VERSION 5.8 ;
BUSBITCHARS "[]" ;
DIVIDERCHAR "/" ;
UNITS
    DATABASE MICRONS 1000 ;
END UNITS

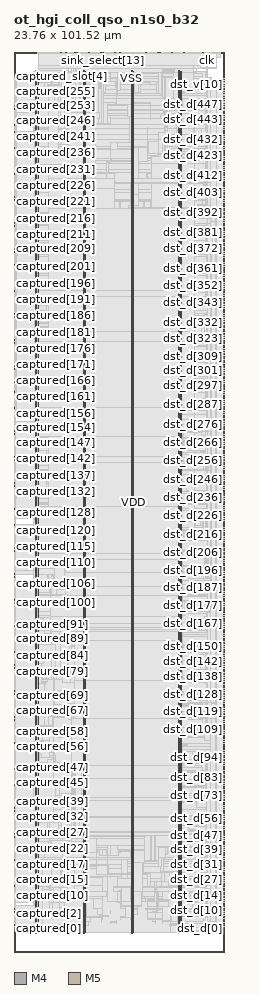
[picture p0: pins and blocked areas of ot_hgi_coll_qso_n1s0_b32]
MACRO ot_hgi_coll_qso_n1s0_b32
  FOREIGN ot_hgi_coll_qso_n1s0_b32 0 0 ;
  CLASS BLOCK ;
  SIZE 23.76 BY 101.52 ;
  PIN captured[0]
    DIRECTION INPUT ;
    USE SIGNAL ;
    PORT
      LAYER M4 ;
        RECT  0 2.688 0.084 2.712 ;
    END
  END captured[0]
  PIN captured[100]
    DIRECTION INPUT ;
    USE SIGNAL ;
    PORT
      LAYER M4 ;
        RECT  0 39.36 0.084 39.384 ;
    END
  END captured[100]
  PIN captured[101]
    DIRECTION INPUT ;
    USE SIGNAL ;
    PORT
      LAYER M4 ;
        RECT  0 39.696 0.084 39.72 ;
    END
  END captured[101]
  PIN captured[102]
    DIRECTION INPUT ;
    USE SIGNAL ;
    PORT
      LAYER M4 ;
        RECT  0 40.08 0.084 40.104 ;
    END
  END captured[102]
  PIN captured[103]
    DIRECTION INPUT ;
    USE SIGNAL ;
    PORT
      LAYER M4 ;
        RECT  0 40.416 0.084 40.44 ;
    END
  END captured[103]
  PIN captured[104]
    DIRECTION INPUT ;
    USE SIGNAL ;
    PORT
      LAYER M4 ;
        RECT  0 40.8 0.084 40.824 ;
    END
  END captured[104]
  PIN captured[105]
    DIRECTION INPUT ;
    USE SIGNAL ;
    PORT
      LAYER M4 ;
        RECT  0 41.184 0.084 41.208 ;
    END
  END captured[105]
  PIN captured[106]
    DIRECTION INPUT ;
    USE SIGNAL ;
    PORT
      LAYER M4 ;
        RECT  0 41.52 0.084 41.544 ;
    END
  END captured[106]
  PIN captured[107]
    DIRECTION INPUT ;
    USE SIGNAL ;
    PORT
      LAYER M4 ;
        RECT  0 41.904 0.084 41.928 ;
    END
  END captured[107]
  PIN captured[108]
    DIRECTION INPUT ;
    USE SIGNAL ;
    PORT
      LAYER M4 ;
        RECT  0 42.288 0.084 42.312 ;
    END
  END captured[108]
  PIN captured[109]
    DIRECTION INPUT ;
    USE SIGNAL ;
    PORT
      LAYER M4 ;
        RECT  0 42.624 0.084 42.648 ;
    END
  END captured[109]
  PIN captured[10]
    DIRECTION INPUT ;
    USE SIGNAL ;
    PORT
      LAYER M4 ;
        RECT  0 6.336 0.084 6.36 ;
    END
  END captured[10]
  PIN captured[110]
    DIRECTION INPUT ;
    USE SIGNAL ;
    PORT
      LAYER M4 ;
        RECT  0 43.008 0.084 43.032 ;
    END
  END captured[110]
  PIN captured[111]
    DIRECTION INPUT ;
    USE SIGNAL ;
    PORT
      LAYER M4 ;
        RECT  0 43.392 0.084 43.416 ;
    END
  END captured[111]
  PIN captured[112]
    DIRECTION INPUT ;
    USE SIGNAL ;
    PORT
      LAYER M4 ;
        RECT  0 43.728 0.084 43.752 ;
    END
  END captured[112]
  PIN captured[113]
    DIRECTION INPUT ;
    USE SIGNAL ;
    PORT
      LAYER M4 ;
        RECT  0 44.112 0.084 44.136 ;
    END
  END captured[113]
  PIN captured[114]
    DIRECTION INPUT ;
    USE SIGNAL ;
    PORT
      LAYER M4 ;
        RECT  0 44.496 0.084 44.52 ;
    END
  END captured[114]
  PIN captured[115]
    DIRECTION INPUT ;
    USE SIGNAL ;
    PORT
      LAYER M4 ;
        RECT  0 44.832 0.084 44.856 ;
    END
  END captured[115]
  PIN captured[116]
    DIRECTION INPUT ;
    USE SIGNAL ;
    PORT
      LAYER M4 ;
        RECT  0 45.216 0.084 45.24 ;
    END
  END captured[116]
  PIN captured[117]
    DIRECTION INPUT ;
    USE SIGNAL ;
    PORT
      LAYER M4 ;
        RECT  0 45.552 0.084 45.576 ;
    END
  END captured[117]
  PIN captured[118]
    DIRECTION INPUT ;
    USE SIGNAL ;
    PORT
      LAYER M4 ;
        RECT  0 45.936 0.084 45.96 ;
    END
  END captured[118]
  PIN captured[119]
    DIRECTION INPUT ;
    USE SIGNAL ;
    PORT
      LAYER M4 ;
        RECT  0 46.32 0.084 46.344 ;
    END
  END captured[119]
  PIN captured[11]
    DIRECTION INPUT ;
    USE SIGNAL ;
    PORT
      LAYER M4 ;
        RECT  0 6.72 0.084 6.744 ;
    END
  END captured[11]
  PIN captured[120]
    DIRECTION INPUT ;
    USE SIGNAL ;
    PORT
      LAYER M4 ;
        RECT  0 46.656 0.084 46.68 ;
    END
  END captured[120]
  PIN captured[121]
    DIRECTION INPUT ;
    USE SIGNAL ;
    PORT
      LAYER M4 ;
        RECT  0 47.04 0.084 47.064 ;
    END
  END captured[121]
  PIN captured[122]
    DIRECTION INPUT ;
    USE SIGNAL ;
    PORT
      LAYER M4 ;
        RECT  0 47.424 0.084 47.448 ;
    END
  END captured[122]
  PIN captured[123]
    DIRECTION INPUT ;
    USE SIGNAL ;
    PORT
      LAYER M4 ;
        RECT  0 47.76 0.084 47.784 ;
    END
  END captured[123]
  PIN captured[124]
    DIRECTION INPUT ;
    USE SIGNAL ;
    PORT
      LAYER M4 ;
        RECT  0 48.144 0.084 48.168 ;
    END
  END captured[124]
  PIN captured[125]
    DIRECTION INPUT ;
    USE SIGNAL ;
    PORT
      LAYER M4 ;
        RECT  0 48.528 0.084 48.552 ;
    END
  END captured[125]
  PIN captured[126]
    DIRECTION INPUT ;
    USE SIGNAL ;
    PORT
      LAYER M4 ;
        RECT  0 48.864 0.084 48.888 ;
    END
  END captured[126]
  PIN captured[127]
    DIRECTION INPUT ;
    USE SIGNAL ;
    PORT
      LAYER M4 ;
        RECT  0 49.248 0.084 49.272 ;
    END
  END captured[127]
  PIN captured[128]
    DIRECTION INPUT ;
    USE SIGNAL ;
    PORT
      LAYER M4 ;
        RECT  0 49.584 0.084 49.608 ;
    END
  END captured[128]
  PIN captured[129]
    DIRECTION INPUT ;
    USE SIGNAL ;
    PORT
      LAYER M4 ;
        RECT  0 49.968 0.084 49.992 ;
    END
  END captured[129]
  PIN captured[12]
    DIRECTION INPUT ;
    USE SIGNAL ;
    PORT
      LAYER M4 ;
        RECT  0 7.056 0.084 7.08 ;
    END
  END captured[12]
  PIN captured[130]
    DIRECTION INPUT ;
    USE SIGNAL ;
    PORT
      LAYER M4 ;
        RECT  0 50.352 0.084 50.376 ;
    END
  END captured[130]
  PIN captured[131]
    DIRECTION INPUT ;
    USE SIGNAL ;
    PORT
      LAYER M4 ;
        RECT  0 50.688 0.084 50.712 ;
    END
  END captured[131]
  PIN captured[132]
    DIRECTION INPUT ;
    USE SIGNAL ;
    PORT
      LAYER M4 ;
        RECT  0 51.072 0.084 51.096 ;
    END
  END captured[132]
  PIN captured[133]
    DIRECTION INPUT ;
    USE SIGNAL ;
    PORT
      LAYER M4 ;
        RECT  0 51.456 0.084 51.48 ;
    END
  END captured[133]
  PIN captured[134]
    DIRECTION INPUT ;
    USE SIGNAL ;
    PORT
      LAYER M4 ;
        RECT  0 51.792 0.084 51.816 ;
    END
  END captured[134]
  PIN captured[135]
    DIRECTION INPUT ;
    USE SIGNAL ;
    PORT
      LAYER M4 ;
        RECT  0 52.176 0.084 52.2 ;
    END
  END captured[135]
  PIN captured[136]
    DIRECTION INPUT ;
    USE SIGNAL ;
    PORT
      LAYER M4 ;
        RECT  0 52.56 0.084 52.584 ;
    END
  END captured[136]
  PIN captured[137]
    DIRECTION INPUT ;
    USE SIGNAL ;
    PORT
      LAYER M4 ;
        RECT  0 52.896 0.084 52.92 ;
    END
  END captured[137]
  PIN captured[138]
    DIRECTION INPUT ;
    USE SIGNAL ;
    PORT
      LAYER M4 ;
        RECT  0 53.28 0.084 53.304 ;
    END
  END captured[138]
  PIN captured[139]
    DIRECTION INPUT ;
    USE SIGNAL ;
    PORT
      LAYER M4 ;
        RECT  0 53.664 0.084 53.688 ;
    END
  END captured[139]
  PIN captured[13]
    DIRECTION INPUT ;
    USE SIGNAL ;
    PORT
      LAYER M4 ;
        RECT  0 7.44 0.084 7.464 ;
    END
  END captured[13]
  PIN captured[140]
    DIRECTION INPUT ;
    USE SIGNAL ;
    PORT
      LAYER M4 ;
        RECT  0 54 0.084 54.024 ;
    END
  END captured[140]
  PIN captured[141]
    DIRECTION INPUT ;
    USE SIGNAL ;
    PORT
      LAYER M4 ;
        RECT  0 54.384 0.084 54.408 ;
    END
  END captured[141]
  PIN captured[142]
    DIRECTION INPUT ;
    USE SIGNAL ;
    PORT
      LAYER M4 ;
        RECT  0 54.72 0.084 54.744 ;
    END
  END captured[142]
  PIN captured[143]
    DIRECTION INPUT ;
    USE SIGNAL ;
    PORT
      LAYER M4 ;
        RECT  0 55.104 0.084 55.128 ;
    END
  END captured[143]
  PIN captured[144]
    DIRECTION INPUT ;
    USE SIGNAL ;
    PORT
      LAYER M4 ;
        RECT  0 55.488 0.084 55.512 ;
    END
  END captured[144]
  PIN captured[145]
    DIRECTION INPUT ;
    USE SIGNAL ;
    PORT
      LAYER M4 ;
        RECT  0 55.824 0.084 55.848 ;
    END
  END captured[145]
  PIN captured[146]
    DIRECTION INPUT ;
    USE SIGNAL ;
    PORT
      LAYER M4 ;
        RECT  0 56.208 0.084 56.232 ;
    END
  END captured[146]
  PIN captured[147]
    DIRECTION INPUT ;
    USE SIGNAL ;
    PORT
      LAYER M4 ;
        RECT  0 56.592 0.084 56.616 ;
    END
  END captured[147]
  PIN captured[148]
    DIRECTION INPUT ;
    USE SIGNAL ;
    PORT
      LAYER M4 ;
        RECT  0 56.928 0.084 56.952 ;
    END
  END captured[148]
  PIN captured[149]
    DIRECTION INPUT ;
    USE SIGNAL ;
    PORT
      LAYER M4 ;
        RECT  0 57.312 0.084 57.336 ;
    END
  END captured[149]
  PIN captured[14]
    DIRECTION INPUT ;
    USE SIGNAL ;
    PORT
      LAYER M4 ;
        RECT  0 7.824 0.084 7.848 ;
    END
  END captured[14]
  PIN captured[150]
    DIRECTION INPUT ;
    USE SIGNAL ;
    PORT
      LAYER M4 ;
        RECT  0 57.696 0.084 57.72 ;
    END
  END captured[150]
  PIN captured[151]
    DIRECTION INPUT ;
    USE SIGNAL ;
    PORT
      LAYER M4 ;
        RECT  0 58.032 0.084 58.056 ;
    END
  END captured[151]
  PIN captured[152]
    DIRECTION INPUT ;
    USE SIGNAL ;
    PORT
      LAYER M4 ;
        RECT  0 58.416 0.084 58.44 ;
    END
  END captured[152]
  PIN captured[153]
    DIRECTION INPUT ;
    USE SIGNAL ;
    PORT
      LAYER M4 ;
        RECT  0 58.752 0.084 58.776 ;
    END
  END captured[153]
  PIN captured[154]
    DIRECTION INPUT ;
    USE SIGNAL ;
    PORT
      LAYER M4 ;
        RECT  0 59.136 0.084 59.16 ;
    END
  END captured[154]
  PIN captured[155]
    DIRECTION INPUT ;
    USE SIGNAL ;
    PORT
      LAYER M4 ;
        RECT  0 59.52 0.084 59.544 ;
    END
  END captured[155]
  PIN captured[156]
    DIRECTION INPUT ;
    USE SIGNAL ;
    PORT
      LAYER M4 ;
        RECT  0 59.856 0.084 59.88 ;
    END
  END captured[156]
  PIN captured[157]
    DIRECTION INPUT ;
    USE SIGNAL ;
    PORT
      LAYER M4 ;
        RECT  0 60.24 0.084 60.264 ;
    END
  END captured[157]
  PIN captured[158]
    DIRECTION INPUT ;
    USE SIGNAL ;
    PORT
      LAYER M4 ;
        RECT  0 60.624 0.084 60.648 ;
    END
  END captured[158]
  PIN captured[159]
    DIRECTION INPUT ;
    USE SIGNAL ;
    PORT
      LAYER M4 ;
        RECT  0 60.96 0.084 60.984 ;
    END
  END captured[159]
  PIN captured[15]
    DIRECTION INPUT ;
    USE SIGNAL ;
    PORT
      LAYER M4 ;
        RECT  0 8.16 0.084 8.184 ;
    END
  END captured[15]
  PIN captured[160]
    DIRECTION INPUT ;
    USE SIGNAL ;
    PORT
      LAYER M4 ;
        RECT  0 61.344 0.084 61.368 ;
    END
  END captured[160]
  PIN captured[161]
    DIRECTION INPUT ;
    USE SIGNAL ;
    PORT
      LAYER M4 ;
        RECT  0 61.728 0.084 61.752 ;
    END
  END captured[161]
  PIN captured[162]
    DIRECTION INPUT ;
    USE SIGNAL ;
    PORT
      LAYER M4 ;
        RECT  0 62.064 0.084 62.088 ;
    END
  END captured[162]
  PIN captured[163]
    DIRECTION INPUT ;
    USE SIGNAL ;
    PORT
      LAYER M4 ;
        RECT  0 62.448 0.084 62.472 ;
    END
  END captured[163]
  PIN captured[164]
    DIRECTION INPUT ;
    USE SIGNAL ;
    PORT
      LAYER M4 ;
        RECT  0 62.784 0.084 62.808 ;
    END
  END captured[164]
  PIN captured[165]
    DIRECTION INPUT ;
    USE SIGNAL ;
    PORT
      LAYER M4 ;
        RECT  0 63.168 0.084 63.192 ;
    END
  END captured[165]
  PIN captured[166]
    DIRECTION INPUT ;
    USE SIGNAL ;
    PORT
      LAYER M4 ;
        RECT  0 63.552 0.084 63.576 ;
    END
  END captured[166]
  PIN captured[167]
    DIRECTION INPUT ;
    USE SIGNAL ;
    PORT
      LAYER M4 ;
        RECT  0 63.888 0.084 63.912 ;
    END
  END captured[167]
  PIN captured[168]
    DIRECTION INPUT ;
    USE SIGNAL ;
    PORT
      LAYER M4 ;
        RECT  0 64.272 0.084 64.296 ;
    END
  END captured[168]
  PIN captured[169]
    DIRECTION INPUT ;
    USE SIGNAL ;
    PORT
      LAYER M4 ;
        RECT  0 64.656 0.084 64.68 ;
    END
  END captured[169]
  PIN captured[16]
    DIRECTION INPUT ;
    USE SIGNAL ;
    PORT
      LAYER M4 ;
        RECT  0 8.544 0.084 8.568 ;
    END
  END captured[16]
  PIN captured[170]
    DIRECTION INPUT ;
    USE SIGNAL ;
    PORT
      LAYER M4 ;
        RECT  0 64.992 0.084 65.016 ;
    END
  END captured[170]
  PIN captured[171]
    DIRECTION INPUT ;
    USE SIGNAL ;
    PORT
      LAYER M4 ;
        RECT  0 65.376 0.084 65.4 ;
    END
  END captured[171]
  PIN captured[172]
    DIRECTION INPUT ;
    USE SIGNAL ;
    PORT
      LAYER M4 ;
        RECT  0 65.76 0.084 65.784 ;
    END
  END captured[172]
  PIN captured[173]
    DIRECTION INPUT ;
    USE SIGNAL ;
    PORT
      LAYER M4 ;
        RECT  0 66.096 0.084 66.12 ;
    END
  END captured[173]
  PIN captured[174]
    DIRECTION INPUT ;
    USE SIGNAL ;
    PORT
      LAYER M4 ;
        RECT  0 66.48 0.084 66.504 ;
    END
  END captured[174]
  PIN captured[175]
    DIRECTION INPUT ;
    USE SIGNAL ;
    PORT
      LAYER M4 ;
        RECT  0 66.864 0.084 66.888 ;
    END
  END captured[175]
  PIN captured[176]
    DIRECTION INPUT ;
    USE SIGNAL ;
    PORT
      LAYER M4 ;
        RECT  0 67.2 0.084 67.224 ;
    END
  END captured[176]
  PIN captured[177]
    DIRECTION INPUT ;
    USE SIGNAL ;
    PORT
      LAYER M4 ;
        RECT  0 67.584 0.084 67.608 ;
    END
  END captured[177]
  PIN captured[178]
    DIRECTION INPUT ;
    USE SIGNAL ;
    PORT
      LAYER M4 ;
        RECT  0 67.92 0.084 67.944 ;
    END
  END captured[178]
  PIN captured[179]
    DIRECTION INPUT ;
    USE SIGNAL ;
    PORT
      LAYER M4 ;
        RECT  0 68.304 0.084 68.328 ;
    END
  END captured[179]
  PIN captured[17]
    DIRECTION INPUT ;
    USE SIGNAL ;
    PORT
      LAYER M4 ;
        RECT  0 8.928 0.084 8.952 ;
    END
  END captured[17]
  PIN captured[180]
    DIRECTION INPUT ;
    USE SIGNAL ;
    PORT
      LAYER M4 ;
        RECT  0 68.688 0.084 68.712 ;
    END
  END captured[180]
  PIN captured[181]
    DIRECTION INPUT ;
    USE SIGNAL ;
    PORT
      LAYER M4 ;
        RECT  0 69.024 0.084 69.048 ;
    END
  END captured[181]
  PIN captured[182]
    DIRECTION INPUT ;
    USE SIGNAL ;
    PORT
      LAYER M4 ;
        RECT  0 69.408 0.084 69.432 ;
    END
  END captured[182]
  PIN captured[183]
    DIRECTION INPUT ;
    USE SIGNAL ;
    PORT
      LAYER M4 ;
        RECT  0 69.792 0.084 69.816 ;
    END
  END captured[183]
  PIN captured[184]
    DIRECTION INPUT ;
    USE SIGNAL ;
    PORT
      LAYER M4 ;
        RECT  0 70.128 0.084 70.152 ;
    END
  END captured[184]
  PIN captured[185]
    DIRECTION INPUT ;
    USE SIGNAL ;
    PORT
      LAYER M4 ;
        RECT  0 70.512 0.084 70.536 ;
    END
  END captured[185]
  PIN captured[186]
    DIRECTION INPUT ;
    USE SIGNAL ;
    PORT
      LAYER M4 ;
        RECT  0 70.896 0.084 70.92 ;
    END
  END captured[186]
  PIN captured[187]
    DIRECTION INPUT ;
    USE SIGNAL ;
    PORT
      LAYER M4 ;
        RECT  0 71.232 0.084 71.256 ;
    END
  END captured[187]
  PIN captured[188]
    DIRECTION INPUT ;
    USE SIGNAL ;
    PORT
      LAYER M4 ;
        RECT  0 71.616 0.084 71.64 ;
    END
  END captured[188]
  PIN captured[189]
    DIRECTION INPUT ;
    USE SIGNAL ;
    PORT
      LAYER M4 ;
        RECT  0 71.952 0.084 71.976 ;
    END
  END captured[189]
  PIN captured[18]
    DIRECTION INPUT ;
    USE SIGNAL ;
    PORT
      LAYER M4 ;
        RECT  0 9.264 0.084 9.288 ;
    END
  END captured[18]
  PIN captured[190]
    DIRECTION INPUT ;
    USE SIGNAL ;
    PORT
      LAYER M4 ;
        RECT  0 72.336 0.084 72.36 ;
    END
  END captured[190]
  PIN captured[191]
    DIRECTION INPUT ;
    USE SIGNAL ;
    PORT
      LAYER M4 ;
        RECT  0 72.72 0.084 72.744 ;
    END
  END captured[191]
  PIN captured[192]
    DIRECTION INPUT ;
    USE SIGNAL ;
    PORT
      LAYER M4 ;
        RECT  0 73.056 0.084 73.08 ;
    END
  END captured[192]
  PIN captured[193]
    DIRECTION INPUT ;
    USE SIGNAL ;
    PORT
      LAYER M4 ;
        RECT  0 73.44 0.084 73.464 ;
    END
  END captured[193]
  PIN captured[194]
    DIRECTION INPUT ;
    USE SIGNAL ;
    PORT
      LAYER M4 ;
        RECT  0 73.824 0.084 73.848 ;
    END
  END captured[194]
  PIN captured[195]
    DIRECTION INPUT ;
    USE SIGNAL ;
    PORT
      LAYER M4 ;
        RECT  0 74.16 0.084 74.184 ;
    END
  END captured[195]
  PIN captured[196]
    DIRECTION INPUT ;
    USE SIGNAL ;
    PORT
      LAYER M4 ;
        RECT  0 74.544 0.084 74.568 ;
    END
  END captured[196]
  PIN captured[197]
    DIRECTION INPUT ;
    USE SIGNAL ;
    PORT
      LAYER M4 ;
        RECT  0 74.928 0.084 74.952 ;
    END
  END captured[197]
  PIN captured[198]
    DIRECTION INPUT ;
    USE SIGNAL ;
    PORT
      LAYER M4 ;
        RECT  0 75.264 0.084 75.288 ;
    END
  END captured[198]
  PIN captured[199]
    DIRECTION INPUT ;
    USE SIGNAL ;
    PORT
      LAYER M4 ;
        RECT  0 75.648 0.084 75.672 ;
    END
  END captured[199]
  PIN captured[19]
    DIRECTION INPUT ;
    USE SIGNAL ;
    PORT
      LAYER M4 ;
        RECT  0 9.648 0.084 9.672 ;
    END
  END captured[19]
  PIN captured[1]
    DIRECTION INPUT ;
    USE SIGNAL ;
    PORT
      LAYER M4 ;
        RECT  0 3.024 0.084 3.048 ;
    END
  END captured[1]
  PIN captured[200]
    DIRECTION INPUT ;
    USE SIGNAL ;
    PORT
      LAYER M4 ;
        RECT  0 75.984 0.084 76.008 ;
    END
  END captured[200]
  PIN captured[201]
    DIRECTION INPUT ;
    USE SIGNAL ;
    PORT
      LAYER M4 ;
        RECT  0 76.368 0.084 76.392 ;
    END
  END captured[201]
  PIN captured[202]
    DIRECTION INPUT ;
    USE SIGNAL ;
    PORT
      LAYER M4 ;
        RECT  0 76.752 0.084 76.776 ;
    END
  END captured[202]
  PIN captured[203]
    DIRECTION INPUT ;
    USE SIGNAL ;
    PORT
      LAYER M4 ;
        RECT  0 77.088 0.084 77.112 ;
    END
  END captured[203]
  PIN captured[204]
    DIRECTION INPUT ;
    USE SIGNAL ;
    PORT
      LAYER M4 ;
        RECT  0 77.472 0.084 77.496 ;
    END
  END captured[204]
  PIN captured[205]
    DIRECTION INPUT ;
    USE SIGNAL ;
    PORT
      LAYER M4 ;
        RECT  0 77.856 0.084 77.88 ;
    END
  END captured[205]
  PIN captured[206]
    DIRECTION INPUT ;
    USE SIGNAL ;
    PORT
      LAYER M4 ;
        RECT  0 78.192 0.084 78.216 ;
    END
  END captured[206]
  PIN captured[207]
    DIRECTION INPUT ;
    USE SIGNAL ;
    PORT
      LAYER M4 ;
        RECT  0 78.576 0.084 78.6 ;
    END
  END captured[207]
  PIN captured[208]
    DIRECTION INPUT ;
    USE SIGNAL ;
    PORT
      LAYER M4 ;
        RECT  0 78.96 0.084 78.984 ;
    END
  END captured[208]
  PIN captured[209]
    DIRECTION INPUT ;
    USE SIGNAL ;
    PORT
      LAYER M4 ;
        RECT  0 79.296 0.084 79.32 ;
    END
  END captured[209]
  PIN captured[20]
    DIRECTION INPUT ;
    USE SIGNAL ;
    PORT
      LAYER M4 ;
        RECT  0 9.984 0.084 10.008 ;
    END
  END captured[20]
  PIN captured[210]
    DIRECTION INPUT ;
    USE SIGNAL ;
    PORT
      LAYER M4 ;
        RECT  0 79.68 0.084 79.704 ;
    END
  END captured[210]
  PIN captured[211]
    DIRECTION INPUT ;
    USE SIGNAL ;
    PORT
      LAYER M4 ;
        RECT  0 80.064 0.084 80.088 ;
    END
  END captured[211]
  PIN captured[212]
    DIRECTION INPUT ;
    USE SIGNAL ;
    PORT
      LAYER M4 ;
        RECT  0 80.4 0.084 80.424 ;
    END
  END captured[212]
  PIN captured[213]
    DIRECTION INPUT ;
    USE SIGNAL ;
    PORT
      LAYER M4 ;
        RECT  0 80.784 0.084 80.808 ;
    END
  END captured[213]
  PIN captured[214]
    DIRECTION INPUT ;
    USE SIGNAL ;
    PORT
      LAYER M4 ;
        RECT  0 81.12 0.084 81.144 ;
    END
  END captured[214]
  PIN captured[215]
    DIRECTION INPUT ;
    USE SIGNAL ;
    PORT
      LAYER M4 ;
        RECT  0 81.504 0.084 81.528 ;
    END
  END captured[215]
  PIN captured[216]
    DIRECTION INPUT ;
    USE SIGNAL ;
    PORT
      LAYER M4 ;
        RECT  0 81.888 0.084 81.912 ;
    END
  END captured[216]
  PIN captured[217]
    DIRECTION INPUT ;
    USE SIGNAL ;
    PORT
      LAYER M4 ;
        RECT  0 82.224 0.084 82.248 ;
    END
  END captured[217]
  PIN captured[218]
    DIRECTION INPUT ;
    USE SIGNAL ;
    PORT
      LAYER M4 ;
        RECT  0 82.608 0.084 82.632 ;
    END
  END captured[218]
  PIN captured[219]
    DIRECTION INPUT ;
    USE SIGNAL ;
    PORT
      LAYER M4 ;
        RECT  0 82.992 0.084 83.016 ;
    END
  END captured[219]
  PIN captured[21]
    DIRECTION INPUT ;
    USE SIGNAL ;
    PORT
      LAYER M4 ;
        RECT  0 10.368 0.084 10.392 ;
    END
  END captured[21]
  PIN captured[220]
    DIRECTION INPUT ;
    USE SIGNAL ;
    PORT
      LAYER M4 ;
        RECT  0 83.328 0.084 83.352 ;
    END
  END captured[220]
  PIN captured[221]
    DIRECTION INPUT ;
    USE SIGNAL ;
    PORT
      LAYER M4 ;
        RECT  0 83.712 0.084 83.736 ;
    END
  END captured[221]
  PIN captured[222]
    DIRECTION INPUT ;
    USE SIGNAL ;
    PORT
      LAYER M4 ;
        RECT  0 84.096 0.084 84.12 ;
    END
  END captured[222]
  PIN captured[223]
    DIRECTION INPUT ;
    USE SIGNAL ;
    PORT
      LAYER M4 ;
        RECT  0 84.432 0.084 84.456 ;
    END
  END captured[223]
  PIN captured[224]
    DIRECTION INPUT ;
    USE SIGNAL ;
    PORT
      LAYER M4 ;
        RECT  0 84.816 0.084 84.84 ;
    END
  END captured[224]
  PIN captured[225]
    DIRECTION INPUT ;
    USE SIGNAL ;
    PORT
      LAYER M4 ;
        RECT  0 85.152 0.084 85.176 ;
    END
  END captured[225]
  PIN captured[226]
    DIRECTION INPUT ;
    USE SIGNAL ;
    PORT
      LAYER M4 ;
        RECT  0 85.536 0.084 85.56 ;
    END
  END captured[226]
  PIN captured[227]
    DIRECTION INPUT ;
    USE SIGNAL ;
    PORT
      LAYER M4 ;
        RECT  0 85.92 0.084 85.944 ;
    END
  END captured[227]
  PIN captured[228]
    DIRECTION INPUT ;
    USE SIGNAL ;
    PORT
      LAYER M4 ;
        RECT  0 86.256 0.084 86.28 ;
    END
  END captured[228]
  PIN captured[229]
    DIRECTION INPUT ;
    USE SIGNAL ;
    PORT
      LAYER M4 ;
        RECT  0 86.64 0.084 86.664 ;
    END
  END captured[229]
  PIN captured[22]
    DIRECTION INPUT ;
    USE SIGNAL ;
    PORT
      LAYER M4 ;
        RECT  0 10.752 0.084 10.776 ;
    END
  END captured[22]
  PIN captured[230]
    DIRECTION INPUT ;
    USE SIGNAL ;
    PORT
      LAYER M4 ;
        RECT  0 87.024 0.084 87.048 ;
    END
  END captured[230]
  PIN captured[231]
    DIRECTION INPUT ;
    USE SIGNAL ;
    PORT
      LAYER M4 ;
        RECT  0 87.36 0.084 87.384 ;
    END
  END captured[231]
  PIN captured[232]
    DIRECTION INPUT ;
    USE SIGNAL ;
    PORT
      LAYER M4 ;
        RECT  0 87.744 0.084 87.768 ;
    END
  END captured[232]
  PIN captured[233]
    DIRECTION INPUT ;
    USE SIGNAL ;
    PORT
      LAYER M4 ;
        RECT  0 88.128 0.084 88.152 ;
    END
  END captured[233]
  PIN captured[234]
    DIRECTION INPUT ;
    USE SIGNAL ;
    PORT
      LAYER M4 ;
        RECT  0 88.464 0.084 88.488 ;
    END
  END captured[234]
  PIN captured[235]
    DIRECTION INPUT ;
    USE SIGNAL ;
    PORT
      LAYER M4 ;
        RECT  0 88.848 0.084 88.872 ;
    END
  END captured[235]
  PIN captured[236]
    DIRECTION INPUT ;
    USE SIGNAL ;
    PORT
      LAYER M4 ;
        RECT  0 89.232 0.084 89.256 ;
    END
  END captured[236]
  PIN captured[237]
    DIRECTION INPUT ;
    USE SIGNAL ;
    PORT
      LAYER M4 ;
        RECT  0 89.568 0.084 89.592 ;
    END
  END captured[237]
  PIN captured[238]
    DIRECTION INPUT ;
    USE SIGNAL ;
    PORT
      LAYER M4 ;
        RECT  0 89.952 0.084 89.976 ;
    END
  END captured[238]
  PIN captured[239]
    DIRECTION INPUT ;
    USE SIGNAL ;
    PORT
      LAYER M4 ;
        RECT  0 90.288 0.084 90.312 ;
    END
  END captured[239]
  PIN captured[23]
    DIRECTION INPUT ;
    USE SIGNAL ;
    PORT
      LAYER M4 ;
        RECT  0 11.088 0.084 11.112 ;
    END
  END captured[23]
  PIN captured[240]
    DIRECTION INPUT ;
    USE SIGNAL ;
    PORT
      LAYER M4 ;
        RECT  0 90.672 0.084 90.696 ;
    END
  END captured[240]
  PIN captured[241]
    DIRECTION INPUT ;
    USE SIGNAL ;
    PORT
      LAYER M4 ;
        RECT  0 91.056 0.084 91.08 ;
    END
  END captured[241]
  PIN captured[242]
    DIRECTION INPUT ;
    USE SIGNAL ;
    PORT
      LAYER M4 ;
        RECT  0 91.392 0.084 91.416 ;
    END
  END captured[242]
  PIN captured[243]
    DIRECTION INPUT ;
    USE SIGNAL ;
    PORT
      LAYER M4 ;
        RECT  0 91.776 0.084 91.8 ;
    END
  END captured[243]
  PIN captured[244]
    DIRECTION INPUT ;
    USE SIGNAL ;
    PORT
      LAYER M4 ;
        RECT  0 92.16 0.084 92.184 ;
    END
  END captured[244]
  PIN captured[245]
    DIRECTION INPUT ;
    USE SIGNAL ;
    PORT
      LAYER M4 ;
        RECT  0 92.496 0.084 92.52 ;
    END
  END captured[245]
  PIN captured[246]
    DIRECTION INPUT ;
    USE SIGNAL ;
    PORT
      LAYER M4 ;
        RECT  0 92.88 0.084 92.904 ;
    END
  END captured[246]
  PIN captured[247]
    DIRECTION INPUT ;
    USE SIGNAL ;
    PORT
      LAYER M4 ;
        RECT  0 93.264 0.084 93.288 ;
    END
  END captured[247]
  PIN captured[248]
    DIRECTION INPUT ;
    USE SIGNAL ;
    PORT
      LAYER M4 ;
        RECT  0 93.6 0.084 93.624 ;
    END
  END captured[248]
  PIN captured[249]
    DIRECTION INPUT ;
    USE SIGNAL ;
    PORT
      LAYER M4 ;
        RECT  0 93.984 0.084 94.008 ;
    END
  END captured[249]
  PIN captured[24]
    DIRECTION INPUT ;
    USE SIGNAL ;
    PORT
      LAYER M4 ;
        RECT  0 11.472 0.084 11.496 ;
    END
  END captured[24]
  PIN captured[250]
    DIRECTION INPUT ;
    USE SIGNAL ;
    PORT
      LAYER M4 ;
        RECT  0 94.32 0.084 94.344 ;
    END
  END captured[250]
  PIN captured[251]
    DIRECTION INPUT ;
    USE SIGNAL ;
    PORT
      LAYER M4 ;
        RECT  0 94.704 0.084 94.728 ;
    END
  END captured[251]
  PIN captured[252]
    DIRECTION INPUT ;
    USE SIGNAL ;
    PORT
      LAYER M4 ;
        RECT  0 95.088 0.084 95.112 ;
    END
  END captured[252]
  PIN captured[253]
    DIRECTION INPUT ;
    USE SIGNAL ;
    PORT
      LAYER M4 ;
        RECT  0 95.424 0.084 95.448 ;
    END
  END captured[253]
  PIN captured[254]
    DIRECTION INPUT ;
    USE SIGNAL ;
    PORT
      LAYER M4 ;
        RECT  0 95.808 0.084 95.832 ;
    END
  END captured[254]
  PIN captured[255]
    DIRECTION INPUT ;
    USE SIGNAL ;
    PORT
      LAYER M4 ;
        RECT  0 96.192 0.084 96.216 ;
    END
  END captured[255]
  PIN captured[25]
    DIRECTION INPUT ;
    USE SIGNAL ;
    PORT
      LAYER M4 ;
        RECT  0 11.856 0.084 11.88 ;
    END
  END captured[25]
  PIN captured[26]
    DIRECTION INPUT ;
    USE SIGNAL ;
    PORT
      LAYER M4 ;
        RECT  0 12.192 0.084 12.216 ;
    END
  END captured[26]
  PIN captured[27]
    DIRECTION INPUT ;
    USE SIGNAL ;
    PORT
      LAYER M4 ;
        RECT  0 12.576 0.084 12.6 ;
    END
  END captured[27]
  PIN captured[28]
    DIRECTION INPUT ;
    USE SIGNAL ;
    PORT
      LAYER M4 ;
        RECT  0 12.96 0.084 12.984 ;
    END
  END captured[28]
  PIN captured[29]
    DIRECTION INPUT ;
    USE SIGNAL ;
    PORT
      LAYER M4 ;
        RECT  0 13.296 0.084 13.32 ;
    END
  END captured[29]
  PIN captured[2]
    DIRECTION INPUT ;
    USE SIGNAL ;
    PORT
      LAYER M4 ;
        RECT  0 3.408 0.084 3.432 ;
    END
  END captured[2]
  PIN captured[30]
    DIRECTION INPUT ;
    USE SIGNAL ;
    PORT
      LAYER M4 ;
        RECT  0 13.68 0.084 13.704 ;
    END
  END captured[30]
  PIN captured[31]
    DIRECTION INPUT ;
    USE SIGNAL ;
    PORT
      LAYER M4 ;
        RECT  0 14.016 0.084 14.04 ;
    END
  END captured[31]
  PIN captured[32]
    DIRECTION INPUT ;
    USE SIGNAL ;
    PORT
      LAYER M4 ;
        RECT  0 14.4 0.084 14.424 ;
    END
  END captured[32]
  PIN captured[33]
    DIRECTION INPUT ;
    USE SIGNAL ;
    PORT
      LAYER M4 ;
        RECT  0 14.784 0.084 14.808 ;
    END
  END captured[33]
  PIN captured[34]
    DIRECTION INPUT ;
    USE SIGNAL ;
    PORT
      LAYER M4 ;
        RECT  0 15.12 0.084 15.144 ;
    END
  END captured[34]
  PIN captured[35]
    DIRECTION INPUT ;
    USE SIGNAL ;
    PORT
      LAYER M4 ;
        RECT  0 15.504 0.084 15.528 ;
    END
  END captured[35]
  PIN captured[36]
    DIRECTION INPUT ;
    USE SIGNAL ;
    PORT
      LAYER M4 ;
        RECT  0 15.888 0.084 15.912 ;
    END
  END captured[36]
  PIN captured[37]
    DIRECTION INPUT ;
    USE SIGNAL ;
    PORT
      LAYER M4 ;
        RECT  0 16.224 0.084 16.248 ;
    END
  END captured[37]
  PIN captured[38]
    DIRECTION INPUT ;
    USE SIGNAL ;
    PORT
      LAYER M4 ;
        RECT  0 16.608 0.084 16.632 ;
    END
  END captured[38]
  PIN captured[39]
    DIRECTION INPUT ;
    USE SIGNAL ;
    PORT
      LAYER M4 ;
        RECT  0 16.992 0.084 17.016 ;
    END
  END captured[39]
  PIN captured[3]
    DIRECTION INPUT ;
    USE SIGNAL ;
    PORT
      LAYER M4 ;
        RECT  0 3.792 0.084 3.816 ;
    END
  END captured[3]
  PIN captured[40]
    DIRECTION INPUT ;
    USE SIGNAL ;
    PORT
      LAYER M4 ;
        RECT  0 17.328 0.084 17.352 ;
    END
  END captured[40]
  PIN captured[41]
    DIRECTION INPUT ;
    USE SIGNAL ;
    PORT
      LAYER M4 ;
        RECT  0 17.712 0.084 17.736 ;
    END
  END captured[41]
  PIN captured[42]
    DIRECTION INPUT ;
    USE SIGNAL ;
    PORT
      LAYER M4 ;
        RECT  0 18.096 0.084 18.12 ;
    END
  END captured[42]
  PIN captured[43]
    DIRECTION INPUT ;
    USE SIGNAL ;
    PORT
      LAYER M4 ;
        RECT  0 18.432 0.084 18.456 ;
    END
  END captured[43]
  PIN captured[44]
    DIRECTION INPUT ;
    USE SIGNAL ;
    PORT
      LAYER M4 ;
        RECT  0 18.816 0.084 18.84 ;
    END
  END captured[44]
  PIN captured[45]
    DIRECTION INPUT ;
    USE SIGNAL ;
    PORT
      LAYER M4 ;
        RECT  0 19.152 0.084 19.176 ;
    END
  END captured[45]
  PIN captured[46]
    DIRECTION INPUT ;
    USE SIGNAL ;
    PORT
      LAYER M4 ;
        RECT  0 19.536 0.084 19.56 ;
    END
  END captured[46]
  PIN captured[47]
    DIRECTION INPUT ;
    USE SIGNAL ;
    PORT
      LAYER M4 ;
        RECT  0 19.92 0.084 19.944 ;
    END
  END captured[47]
  PIN captured[48]
    DIRECTION INPUT ;
    USE SIGNAL ;
    PORT
      LAYER M4 ;
        RECT  0 20.256 0.084 20.28 ;
    END
  END captured[48]
  PIN captured[49]
    DIRECTION INPUT ;
    USE SIGNAL ;
    PORT
      LAYER M4 ;
        RECT  0 20.64 0.084 20.664 ;
    END
  END captured[49]
  PIN captured[4]
    DIRECTION INPUT ;
    USE SIGNAL ;
    PORT
      LAYER M4 ;
        RECT  0 4.128 0.084 4.152 ;
    END
  END captured[4]
  PIN captured[50]
    DIRECTION INPUT ;
    USE SIGNAL ;
    PORT
      LAYER M4 ;
        RECT  0 21.024 0.084 21.048 ;
    END
  END captured[50]
  PIN captured[51]
    DIRECTION INPUT ;
    USE SIGNAL ;
    PORT
      LAYER M4 ;
        RECT  0 21.36 0.084 21.384 ;
    END
  END captured[51]
  PIN captured[52]
    DIRECTION INPUT ;
    USE SIGNAL ;
    PORT
      LAYER M4 ;
        RECT  0 21.744 0.084 21.768 ;
    END
  END captured[52]
  PIN captured[53]
    DIRECTION INPUT ;
    USE SIGNAL ;
    PORT
      LAYER M4 ;
        RECT  0 22.128 0.084 22.152 ;
    END
  END captured[53]
  PIN captured[54]
    DIRECTION INPUT ;
    USE SIGNAL ;
    PORT
      LAYER M4 ;
        RECT  0 22.464 0.084 22.488 ;
    END
  END captured[54]
  PIN captured[55]
    DIRECTION INPUT ;
    USE SIGNAL ;
    PORT
      LAYER M4 ;
        RECT  0 22.848 0.084 22.872 ;
    END
  END captured[55]
  PIN captured[56]
    DIRECTION INPUT ;
    USE SIGNAL ;
    PORT
      LAYER M4 ;
        RECT  0 23.184 0.084 23.208 ;
    END
  END captured[56]
  PIN captured[57]
    DIRECTION INPUT ;
    USE SIGNAL ;
    PORT
      LAYER M4 ;
        RECT  0 23.568 0.084 23.592 ;
    END
  END captured[57]
  PIN captured[58]
    DIRECTION INPUT ;
    USE SIGNAL ;
    PORT
      LAYER M4 ;
        RECT  0 23.952 0.084 23.976 ;
    END
  END captured[58]
  PIN captured[59]
    DIRECTION INPUT ;
    USE SIGNAL ;
    PORT
      LAYER M4 ;
        RECT  0 24.288 0.084 24.312 ;
    END
  END captured[59]
  PIN captured[5]
    DIRECTION INPUT ;
    USE SIGNAL ;
    PORT
      LAYER M4 ;
        RECT  0 4.512 0.084 4.536 ;
    END
  END captured[5]
  PIN captured[60]
    DIRECTION INPUT ;
    USE SIGNAL ;
    PORT
      LAYER M4 ;
        RECT  0 24.672 0.084 24.696 ;
    END
  END captured[60]
  PIN captured[61]
    DIRECTION INPUT ;
    USE SIGNAL ;
    PORT
      LAYER M4 ;
        RECT  0 25.056 0.084 25.08 ;
    END
  END captured[61]
  PIN captured[62]
    DIRECTION INPUT ;
    USE SIGNAL ;
    PORT
      LAYER M4 ;
        RECT  0 25.392 0.084 25.416 ;
    END
  END captured[62]
  PIN captured[63]
    DIRECTION INPUT ;
    USE SIGNAL ;
    PORT
      LAYER M4 ;
        RECT  0 25.776 0.084 25.8 ;
    END
  END captured[63]
  PIN captured[64]
    DIRECTION INPUT ;
    USE SIGNAL ;
    PORT
      LAYER M4 ;
        RECT  0 26.16 0.084 26.184 ;
    END
  END captured[64]
  PIN captured[65]
    DIRECTION INPUT ;
    USE SIGNAL ;
    PORT
      LAYER M4 ;
        RECT  0 26.496 0.084 26.52 ;
    END
  END captured[65]
  PIN captured[66]
    DIRECTION INPUT ;
    USE SIGNAL ;
    PORT
      LAYER M4 ;
        RECT  0 26.88 0.084 26.904 ;
    END
  END captured[66]
  PIN captured[67]
    DIRECTION INPUT ;
    USE SIGNAL ;
    PORT
      LAYER M4 ;
        RECT  0 27.216 0.084 27.24 ;
    END
  END captured[67]
  PIN captured[68]
    DIRECTION INPUT ;
    USE SIGNAL ;
    PORT
      LAYER M4 ;
        RECT  0 27.6 0.084 27.624 ;
    END
  END captured[68]
  PIN captured[69]
    DIRECTION INPUT ;
    USE SIGNAL ;
    PORT
      LAYER M4 ;
        RECT  0 27.984 0.084 28.008 ;
    END
  END captured[69]
  PIN captured[6]
    DIRECTION INPUT ;
    USE SIGNAL ;
    PORT
      LAYER M4 ;
        RECT  0 4.848 0.084 4.872 ;
    END
  END captured[6]
  PIN captured[70]
    DIRECTION INPUT ;
    USE SIGNAL ;
    PORT
      LAYER M4 ;
        RECT  0 28.32 0.084 28.344 ;
    END
  END captured[70]
  PIN captured[71]
    DIRECTION INPUT ;
    USE SIGNAL ;
    PORT
      LAYER M4 ;
        RECT  0 28.704 0.084 28.728 ;
    END
  END captured[71]
  PIN captured[72]
    DIRECTION INPUT ;
    USE SIGNAL ;
    PORT
      LAYER M4 ;
        RECT  0 29.088 0.084 29.112 ;
    END
  END captured[72]
  PIN captured[73]
    DIRECTION INPUT ;
    USE SIGNAL ;
    PORT
      LAYER M4 ;
        RECT  0 29.424 0.084 29.448 ;
    END
  END captured[73]
  PIN captured[74]
    DIRECTION INPUT ;
    USE SIGNAL ;
    PORT
      LAYER M4 ;
        RECT  0 29.808 0.084 29.832 ;
    END
  END captured[74]
  PIN captured[75]
    DIRECTION INPUT ;
    USE SIGNAL ;
    PORT
      LAYER M4 ;
        RECT  0 30.192 0.084 30.216 ;
    END
  END captured[75]
  PIN captured[76]
    DIRECTION INPUT ;
    USE SIGNAL ;
    PORT
      LAYER M4 ;
        RECT  0 30.528 0.084 30.552 ;
    END
  END captured[76]
  PIN captured[77]
    DIRECTION INPUT ;
    USE SIGNAL ;
    PORT
      LAYER M4 ;
        RECT  0 30.912 0.084 30.936 ;
    END
  END captured[77]
  PIN captured[78]
    DIRECTION INPUT ;
    USE SIGNAL ;
    PORT
      LAYER M4 ;
        RECT  0 31.296 0.084 31.32 ;
    END
  END captured[78]
  PIN captured[79]
    DIRECTION INPUT ;
    USE SIGNAL ;
    PORT
      LAYER M4 ;
        RECT  0 31.632 0.084 31.656 ;
    END
  END captured[79]
  PIN captured[7]
    DIRECTION INPUT ;
    USE SIGNAL ;
    PORT
      LAYER M4 ;
        RECT  0 5.232 0.084 5.256 ;
    END
  END captured[7]
  PIN captured[80]
    DIRECTION INPUT ;
    USE SIGNAL ;
    PORT
      LAYER M4 ;
        RECT  0 32.016 0.084 32.04 ;
    END
  END captured[80]
  PIN captured[81]
    DIRECTION INPUT ;
    USE SIGNAL ;
    PORT
      LAYER M4 ;
        RECT  0 32.352 0.084 32.376 ;
    END
  END captured[81]
  PIN captured[82]
    DIRECTION INPUT ;
    USE SIGNAL ;
    PORT
      LAYER M4 ;
        RECT  0 32.736 0.084 32.76 ;
    END
  END captured[82]
  PIN captured[83]
    DIRECTION INPUT ;
    USE SIGNAL ;
    PORT
      LAYER M4 ;
        RECT  0 33.12 0.084 33.144 ;
    END
  END captured[83]
  PIN captured[84]
    DIRECTION INPUT ;
    USE SIGNAL ;
    PORT
      LAYER M4 ;
        RECT  0 33.456 0.084 33.48 ;
    END
  END captured[84]
  PIN captured[85]
    DIRECTION INPUT ;
    USE SIGNAL ;
    PORT
      LAYER M4 ;
        RECT  0 33.84 0.084 33.864 ;
    END
  END captured[85]
  PIN captured[86]
    DIRECTION INPUT ;
    USE SIGNAL ;
    PORT
      LAYER M4 ;
        RECT  0 34.224 0.084 34.248 ;
    END
  END captured[86]
  PIN captured[87]
    DIRECTION INPUT ;
    USE SIGNAL ;
    PORT
      LAYER M4 ;
        RECT  0 34.56 0.084 34.584 ;
    END
  END captured[87]
  PIN captured[88]
    DIRECTION INPUT ;
    USE SIGNAL ;
    PORT
      LAYER M4 ;
        RECT  0 34.944 0.084 34.968 ;
    END
  END captured[88]
  PIN captured[89]
    DIRECTION INPUT ;
    USE SIGNAL ;
    PORT
      LAYER M4 ;
        RECT  0 35.328 0.084 35.352 ;
    END
  END captured[89]
  PIN captured[8]
    DIRECTION INPUT ;
    USE SIGNAL ;
    PORT
      LAYER M4 ;
        RECT  0 5.616 0.084 5.64 ;
    END
  END captured[8]
  PIN captured[90]
    DIRECTION INPUT ;
    USE SIGNAL ;
    PORT
      LAYER M4 ;
        RECT  0 35.664 0.084 35.688 ;
    END
  END captured[90]
  PIN captured[91]
    DIRECTION INPUT ;
    USE SIGNAL ;
    PORT
      LAYER M4 ;
        RECT  0 36.048 0.084 36.072 ;
    END
  END captured[91]
  PIN captured[92]
    DIRECTION INPUT ;
    USE SIGNAL ;
    PORT
      LAYER M4 ;
        RECT  0 36.384 0.084 36.408 ;
    END
  END captured[92]
  PIN captured[93]
    DIRECTION INPUT ;
    USE SIGNAL ;
    PORT
      LAYER M4 ;
        RECT  0 36.768 0.084 36.792 ;
    END
  END captured[93]
  PIN captured[94]
    DIRECTION INPUT ;
    USE SIGNAL ;
    PORT
      LAYER M4 ;
        RECT  0 37.152 0.084 37.176 ;
    END
  END captured[94]
  PIN captured[95]
    DIRECTION INPUT ;
    USE SIGNAL ;
    PORT
      LAYER M4 ;
        RECT  0 37.488 0.084 37.512 ;
    END
  END captured[95]
  PIN captured[96]
    DIRECTION INPUT ;
    USE SIGNAL ;
    PORT
      LAYER M4 ;
        RECT  0 37.872 0.084 37.896 ;
    END
  END captured[96]
  PIN captured[97]
    DIRECTION INPUT ;
    USE SIGNAL ;
    PORT
      LAYER M4 ;
        RECT  0 38.256 0.084 38.28 ;
    END
  END captured[97]
  PIN captured[98]
    DIRECTION INPUT ;
    USE SIGNAL ;
    PORT
      LAYER M4 ;
        RECT  0 38.592 0.084 38.616 ;
    END
  END captured[98]
  PIN captured[99]
    DIRECTION INPUT ;
    USE SIGNAL ;
    PORT
      LAYER M4 ;
        RECT  0 38.976 0.084 39 ;
    END
  END captured[99]
  PIN captured[9]
    DIRECTION INPUT ;
    USE SIGNAL ;
    PORT
      LAYER M4 ;
        RECT  0 5.952 0.084 5.976 ;
    END
  END captured[9]
  PIN captured_slot[0]
    DIRECTION INPUT ;
    USE SIGNAL ;
    PORT
      LAYER M4 ;
        RECT  0 96.72 0.084 96.744 ;
    END
  END captured_slot[0]
  PIN captured_slot[1]
    DIRECTION INPUT ;
    USE SIGNAL ;
    PORT
      LAYER M4 ;
        RECT  0 96.96 0.084 96.984 ;
    END
  END captured_slot[1]
  PIN captured_slot[2]
    DIRECTION INPUT ;
    USE SIGNAL ;
    PORT
      LAYER M4 ;
        RECT  0 97.248 0.084 97.272 ;
    END
  END captured_slot[2]
  PIN captured_slot[3]
    DIRECTION INPUT ;
    USE SIGNAL ;
    PORT
      LAYER M4 ;
        RECT  0 97.536 0.084 97.56 ;
    END
  END captured_slot[3]
  PIN captured_slot[4]
    DIRECTION INPUT ;
    USE SIGNAL ;
    PORT
      LAYER M4 ;
        RECT  0 97.824 0.084 97.848 ;
    END
  END captured_slot[4]
  PIN captured_slot[5]
    DIRECTION INPUT ;
    USE SIGNAL ;
    PORT
      LAYER M4 ;
        RECT  0 98.112 0.084 98.136 ;
    END
  END captured_slot[5]
  PIN captured_slot[6]
    DIRECTION INPUT ;
    USE SIGNAL ;
    PORT
      LAYER M4 ;
        RECT  0 98.4 0.084 98.424 ;
    END
  END captured_slot[6]
  PIN captured_slot[7]
    DIRECTION INPUT ;
    USE SIGNAL ;
    PORT
      LAYER M4 ;
        RECT  0 98.688 0.084 98.712 ;
    END
  END captured_slot[7]
  PIN clk
    DIRECTION INPUT ;
    USE SIGNAL ;
    PORT
      LAYER M5 ;
        RECT  21.792 101.436 21.816 101.52 ;
    END
  END clk
  PIN dst_d[0]
    DIRECTION OUTPUT ;
    USE SIGNAL ;
    PORT
      LAYER M4 ;
        RECT  23.676 2.592 23.76 2.616 ;
    END
  END dst_d[0]
  PIN dst_d[100]
    DIRECTION OUTPUT ;
    USE SIGNAL ;
    PORT
      LAYER M4 ;
        RECT  23.676 23.232 23.76 23.256 ;
    END
  END dst_d[100]
  PIN dst_d[101]
    DIRECTION OUTPUT ;
    USE SIGNAL ;
    PORT
      LAYER M4 ;
        RECT  23.676 23.424 23.76 23.448 ;
    END
  END dst_d[101]
  PIN dst_d[102]
    DIRECTION OUTPUT ;
    USE SIGNAL ;
    PORT
      LAYER M4 ;
        RECT  23.676 23.616 23.76 23.64 ;
    END
  END dst_d[102]
  PIN dst_d[103]
    DIRECTION OUTPUT ;
    USE SIGNAL ;
    PORT
      LAYER M4 ;
        RECT  23.676 23.808 23.76 23.832 ;
    END
  END dst_d[103]
  PIN dst_d[104]
    DIRECTION OUTPUT ;
    USE SIGNAL ;
    PORT
      LAYER M4 ;
        RECT  23.676 24.048 23.76 24.072 ;
    END
  END dst_d[104]
  PIN dst_d[105]
    DIRECTION OUTPUT ;
    USE SIGNAL ;
    PORT
      LAYER M4 ;
        RECT  23.676 24.24 23.76 24.264 ;
    END
  END dst_d[105]
  PIN dst_d[106]
    DIRECTION OUTPUT ;
    USE SIGNAL ;
    PORT
      LAYER M4 ;
        RECT  23.676 24.432 23.76 24.456 ;
    END
  END dst_d[106]
  PIN dst_d[107]
    DIRECTION OUTPUT ;
    USE SIGNAL ;
    PORT
      LAYER M4 ;
        RECT  23.676 24.672 23.76 24.696 ;
    END
  END dst_d[107]
  PIN dst_d[108]
    DIRECTION OUTPUT ;
    USE SIGNAL ;
    PORT
      LAYER M4 ;
        RECT  23.676 24.864 23.76 24.888 ;
    END
  END dst_d[108]
  PIN dst_d[109]
    DIRECTION OUTPUT ;
    USE SIGNAL ;
    PORT
      LAYER M4 ;
        RECT  23.676 25.056 23.76 25.08 ;
    END
  END dst_d[109]
  PIN dst_d[10]
    DIRECTION OUTPUT ;
    USE SIGNAL ;
    PORT
      LAYER M4 ;
        RECT  23.676 4.656 23.76 4.68 ;
    END
  END dst_d[10]
  PIN dst_d[110]
    DIRECTION OUTPUT ;
    USE SIGNAL ;
    PORT
      LAYER M4 ;
        RECT  23.676 25.248 23.76 25.272 ;
    END
  END dst_d[110]
  PIN dst_d[111]
    DIRECTION OUTPUT ;
    USE SIGNAL ;
    PORT
      LAYER M4 ;
        RECT  23.676 25.488 23.76 25.512 ;
    END
  END dst_d[111]
  PIN dst_d[112]
    DIRECTION OUTPUT ;
    USE SIGNAL ;
    PORT
      LAYER M4 ;
        RECT  23.676 25.68 23.76 25.704 ;
    END
  END dst_d[112]
  PIN dst_d[113]
    DIRECTION OUTPUT ;
    USE SIGNAL ;
    PORT
      LAYER M4 ;
        RECT  23.676 25.872 23.76 25.896 ;
    END
  END dst_d[113]
  PIN dst_d[114]
    DIRECTION OUTPUT ;
    USE SIGNAL ;
    PORT
      LAYER M4 ;
        RECT  23.676 26.112 23.76 26.136 ;
    END
  END dst_d[114]
  PIN dst_d[115]
    DIRECTION OUTPUT ;
    USE SIGNAL ;
    PORT
      LAYER M4 ;
        RECT  23.676 26.304 23.76 26.328 ;
    END
  END dst_d[115]
  PIN dst_d[116]
    DIRECTION OUTPUT ;
    USE SIGNAL ;
    PORT
      LAYER M4 ;
        RECT  23.676 26.496 23.76 26.52 ;
    END
  END dst_d[116]
  PIN dst_d[117]
    DIRECTION OUTPUT ;
    USE SIGNAL ;
    PORT
      LAYER M4 ;
        RECT  23.676 26.736 23.76 26.76 ;
    END
  END dst_d[117]
  PIN dst_d[118]
    DIRECTION OUTPUT ;
    USE SIGNAL ;
    PORT
      LAYER M4 ;
        RECT  23.676 26.928 23.76 26.952 ;
    END
  END dst_d[118]
  PIN dst_d[119]
    DIRECTION OUTPUT ;
    USE SIGNAL ;
    PORT
      LAYER M4 ;
        RECT  23.676 27.12 23.76 27.144 ;
    END
  END dst_d[119]
  PIN dst_d[11]
    DIRECTION OUTPUT ;
    USE SIGNAL ;
    PORT
      LAYER M4 ;
        RECT  23.676 4.848 23.76 4.872 ;
    END
  END dst_d[11]
  PIN dst_d[120]
    DIRECTION OUTPUT ;
    USE SIGNAL ;
    PORT
      LAYER M4 ;
        RECT  23.676 27.312 23.76 27.336 ;
    END
  END dst_d[120]
  PIN dst_d[121]
    DIRECTION OUTPUT ;
    USE SIGNAL ;
    PORT
      LAYER M4 ;
        RECT  23.676 27.552 23.76 27.576 ;
    END
  END dst_d[121]
  PIN dst_d[122]
    DIRECTION OUTPUT ;
    USE SIGNAL ;
    PORT
      LAYER M4 ;
        RECT  23.676 27.744 23.76 27.768 ;
    END
  END dst_d[122]
  PIN dst_d[123]
    DIRECTION OUTPUT ;
    USE SIGNAL ;
    PORT
      LAYER M4 ;
        RECT  23.676 27.936 23.76 27.96 ;
    END
  END dst_d[123]
  PIN dst_d[124]
    DIRECTION OUTPUT ;
    USE SIGNAL ;
    PORT
      LAYER M4 ;
        RECT  23.676 28.176 23.76 28.2 ;
    END
  END dst_d[124]
  PIN dst_d[125]
    DIRECTION OUTPUT ;
    USE SIGNAL ;
    PORT
      LAYER M4 ;
        RECT  23.676 28.368 23.76 28.392 ;
    END
  END dst_d[125]
  PIN dst_d[126]
    DIRECTION OUTPUT ;
    USE SIGNAL ;
    PORT
      LAYER M4 ;
        RECT  23.676 28.56 23.76 28.584 ;
    END
  END dst_d[126]
  PIN dst_d[127]
    DIRECTION OUTPUT ;
    USE SIGNAL ;
    PORT
      LAYER M4 ;
        RECT  23.676 28.8 23.76 28.824 ;
    END
  END dst_d[127]
  PIN dst_d[128]
    DIRECTION OUTPUT ;
    USE SIGNAL ;
    PORT
      LAYER M4 ;
        RECT  23.676 28.992 23.76 29.016 ;
    END
  END dst_d[128]
  PIN dst_d[129]
    DIRECTION OUTPUT ;
    USE SIGNAL ;
    PORT
      LAYER M4 ;
        RECT  23.676 29.184 23.76 29.208 ;
    END
  END dst_d[129]
  PIN dst_d[12]
    DIRECTION OUTPUT ;
    USE SIGNAL ;
    PORT
      LAYER M4 ;
        RECT  23.676 5.088 23.76 5.112 ;
    END
  END dst_d[12]
  PIN dst_d[130]
    DIRECTION OUTPUT ;
    USE SIGNAL ;
    PORT
      LAYER M4 ;
        RECT  23.676 29.376 23.76 29.4 ;
    END
  END dst_d[130]
  PIN dst_d[131]
    DIRECTION OUTPUT ;
    USE SIGNAL ;
    PORT
      LAYER M4 ;
        RECT  23.676 29.616 23.76 29.64 ;
    END
  END dst_d[131]
  PIN dst_d[132]
    DIRECTION OUTPUT ;
    USE SIGNAL ;
    PORT
      LAYER M4 ;
        RECT  23.676 29.808 23.76 29.832 ;
    END
  END dst_d[132]
  PIN dst_d[133]
    DIRECTION OUTPUT ;
    USE SIGNAL ;
    PORT
      LAYER M4 ;
        RECT  23.676 30 23.76 30.024 ;
    END
  END dst_d[133]
  PIN dst_d[134]
    DIRECTION OUTPUT ;
    USE SIGNAL ;
    PORT
      LAYER M4 ;
        RECT  23.676 30.24 23.76 30.264 ;
    END
  END dst_d[134]
  PIN dst_d[135]
    DIRECTION OUTPUT ;
    USE SIGNAL ;
    PORT
      LAYER M4 ;
        RECT  23.676 30.432 23.76 30.456 ;
    END
  END dst_d[135]
  PIN dst_d[136]
    DIRECTION OUTPUT ;
    USE SIGNAL ;
    PORT
      LAYER M4 ;
        RECT  23.676 30.624 23.76 30.648 ;
    END
  END dst_d[136]
  PIN dst_d[137]
    DIRECTION OUTPUT ;
    USE SIGNAL ;
    PORT
      LAYER M4 ;
        RECT  23.676 30.816 23.76 30.84 ;
    END
  END dst_d[137]
  PIN dst_d[138]
    DIRECTION OUTPUT ;
    USE SIGNAL ;
    PORT
      LAYER M4 ;
        RECT  23.676 31.056 23.76 31.08 ;
    END
  END dst_d[138]
  PIN dst_d[139]
    DIRECTION OUTPUT ;
    USE SIGNAL ;
    PORT
      LAYER M4 ;
        RECT  23.676 31.248 23.76 31.272 ;
    END
  END dst_d[139]
  PIN dst_d[13]
    DIRECTION OUTPUT ;
    USE SIGNAL ;
    PORT
      LAYER M4 ;
        RECT  23.676 5.28 23.76 5.304 ;
    END
  END dst_d[13]
  PIN dst_d[140]
    DIRECTION OUTPUT ;
    USE SIGNAL ;
    PORT
      LAYER M4 ;
        RECT  23.676 31.44 23.76 31.464 ;
    END
  END dst_d[140]
  PIN dst_d[141]
    DIRECTION OUTPUT ;
    USE SIGNAL ;
    PORT
      LAYER M4 ;
        RECT  23.676 31.68 23.76 31.704 ;
    END
  END dst_d[141]
  PIN dst_d[142]
    DIRECTION OUTPUT ;
    USE SIGNAL ;
    PORT
      LAYER M4 ;
        RECT  23.676 31.872 23.76 31.896 ;
    END
  END dst_d[142]
  PIN dst_d[143]
    DIRECTION OUTPUT ;
    USE SIGNAL ;
    PORT
      LAYER M4 ;
        RECT  23.676 32.064 23.76 32.088 ;
    END
  END dst_d[143]
  PIN dst_d[144]
    DIRECTION OUTPUT ;
    USE SIGNAL ;
    PORT
      LAYER M4 ;
        RECT  23.676 32.304 23.76 32.328 ;
    END
  END dst_d[144]
  PIN dst_d[145]
    DIRECTION OUTPUT ;
    USE SIGNAL ;
    PORT
      LAYER M4 ;
        RECT  23.676 32.496 23.76 32.52 ;
    END
  END dst_d[145]
  PIN dst_d[146]
    DIRECTION OUTPUT ;
    USE SIGNAL ;
    PORT
      LAYER M4 ;
        RECT  23.676 32.688 23.76 32.712 ;
    END
  END dst_d[146]
  PIN dst_d[147]
    DIRECTION OUTPUT ;
    USE SIGNAL ;
    PORT
      LAYER M4 ;
        RECT  23.676 32.88 23.76 32.904 ;
    END
  END dst_d[147]
  PIN dst_d[148]
    DIRECTION OUTPUT ;
    USE SIGNAL ;
    PORT
      LAYER M4 ;
        RECT  23.676 33.12 23.76 33.144 ;
    END
  END dst_d[148]
  PIN dst_d[149]
    DIRECTION OUTPUT ;
    USE SIGNAL ;
    PORT
      LAYER M4 ;
        RECT  23.676 33.312 23.76 33.336 ;
    END
  END dst_d[149]
  PIN dst_d[14]
    DIRECTION OUTPUT ;
    USE SIGNAL ;
    PORT
      LAYER M4 ;
        RECT  23.676 5.472 23.76 5.496 ;
    END
  END dst_d[14]
  PIN dst_d[150]
    DIRECTION OUTPUT ;
    USE SIGNAL ;
    PORT
      LAYER M4 ;
        RECT  23.676 33.504 23.76 33.528 ;
    END
  END dst_d[150]
  PIN dst_d[151]
    DIRECTION OUTPUT ;
    USE SIGNAL ;
    PORT
      LAYER M4 ;
        RECT  23.676 33.744 23.76 33.768 ;
    END
  END dst_d[151]
  PIN dst_d[152]
    DIRECTION OUTPUT ;
    USE SIGNAL ;
    PORT
      LAYER M4 ;
        RECT  23.676 33.936 23.76 33.96 ;
    END
  END dst_d[152]
  PIN dst_d[153]
    DIRECTION OUTPUT ;
    USE SIGNAL ;
    PORT
      LAYER M4 ;
        RECT  23.676 34.128 23.76 34.152 ;
    END
  END dst_d[153]
  PIN dst_d[154]
    DIRECTION OUTPUT ;
    USE SIGNAL ;
    PORT
      LAYER M4 ;
        RECT  23.676 34.32 23.76 34.344 ;
    END
  END dst_d[154]
  PIN dst_d[155]
    DIRECTION OUTPUT ;
    USE SIGNAL ;
    PORT
      LAYER M4 ;
        RECT  23.676 34.56 23.76 34.584 ;
    END
  END dst_d[155]
  PIN dst_d[156]
    DIRECTION OUTPUT ;
    USE SIGNAL ;
    PORT
      LAYER M4 ;
        RECT  23.676 34.752 23.76 34.776 ;
    END
  END dst_d[156]
  PIN dst_d[157]
    DIRECTION OUTPUT ;
    USE SIGNAL ;
    PORT
      LAYER M4 ;
        RECT  23.676 34.944 23.76 34.968 ;
    END
  END dst_d[157]
  PIN dst_d[158]
    DIRECTION OUTPUT ;
    USE SIGNAL ;
    PORT
      LAYER M4 ;
        RECT  23.676 35.184 23.76 35.208 ;
    END
  END dst_d[158]
  PIN dst_d[159]
    DIRECTION OUTPUT ;
    USE SIGNAL ;
    PORT
      LAYER M4 ;
        RECT  23.676 35.376 23.76 35.4 ;
    END
  END dst_d[159]
  PIN dst_d[15]
    DIRECTION OUTPUT ;
    USE SIGNAL ;
    PORT
      LAYER M4 ;
        RECT  23.676 5.664 23.76 5.688 ;
    END
  END dst_d[15]
  PIN dst_d[160]
    DIRECTION OUTPUT ;
    USE SIGNAL ;
    PORT
      LAYER M4 ;
        RECT  23.676 35.568 23.76 35.592 ;
    END
  END dst_d[160]
  PIN dst_d[161]
    DIRECTION OUTPUT ;
    USE SIGNAL ;
    PORT
      LAYER M4 ;
        RECT  23.676 35.808 23.76 35.832 ;
    END
  END dst_d[161]
  PIN dst_d[162]
    DIRECTION OUTPUT ;
    USE SIGNAL ;
    PORT
      LAYER M4 ;
        RECT  23.676 36 23.76 36.024 ;
    END
  END dst_d[162]
  PIN dst_d[163]
    DIRECTION OUTPUT ;
    USE SIGNAL ;
    PORT
      LAYER M4 ;
        RECT  23.676 36.192 23.76 36.216 ;
    END
  END dst_d[163]
  PIN dst_d[164]
    DIRECTION OUTPUT ;
    USE SIGNAL ;
    PORT
      LAYER M4 ;
        RECT  23.676 36.384 23.76 36.408 ;
    END
  END dst_d[164]
  PIN dst_d[165]
    DIRECTION OUTPUT ;
    USE SIGNAL ;
    PORT
      LAYER M4 ;
        RECT  23.676 36.624 23.76 36.648 ;
    END
  END dst_d[165]
  PIN dst_d[166]
    DIRECTION OUTPUT ;
    USE SIGNAL ;
    PORT
      LAYER M4 ;
        RECT  23.676 36.816 23.76 36.84 ;
    END
  END dst_d[166]
  PIN dst_d[167]
    DIRECTION OUTPUT ;
    USE SIGNAL ;
    PORT
      LAYER M4 ;
        RECT  23.676 37.008 23.76 37.032 ;
    END
  END dst_d[167]
  PIN dst_d[168]
    DIRECTION OUTPUT ;
    USE SIGNAL ;
    PORT
      LAYER M4 ;
        RECT  23.676 37.248 23.76 37.272 ;
    END
  END dst_d[168]
  PIN dst_d[169]
    DIRECTION OUTPUT ;
    USE SIGNAL ;
    PORT
      LAYER M4 ;
        RECT  23.676 37.44 23.76 37.464 ;
    END
  END dst_d[169]
  PIN dst_d[16]
    DIRECTION OUTPUT ;
    USE SIGNAL ;
    PORT
      LAYER M4 ;
        RECT  23.676 5.904 23.76 5.928 ;
    END
  END dst_d[16]
  PIN dst_d[170]
    DIRECTION OUTPUT ;
    USE SIGNAL ;
    PORT
      LAYER M4 ;
        RECT  23.676 37.632 23.76 37.656 ;
    END
  END dst_d[170]
  PIN dst_d[171]
    DIRECTION OUTPUT ;
    USE SIGNAL ;
    PORT
      LAYER M4 ;
        RECT  23.676 37.872 23.76 37.896 ;
    END
  END dst_d[171]
  PIN dst_d[172]
    DIRECTION OUTPUT ;
    USE SIGNAL ;
    PORT
      LAYER M4 ;
        RECT  23.676 38.064 23.76 38.088 ;
    END
  END dst_d[172]
  PIN dst_d[173]
    DIRECTION OUTPUT ;
    USE SIGNAL ;
    PORT
      LAYER M4 ;
        RECT  23.676 38.256 23.76 38.28 ;
    END
  END dst_d[173]
  PIN dst_d[174]
    DIRECTION OUTPUT ;
    USE SIGNAL ;
    PORT
      LAYER M4 ;
        RECT  23.676 38.448 23.76 38.472 ;
    END
  END dst_d[174]
  PIN dst_d[175]
    DIRECTION OUTPUT ;
    USE SIGNAL ;
    PORT
      LAYER M4 ;
        RECT  23.676 38.688 23.76 38.712 ;
    END
  END dst_d[175]
  PIN dst_d[176]
    DIRECTION OUTPUT ;
    USE SIGNAL ;
    PORT
      LAYER M4 ;
        RECT  23.676 38.88 23.76 38.904 ;
    END
  END dst_d[176]
  PIN dst_d[177]
    DIRECTION OUTPUT ;
    USE SIGNAL ;
    PORT
      LAYER M4 ;
        RECT  23.676 39.072 23.76 39.096 ;
    END
  END dst_d[177]
  PIN dst_d[178]
    DIRECTION OUTPUT ;
    USE SIGNAL ;
    PORT
      LAYER M4 ;
        RECT  23.676 39.312 23.76 39.336 ;
    END
  END dst_d[178]
  PIN dst_d[179]
    DIRECTION OUTPUT ;
    USE SIGNAL ;
    PORT
      LAYER M4 ;
        RECT  23.676 39.504 23.76 39.528 ;
    END
  END dst_d[179]
  PIN dst_d[17]
    DIRECTION OUTPUT ;
    USE SIGNAL ;
    PORT
      LAYER M4 ;
        RECT  23.676 6.096 23.76 6.12 ;
    END
  END dst_d[17]
  PIN dst_d[180]
    DIRECTION OUTPUT ;
    USE SIGNAL ;
    PORT
      LAYER M4 ;
        RECT  23.676 39.696 23.76 39.72 ;
    END
  END dst_d[180]
  PIN dst_d[181]
    DIRECTION OUTPUT ;
    USE SIGNAL ;
    PORT
      LAYER M4 ;
        RECT  23.676 39.888 23.76 39.912 ;
    END
  END dst_d[181]
  PIN dst_d[182]
    DIRECTION OUTPUT ;
    USE SIGNAL ;
    PORT
      LAYER M4 ;
        RECT  23.676 40.128 23.76 40.152 ;
    END
  END dst_d[182]
  PIN dst_d[183]
    DIRECTION OUTPUT ;
    USE SIGNAL ;
    PORT
      LAYER M4 ;
        RECT  23.676 40.32 23.76 40.344 ;
    END
  END dst_d[183]
  PIN dst_d[184]
    DIRECTION OUTPUT ;
    USE SIGNAL ;
    PORT
      LAYER M4 ;
        RECT  23.676 40.512 23.76 40.536 ;
    END
  END dst_d[184]
  PIN dst_d[185]
    DIRECTION OUTPUT ;
    USE SIGNAL ;
    PORT
      LAYER M4 ;
        RECT  23.676 40.752 23.76 40.776 ;
    END
  END dst_d[185]
  PIN dst_d[186]
    DIRECTION OUTPUT ;
    USE SIGNAL ;
    PORT
      LAYER M4 ;
        RECT  23.676 40.944 23.76 40.968 ;
    END
  END dst_d[186]
  PIN dst_d[187]
    DIRECTION OUTPUT ;
    USE SIGNAL ;
    PORT
      LAYER M4 ;
        RECT  23.676 41.136 23.76 41.16 ;
    END
  END dst_d[187]
  PIN dst_d[188]
    DIRECTION OUTPUT ;
    USE SIGNAL ;
    PORT
      LAYER M4 ;
        RECT  23.676 41.376 23.76 41.4 ;
    END
  END dst_d[188]
  PIN dst_d[189]
    DIRECTION OUTPUT ;
    USE SIGNAL ;
    PORT
      LAYER M4 ;
        RECT  23.676 41.568 23.76 41.592 ;
    END
  END dst_d[189]
  PIN dst_d[18]
    DIRECTION OUTPUT ;
    USE SIGNAL ;
    PORT
      LAYER M4 ;
        RECT  23.676 6.288 23.76 6.312 ;
    END
  END dst_d[18]
  PIN dst_d[190]
    DIRECTION OUTPUT ;
    USE SIGNAL ;
    PORT
      LAYER M4 ;
        RECT  23.676 41.76 23.76 41.784 ;
    END
  END dst_d[190]
  PIN dst_d[191]
    DIRECTION OUTPUT ;
    USE SIGNAL ;
    PORT
      LAYER M4 ;
        RECT  23.676 41.952 23.76 41.976 ;
    END
  END dst_d[191]
  PIN dst_d[192]
    DIRECTION OUTPUT ;
    USE SIGNAL ;
    PORT
      LAYER M4 ;
        RECT  23.676 42.192 23.76 42.216 ;
    END
  END dst_d[192]
  PIN dst_d[193]
    DIRECTION OUTPUT ;
    USE SIGNAL ;
    PORT
      LAYER M4 ;
        RECT  23.676 42.384 23.76 42.408 ;
    END
  END dst_d[193]
  PIN dst_d[194]
    DIRECTION OUTPUT ;
    USE SIGNAL ;
    PORT
      LAYER M4 ;
        RECT  23.676 42.576 23.76 42.6 ;
    END
  END dst_d[194]
  PIN dst_d[195]
    DIRECTION OUTPUT ;
    USE SIGNAL ;
    PORT
      LAYER M4 ;
        RECT  23.676 42.816 23.76 42.84 ;
    END
  END dst_d[195]
  PIN dst_d[196]
    DIRECTION OUTPUT ;
    USE SIGNAL ;
    PORT
      LAYER M4 ;
        RECT  23.676 43.008 23.76 43.032 ;
    END
  END dst_d[196]
  PIN dst_d[197]
    DIRECTION OUTPUT ;
    USE SIGNAL ;
    PORT
      LAYER M4 ;
        RECT  23.676 43.2 23.76 43.224 ;
    END
  END dst_d[197]
  PIN dst_d[198]
    DIRECTION OUTPUT ;
    USE SIGNAL ;
    PORT
      LAYER M4 ;
        RECT  23.676 43.392 23.76 43.416 ;
    END
  END dst_d[198]
  PIN dst_d[199]
    DIRECTION OUTPUT ;
    USE SIGNAL ;
    PORT
      LAYER M4 ;
        RECT  23.676 43.632 23.76 43.656 ;
    END
  END dst_d[199]
  PIN dst_d[19]
    DIRECTION OUTPUT ;
    USE SIGNAL ;
    PORT
      LAYER M4 ;
        RECT  23.676 6.528 23.76 6.552 ;
    END
  END dst_d[19]
  PIN dst_d[1]
    DIRECTION OUTPUT ;
    USE SIGNAL ;
    PORT
      LAYER M4 ;
        RECT  23.676 2.784 23.76 2.808 ;
    END
  END dst_d[1]
  PIN dst_d[200]
    DIRECTION OUTPUT ;
    USE SIGNAL ;
    PORT
      LAYER M4 ;
        RECT  23.676 43.824 23.76 43.848 ;
    END
  END dst_d[200]
  PIN dst_d[201]
    DIRECTION OUTPUT ;
    USE SIGNAL ;
    PORT
      LAYER M4 ;
        RECT  23.676 44.016 23.76 44.04 ;
    END
  END dst_d[201]
  PIN dst_d[202]
    DIRECTION OUTPUT ;
    USE SIGNAL ;
    PORT
      LAYER M4 ;
        RECT  23.676 44.256 23.76 44.28 ;
    END
  END dst_d[202]
  PIN dst_d[203]
    DIRECTION OUTPUT ;
    USE SIGNAL ;
    PORT
      LAYER M4 ;
        RECT  23.676 44.448 23.76 44.472 ;
    END
  END dst_d[203]
  PIN dst_d[204]
    DIRECTION OUTPUT ;
    USE SIGNAL ;
    PORT
      LAYER M4 ;
        RECT  23.676 44.64 23.76 44.664 ;
    END
  END dst_d[204]
  PIN dst_d[205]
    DIRECTION OUTPUT ;
    USE SIGNAL ;
    PORT
      LAYER M4 ;
        RECT  23.676 44.88 23.76 44.904 ;
    END
  END dst_d[205]
  PIN dst_d[206]
    DIRECTION OUTPUT ;
    USE SIGNAL ;
    PORT
      LAYER M4 ;
        RECT  23.676 45.072 23.76 45.096 ;
    END
  END dst_d[206]
  PIN dst_d[207]
    DIRECTION OUTPUT ;
    USE SIGNAL ;
    PORT
      LAYER M4 ;
        RECT  23.676 45.264 23.76 45.288 ;
    END
  END dst_d[207]
  PIN dst_d[208]
    DIRECTION OUTPUT ;
    USE SIGNAL ;
    PORT
      LAYER M4 ;
        RECT  23.676 45.456 23.76 45.48 ;
    END
  END dst_d[208]
  PIN dst_d[209]
    DIRECTION OUTPUT ;
    USE SIGNAL ;
    PORT
      LAYER M4 ;
        RECT  23.676 45.696 23.76 45.72 ;
    END
  END dst_d[209]
  PIN dst_d[20]
    DIRECTION OUTPUT ;
    USE SIGNAL ;
    PORT
      LAYER M4 ;
        RECT  23.676 6.72 23.76 6.744 ;
    END
  END dst_d[20]
  PIN dst_d[210]
    DIRECTION OUTPUT ;
    USE SIGNAL ;
    PORT
      LAYER M4 ;
        RECT  23.676 45.888 23.76 45.912 ;
    END
  END dst_d[210]
  PIN dst_d[211]
    DIRECTION OUTPUT ;
    USE SIGNAL ;
    PORT
      LAYER M4 ;
        RECT  23.676 46.08 23.76 46.104 ;
    END
  END dst_d[211]
  PIN dst_d[212]
    DIRECTION OUTPUT ;
    USE SIGNAL ;
    PORT
      LAYER M4 ;
        RECT  23.676 46.32 23.76 46.344 ;
    END
  END dst_d[212]
  PIN dst_d[213]
    DIRECTION OUTPUT ;
    USE SIGNAL ;
    PORT
      LAYER M4 ;
        RECT  23.676 46.512 23.76 46.536 ;
    END
  END dst_d[213]
  PIN dst_d[214]
    DIRECTION OUTPUT ;
    USE SIGNAL ;
    PORT
      LAYER M4 ;
        RECT  23.676 46.704 23.76 46.728 ;
    END
  END dst_d[214]
  PIN dst_d[215]
    DIRECTION OUTPUT ;
    USE SIGNAL ;
    PORT
      LAYER M4 ;
        RECT  23.676 46.944 23.76 46.968 ;
    END
  END dst_d[215]
  PIN dst_d[216]
    DIRECTION OUTPUT ;
    USE SIGNAL ;
    PORT
      LAYER M4 ;
        RECT  23.676 47.136 23.76 47.16 ;
    END
  END dst_d[216]
  PIN dst_d[217]
    DIRECTION OUTPUT ;
    USE SIGNAL ;
    PORT
      LAYER M4 ;
        RECT  23.676 47.328 23.76 47.352 ;
    END
  END dst_d[217]
  PIN dst_d[218]
    DIRECTION OUTPUT ;
    USE SIGNAL ;
    PORT
      LAYER M4 ;
        RECT  23.676 47.52 23.76 47.544 ;
    END
  END dst_d[218]
  PIN dst_d[219]
    DIRECTION OUTPUT ;
    USE SIGNAL ;
    PORT
      LAYER M4 ;
        RECT  23.676 47.76 23.76 47.784 ;
    END
  END dst_d[219]
  PIN dst_d[21]
    DIRECTION OUTPUT ;
    USE SIGNAL ;
    PORT
      LAYER M4 ;
        RECT  23.676 6.912 23.76 6.936 ;
    END
  END dst_d[21]
  PIN dst_d[220]
    DIRECTION OUTPUT ;
    USE SIGNAL ;
    PORT
      LAYER M4 ;
        RECT  23.676 47.952 23.76 47.976 ;
    END
  END dst_d[220]
  PIN dst_d[221]
    DIRECTION OUTPUT ;
    USE SIGNAL ;
    PORT
      LAYER M4 ;
        RECT  23.676 48.144 23.76 48.168 ;
    END
  END dst_d[221]
  PIN dst_d[222]
    DIRECTION OUTPUT ;
    USE SIGNAL ;
    PORT
      LAYER M4 ;
        RECT  23.676 48.384 23.76 48.408 ;
    END
  END dst_d[222]
  PIN dst_d[223]
    DIRECTION OUTPUT ;
    USE SIGNAL ;
    PORT
      LAYER M4 ;
        RECT  23.676 48.576 23.76 48.6 ;
    END
  END dst_d[223]
  PIN dst_d[224]
    DIRECTION OUTPUT ;
    USE SIGNAL ;
    PORT
      LAYER M4 ;
        RECT  23.676 48.768 23.76 48.792 ;
    END
  END dst_d[224]
  PIN dst_d[225]
    DIRECTION OUTPUT ;
    USE SIGNAL ;
    PORT
      LAYER M4 ;
        RECT  23.676 48.96 23.76 48.984 ;
    END
  END dst_d[225]
  PIN dst_d[226]
    DIRECTION OUTPUT ;
    USE SIGNAL ;
    PORT
      LAYER M4 ;
        RECT  23.676 49.2 23.76 49.224 ;
    END
  END dst_d[226]
  PIN dst_d[227]
    DIRECTION OUTPUT ;
    USE SIGNAL ;
    PORT
      LAYER M4 ;
        RECT  23.676 49.392 23.76 49.416 ;
    END
  END dst_d[227]
  PIN dst_d[228]
    DIRECTION OUTPUT ;
    USE SIGNAL ;
    PORT
      LAYER M4 ;
        RECT  23.676 49.584 23.76 49.608 ;
    END
  END dst_d[228]
  PIN dst_d[229]
    DIRECTION OUTPUT ;
    USE SIGNAL ;
    PORT
      LAYER M4 ;
        RECT  23.676 49.824 23.76 49.848 ;
    END
  END dst_d[229]
  PIN dst_d[22]
    DIRECTION OUTPUT ;
    USE SIGNAL ;
    PORT
      LAYER M4 ;
        RECT  23.676 7.104 23.76 7.128 ;
    END
  END dst_d[22]
  PIN dst_d[230]
    DIRECTION OUTPUT ;
    USE SIGNAL ;
    PORT
      LAYER M4 ;
        RECT  23.676 50.016 23.76 50.04 ;
    END
  END dst_d[230]
  PIN dst_d[231]
    DIRECTION OUTPUT ;
    USE SIGNAL ;
    PORT
      LAYER M4 ;
        RECT  23.676 50.208 23.76 50.232 ;
    END
  END dst_d[231]
  PIN dst_d[232]
    DIRECTION OUTPUT ;
    USE SIGNAL ;
    PORT
      LAYER M4 ;
        RECT  23.676 50.448 23.76 50.472 ;
    END
  END dst_d[232]
  PIN dst_d[233]
    DIRECTION OUTPUT ;
    USE SIGNAL ;
    PORT
      LAYER M4 ;
        RECT  23.676 50.64 23.76 50.664 ;
    END
  END dst_d[233]
  PIN dst_d[234]
    DIRECTION OUTPUT ;
    USE SIGNAL ;
    PORT
      LAYER M4 ;
        RECT  23.676 50.832 23.76 50.856 ;
    END
  END dst_d[234]
  PIN dst_d[235]
    DIRECTION OUTPUT ;
    USE SIGNAL ;
    PORT
      LAYER M4 ;
        RECT  23.676 51.024 23.76 51.048 ;
    END
  END dst_d[235]
  PIN dst_d[236]
    DIRECTION OUTPUT ;
    USE SIGNAL ;
    PORT
      LAYER M4 ;
        RECT  23.676 51.264 23.76 51.288 ;
    END
  END dst_d[236]
  PIN dst_d[237]
    DIRECTION OUTPUT ;
    USE SIGNAL ;
    PORT
      LAYER M4 ;
        RECT  23.676 51.456 23.76 51.48 ;
    END
  END dst_d[237]
  PIN dst_d[238]
    DIRECTION OUTPUT ;
    USE SIGNAL ;
    PORT
      LAYER M4 ;
        RECT  23.676 51.648 23.76 51.672 ;
    END
  END dst_d[238]
  PIN dst_d[239]
    DIRECTION OUTPUT ;
    USE SIGNAL ;
    PORT
      LAYER M4 ;
        RECT  23.676 51.888 23.76 51.912 ;
    END
  END dst_d[239]
  PIN dst_d[23]
    DIRECTION OUTPUT ;
    USE SIGNAL ;
    PORT
      LAYER M4 ;
        RECT  23.676 7.344 23.76 7.368 ;
    END
  END dst_d[23]
  PIN dst_d[240]
    DIRECTION OUTPUT ;
    USE SIGNAL ;
    PORT
      LAYER M4 ;
        RECT  23.676 52.08 23.76 52.104 ;
    END
  END dst_d[240]
  PIN dst_d[241]
    DIRECTION OUTPUT ;
    USE SIGNAL ;
    PORT
      LAYER M4 ;
        RECT  23.676 52.272 23.76 52.296 ;
    END
  END dst_d[241]
  PIN dst_d[242]
    DIRECTION OUTPUT ;
    USE SIGNAL ;
    PORT
      LAYER M4 ;
        RECT  23.676 52.464 23.76 52.488 ;
    END
  END dst_d[242]
  PIN dst_d[243]
    DIRECTION OUTPUT ;
    USE SIGNAL ;
    PORT
      LAYER M4 ;
        RECT  23.676 52.704 23.76 52.728 ;
    END
  END dst_d[243]
  PIN dst_d[244]
    DIRECTION OUTPUT ;
    USE SIGNAL ;
    PORT
      LAYER M4 ;
        RECT  23.676 52.896 23.76 52.92 ;
    END
  END dst_d[244]
  PIN dst_d[245]
    DIRECTION OUTPUT ;
    USE SIGNAL ;
    PORT
      LAYER M4 ;
        RECT  23.676 53.088 23.76 53.112 ;
    END
  END dst_d[245]
  PIN dst_d[246]
    DIRECTION OUTPUT ;
    USE SIGNAL ;
    PORT
      LAYER M4 ;
        RECT  23.676 53.328 23.76 53.352 ;
    END
  END dst_d[246]
  PIN dst_d[247]
    DIRECTION OUTPUT ;
    USE SIGNAL ;
    PORT
      LAYER M4 ;
        RECT  23.676 53.52 23.76 53.544 ;
    END
  END dst_d[247]
  PIN dst_d[248]
    DIRECTION OUTPUT ;
    USE SIGNAL ;
    PORT
      LAYER M4 ;
        RECT  23.676 53.712 23.76 53.736 ;
    END
  END dst_d[248]
  PIN dst_d[249]
    DIRECTION OUTPUT ;
    USE SIGNAL ;
    PORT
      LAYER M4 ;
        RECT  23.676 53.952 23.76 53.976 ;
    END
  END dst_d[249]
  PIN dst_d[24]
    DIRECTION OUTPUT ;
    USE SIGNAL ;
    PORT
      LAYER M4 ;
        RECT  23.676 7.536 23.76 7.56 ;
    END
  END dst_d[24]
  PIN dst_d[250]
    DIRECTION OUTPUT ;
    USE SIGNAL ;
    PORT
      LAYER M4 ;
        RECT  23.676 54.144 23.76 54.168 ;
    END
  END dst_d[250]
  PIN dst_d[251]
    DIRECTION OUTPUT ;
    USE SIGNAL ;
    PORT
      LAYER M4 ;
        RECT  23.676 54.336 23.76 54.36 ;
    END
  END dst_d[251]
  PIN dst_d[252]
    DIRECTION OUTPUT ;
    USE SIGNAL ;
    PORT
      LAYER M4 ;
        RECT  23.676 54.528 23.76 54.552 ;
    END
  END dst_d[252]
  PIN dst_d[253]
    DIRECTION OUTPUT ;
    USE SIGNAL ;
    PORT
      LAYER M4 ;
        RECT  23.676 54.768 23.76 54.792 ;
    END
  END dst_d[253]
  PIN dst_d[254]
    DIRECTION OUTPUT ;
    USE SIGNAL ;
    PORT
      LAYER M4 ;
        RECT  23.676 54.96 23.76 54.984 ;
    END
  END dst_d[254]
  PIN dst_d[255]
    DIRECTION OUTPUT ;
    USE SIGNAL ;
    PORT
      LAYER M4 ;
        RECT  23.676 55.152 23.76 55.176 ;
    END
  END dst_d[255]
  PIN dst_d[256]
    DIRECTION OUTPUT ;
    USE SIGNAL ;
    PORT
      LAYER M4 ;
        RECT  23.676 55.392 23.76 55.416 ;
    END
  END dst_d[256]
  PIN dst_d[257]
    DIRECTION OUTPUT ;
    USE SIGNAL ;
    PORT
      LAYER M4 ;
        RECT  23.676 55.584 23.76 55.608 ;
    END
  END dst_d[257]
  PIN dst_d[258]
    DIRECTION OUTPUT ;
    USE SIGNAL ;
    PORT
      LAYER M4 ;
        RECT  23.676 55.776 23.76 55.8 ;
    END
  END dst_d[258]
  PIN dst_d[259]
    DIRECTION OUTPUT ;
    USE SIGNAL ;
    PORT
      LAYER M4 ;
        RECT  23.676 56.016 23.76 56.04 ;
    END
  END dst_d[259]
  PIN dst_d[25]
    DIRECTION OUTPUT ;
    USE SIGNAL ;
    PORT
      LAYER M4 ;
        RECT  23.676 7.728 23.76 7.752 ;
    END
  END dst_d[25]
  PIN dst_d[260]
    DIRECTION OUTPUT ;
    USE SIGNAL ;
    PORT
      LAYER M4 ;
        RECT  23.676 56.208 23.76 56.232 ;
    END
  END dst_d[260]
  PIN dst_d[261]
    DIRECTION OUTPUT ;
    USE SIGNAL ;
    PORT
      LAYER M4 ;
        RECT  23.676 56.4 23.76 56.424 ;
    END
  END dst_d[261]
  PIN dst_d[262]
    DIRECTION OUTPUT ;
    USE SIGNAL ;
    PORT
      LAYER M4 ;
        RECT  23.676 56.592 23.76 56.616 ;
    END
  END dst_d[262]
  PIN dst_d[263]
    DIRECTION OUTPUT ;
    USE SIGNAL ;
    PORT
      LAYER M4 ;
        RECT  23.676 56.832 23.76 56.856 ;
    END
  END dst_d[263]
  PIN dst_d[264]
    DIRECTION OUTPUT ;
    USE SIGNAL ;
    PORT
      LAYER M4 ;
        RECT  23.676 57.024 23.76 57.048 ;
    END
  END dst_d[264]
  PIN dst_d[265]
    DIRECTION OUTPUT ;
    USE SIGNAL ;
    PORT
      LAYER M4 ;
        RECT  23.676 57.216 23.76 57.24 ;
    END
  END dst_d[265]
  PIN dst_d[266]
    DIRECTION OUTPUT ;
    USE SIGNAL ;
    PORT
      LAYER M4 ;
        RECT  23.676 57.456 23.76 57.48 ;
    END
  END dst_d[266]
  PIN dst_d[267]
    DIRECTION OUTPUT ;
    USE SIGNAL ;
    PORT
      LAYER M4 ;
        RECT  23.676 57.648 23.76 57.672 ;
    END
  END dst_d[267]
  PIN dst_d[268]
    DIRECTION OUTPUT ;
    USE SIGNAL ;
    PORT
      LAYER M4 ;
        RECT  23.676 57.84 23.76 57.864 ;
    END
  END dst_d[268]
  PIN dst_d[269]
    DIRECTION OUTPUT ;
    USE SIGNAL ;
    PORT
      LAYER M4 ;
        RECT  23.676 58.032 23.76 58.056 ;
    END
  END dst_d[269]
  PIN dst_d[26]
    DIRECTION OUTPUT ;
    USE SIGNAL ;
    PORT
      LAYER M4 ;
        RECT  23.676 7.968 23.76 7.992 ;
    END
  END dst_d[26]
  PIN dst_d[270]
    DIRECTION OUTPUT ;
    USE SIGNAL ;
    PORT
      LAYER M4 ;
        RECT  23.676 58.272 23.76 58.296 ;
    END
  END dst_d[270]
  PIN dst_d[271]
    DIRECTION OUTPUT ;
    USE SIGNAL ;
    PORT
      LAYER M4 ;
        RECT  23.676 58.464 23.76 58.488 ;
    END
  END dst_d[271]
  PIN dst_d[272]
    DIRECTION OUTPUT ;
    USE SIGNAL ;
    PORT
      LAYER M4 ;
        RECT  23.676 58.656 23.76 58.68 ;
    END
  END dst_d[272]
  PIN dst_d[273]
    DIRECTION OUTPUT ;
    USE SIGNAL ;
    PORT
      LAYER M4 ;
        RECT  23.676 58.896 23.76 58.92 ;
    END
  END dst_d[273]
  PIN dst_d[274]
    DIRECTION OUTPUT ;
    USE SIGNAL ;
    PORT
      LAYER M4 ;
        RECT  23.676 59.088 23.76 59.112 ;
    END
  END dst_d[274]
  PIN dst_d[275]
    DIRECTION OUTPUT ;
    USE SIGNAL ;
    PORT
      LAYER M4 ;
        RECT  23.676 59.28 23.76 59.304 ;
    END
  END dst_d[275]
  PIN dst_d[276]
    DIRECTION OUTPUT ;
    USE SIGNAL ;
    PORT
      LAYER M4 ;
        RECT  23.676 59.52 23.76 59.544 ;
    END
  END dst_d[276]
  PIN dst_d[277]
    DIRECTION OUTPUT ;
    USE SIGNAL ;
    PORT
      LAYER M4 ;
        RECT  23.676 59.712 23.76 59.736 ;
    END
  END dst_d[277]
  PIN dst_d[278]
    DIRECTION OUTPUT ;
    USE SIGNAL ;
    PORT
      LAYER M4 ;
        RECT  23.676 59.904 23.76 59.928 ;
    END
  END dst_d[278]
  PIN dst_d[279]
    DIRECTION OUTPUT ;
    USE SIGNAL ;
    PORT
      LAYER M4 ;
        RECT  23.676 60.096 23.76 60.12 ;
    END
  END dst_d[279]
  PIN dst_d[27]
    DIRECTION OUTPUT ;
    USE SIGNAL ;
    PORT
      LAYER M4 ;
        RECT  23.676 8.16 23.76 8.184 ;
    END
  END dst_d[27]
  PIN dst_d[280]
    DIRECTION OUTPUT ;
    USE SIGNAL ;
    PORT
      LAYER M4 ;
        RECT  23.676 60.336 23.76 60.36 ;
    END
  END dst_d[280]
  PIN dst_d[281]
    DIRECTION OUTPUT ;
    USE SIGNAL ;
    PORT
      LAYER M4 ;
        RECT  23.676 60.528 23.76 60.552 ;
    END
  END dst_d[281]
  PIN dst_d[282]
    DIRECTION OUTPUT ;
    USE SIGNAL ;
    PORT
      LAYER M4 ;
        RECT  23.676 60.72 23.76 60.744 ;
    END
  END dst_d[282]
  PIN dst_d[283]
    DIRECTION OUTPUT ;
    USE SIGNAL ;
    PORT
      LAYER M4 ;
        RECT  23.676 60.96 23.76 60.984 ;
    END
  END dst_d[283]
  PIN dst_d[284]
    DIRECTION OUTPUT ;
    USE SIGNAL ;
    PORT
      LAYER M4 ;
        RECT  23.676 61.152 23.76 61.176 ;
    END
  END dst_d[284]
  PIN dst_d[285]
    DIRECTION OUTPUT ;
    USE SIGNAL ;
    PORT
      LAYER M4 ;
        RECT  23.676 61.344 23.76 61.368 ;
    END
  END dst_d[285]
  PIN dst_d[286]
    DIRECTION OUTPUT ;
    USE SIGNAL ;
    PORT
      LAYER M4 ;
        RECT  23.676 61.536 23.76 61.56 ;
    END
  END dst_d[286]
  PIN dst_d[287]
    DIRECTION OUTPUT ;
    USE SIGNAL ;
    PORT
      LAYER M4 ;
        RECT  23.676 61.776 23.76 61.8 ;
    END
  END dst_d[287]
  PIN dst_d[288]
    DIRECTION OUTPUT ;
    USE SIGNAL ;
    PORT
      LAYER M4 ;
        RECT  23.676 61.968 23.76 61.992 ;
    END
  END dst_d[288]
  PIN dst_d[289]
    DIRECTION OUTPUT ;
    USE SIGNAL ;
    PORT
      LAYER M4 ;
        RECT  23.676 62.16 23.76 62.184 ;
    END
  END dst_d[289]
  PIN dst_d[28]
    DIRECTION OUTPUT ;
    USE SIGNAL ;
    PORT
      LAYER M4 ;
        RECT  23.676 8.352 23.76 8.376 ;
    END
  END dst_d[28]
  PIN dst_d[290]
    DIRECTION OUTPUT ;
    USE SIGNAL ;
    PORT
      LAYER M4 ;
        RECT  23.676 62.4 23.76 62.424 ;
    END
  END dst_d[290]
  PIN dst_d[291]
    DIRECTION OUTPUT ;
    USE SIGNAL ;
    PORT
      LAYER M4 ;
        RECT  23.676 62.592 23.76 62.616 ;
    END
  END dst_d[291]
  PIN dst_d[292]
    DIRECTION OUTPUT ;
    USE SIGNAL ;
    PORT
      LAYER M4 ;
        RECT  23.676 62.784 23.76 62.808 ;
    END
  END dst_d[292]
  PIN dst_d[293]
    DIRECTION OUTPUT ;
    USE SIGNAL ;
    PORT
      LAYER M4 ;
        RECT  23.676 63.024 23.76 63.048 ;
    END
  END dst_d[293]
  PIN dst_d[294]
    DIRECTION OUTPUT ;
    USE SIGNAL ;
    PORT
      LAYER M4 ;
        RECT  23.676 63.216 23.76 63.24 ;
    END
  END dst_d[294]
  PIN dst_d[295]
    DIRECTION OUTPUT ;
    USE SIGNAL ;
    PORT
      LAYER M4 ;
        RECT  23.676 63.408 23.76 63.432 ;
    END
  END dst_d[295]
  PIN dst_d[296]
    DIRECTION OUTPUT ;
    USE SIGNAL ;
    PORT
      LAYER M4 ;
        RECT  23.676 63.6 23.76 63.624 ;
    END
  END dst_d[296]
  PIN dst_d[297]
    DIRECTION OUTPUT ;
    USE SIGNAL ;
    PORT
      LAYER M4 ;
        RECT  23.676 63.84 23.76 63.864 ;
    END
  END dst_d[297]
  PIN dst_d[298]
    DIRECTION OUTPUT ;
    USE SIGNAL ;
    PORT
      LAYER M4 ;
        RECT  23.676 64.032 23.76 64.056 ;
    END
  END dst_d[298]
  PIN dst_d[299]
    DIRECTION OUTPUT ;
    USE SIGNAL ;
    PORT
      LAYER M4 ;
        RECT  23.676 64.224 23.76 64.248 ;
    END
  END dst_d[299]
  PIN dst_d[29]
    DIRECTION OUTPUT ;
    USE SIGNAL ;
    PORT
      LAYER M4 ;
        RECT  23.676 8.592 23.76 8.616 ;
    END
  END dst_d[29]
  PIN dst_d[2]
    DIRECTION OUTPUT ;
    USE SIGNAL ;
    PORT
      LAYER M4 ;
        RECT  23.676 3.024 23.76 3.048 ;
    END
  END dst_d[2]
  PIN dst_d[300]
    DIRECTION OUTPUT ;
    USE SIGNAL ;
    PORT
      LAYER M4 ;
        RECT  23.676 64.464 23.76 64.488 ;
    END
  END dst_d[300]
  PIN dst_d[301]
    DIRECTION OUTPUT ;
    USE SIGNAL ;
    PORT
      LAYER M4 ;
        RECT  23.676 64.656 23.76 64.68 ;
    END
  END dst_d[301]
  PIN dst_d[302]
    DIRECTION OUTPUT ;
    USE SIGNAL ;
    PORT
      LAYER M4 ;
        RECT  23.676 64.848 23.76 64.872 ;
    END
  END dst_d[302]
  PIN dst_d[303]
    DIRECTION OUTPUT ;
    USE SIGNAL ;
    PORT
      LAYER M4 ;
        RECT  23.676 65.088 23.76 65.112 ;
    END
  END dst_d[303]
  PIN dst_d[304]
    DIRECTION OUTPUT ;
    USE SIGNAL ;
    PORT
      LAYER M4 ;
        RECT  23.676 65.28 23.76 65.304 ;
    END
  END dst_d[304]
  PIN dst_d[305]
    DIRECTION OUTPUT ;
    USE SIGNAL ;
    PORT
      LAYER M4 ;
        RECT  23.676 65.472 23.76 65.496 ;
    END
  END dst_d[305]
  PIN dst_d[306]
    DIRECTION OUTPUT ;
    USE SIGNAL ;
    PORT
      LAYER M4 ;
        RECT  23.676 65.664 23.76 65.688 ;
    END
  END dst_d[306]
  PIN dst_d[307]
    DIRECTION OUTPUT ;
    USE SIGNAL ;
    PORT
      LAYER M4 ;
        RECT  23.676 65.904 23.76 65.928 ;
    END
  END dst_d[307]
  PIN dst_d[308]
    DIRECTION OUTPUT ;
    USE SIGNAL ;
    PORT
      LAYER M4 ;
        RECT  23.676 66.096 23.76 66.12 ;
    END
  END dst_d[308]
  PIN dst_d[309]
    DIRECTION OUTPUT ;
    USE SIGNAL ;
    PORT
      LAYER M4 ;
        RECT  23.676 66.288 23.76 66.312 ;
    END
  END dst_d[309]
  PIN dst_d[30]
    DIRECTION OUTPUT ;
    USE SIGNAL ;
    PORT
      LAYER M4 ;
        RECT  23.676 8.784 23.76 8.808 ;
    END
  END dst_d[30]
  PIN dst_d[310]
    DIRECTION OUTPUT ;
    USE SIGNAL ;
    PORT
      LAYER M4 ;
        RECT  23.676 66.528 23.76 66.552 ;
    END
  END dst_d[310]
  PIN dst_d[311]
    DIRECTION OUTPUT ;
    USE SIGNAL ;
    PORT
      LAYER M4 ;
        RECT  23.676 66.72 23.76 66.744 ;
    END
  END dst_d[311]
  PIN dst_d[312]
    DIRECTION OUTPUT ;
    USE SIGNAL ;
    PORT
      LAYER M4 ;
        RECT  23.676 66.912 23.76 66.936 ;
    END
  END dst_d[312]
  PIN dst_d[313]
    DIRECTION OUTPUT ;
    USE SIGNAL ;
    PORT
      LAYER M4 ;
        RECT  23.676 67.104 23.76 67.128 ;
    END
  END dst_d[313]
  PIN dst_d[314]
    DIRECTION OUTPUT ;
    USE SIGNAL ;
    PORT
      LAYER M4 ;
        RECT  23.676 67.344 23.76 67.368 ;
    END
  END dst_d[314]
  PIN dst_d[315]
    DIRECTION OUTPUT ;
    USE SIGNAL ;
    PORT
      LAYER M4 ;
        RECT  23.676 67.536 23.76 67.56 ;
    END
  END dst_d[315]
  PIN dst_d[316]
    DIRECTION OUTPUT ;
    USE SIGNAL ;
    PORT
      LAYER M4 ;
        RECT  23.676 67.728 23.76 67.752 ;
    END
  END dst_d[316]
  PIN dst_d[317]
    DIRECTION OUTPUT ;
    USE SIGNAL ;
    PORT
      LAYER M4 ;
        RECT  23.676 67.968 23.76 67.992 ;
    END
  END dst_d[317]
  PIN dst_d[318]
    DIRECTION OUTPUT ;
    USE SIGNAL ;
    PORT
      LAYER M4 ;
        RECT  23.676 68.16 23.76 68.184 ;
    END
  END dst_d[318]
  PIN dst_d[319]
    DIRECTION OUTPUT ;
    USE SIGNAL ;
    PORT
      LAYER M4 ;
        RECT  23.676 68.352 23.76 68.376 ;
    END
  END dst_d[319]
  PIN dst_d[31]
    DIRECTION OUTPUT ;
    USE SIGNAL ;
    PORT
      LAYER M4 ;
        RECT  23.676 8.976 23.76 9 ;
    END
  END dst_d[31]
  PIN dst_d[320]
    DIRECTION OUTPUT ;
    USE SIGNAL ;
    PORT
      LAYER M4 ;
        RECT  23.676 68.592 23.76 68.616 ;
    END
  END dst_d[320]
  PIN dst_d[321]
    DIRECTION OUTPUT ;
    USE SIGNAL ;
    PORT
      LAYER M4 ;
        RECT  23.676 68.784 23.76 68.808 ;
    END
  END dst_d[321]
  PIN dst_d[322]
    DIRECTION OUTPUT ;
    USE SIGNAL ;
    PORT
      LAYER M4 ;
        RECT  23.676 68.976 23.76 69 ;
    END
  END dst_d[322]
  PIN dst_d[323]
    DIRECTION OUTPUT ;
    USE SIGNAL ;
    PORT
      LAYER M4 ;
        RECT  23.676 69.168 23.76 69.192 ;
    END
  END dst_d[323]
  PIN dst_d[324]
    DIRECTION OUTPUT ;
    USE SIGNAL ;
    PORT
      LAYER M4 ;
        RECT  23.676 69.408 23.76 69.432 ;
    END
  END dst_d[324]
  PIN dst_d[325]
    DIRECTION OUTPUT ;
    USE SIGNAL ;
    PORT
      LAYER M4 ;
        RECT  23.676 69.6 23.76 69.624 ;
    END
  END dst_d[325]
  PIN dst_d[326]
    DIRECTION OUTPUT ;
    USE SIGNAL ;
    PORT
      LAYER M4 ;
        RECT  23.676 69.792 23.76 69.816 ;
    END
  END dst_d[326]
  PIN dst_d[327]
    DIRECTION OUTPUT ;
    USE SIGNAL ;
    PORT
      LAYER M4 ;
        RECT  23.676 70.032 23.76 70.056 ;
    END
  END dst_d[327]
  PIN dst_d[328]
    DIRECTION OUTPUT ;
    USE SIGNAL ;
    PORT
      LAYER M4 ;
        RECT  23.676 70.224 23.76 70.248 ;
    END
  END dst_d[328]
  PIN dst_d[329]
    DIRECTION OUTPUT ;
    USE SIGNAL ;
    PORT
      LAYER M4 ;
        RECT  23.676 70.416 23.76 70.44 ;
    END
  END dst_d[329]
  PIN dst_d[32]
    DIRECTION OUTPUT ;
    USE SIGNAL ;
    PORT
      LAYER M4 ;
        RECT  23.676 9.168 23.76 9.192 ;
    END
  END dst_d[32]
  PIN dst_d[330]
    DIRECTION OUTPUT ;
    USE SIGNAL ;
    PORT
      LAYER M4 ;
        RECT  23.676 70.608 23.76 70.632 ;
    END
  END dst_d[330]
  PIN dst_d[331]
    DIRECTION OUTPUT ;
    USE SIGNAL ;
    PORT
      LAYER M4 ;
        RECT  23.676 70.848 23.76 70.872 ;
    END
  END dst_d[331]
  PIN dst_d[332]
    DIRECTION OUTPUT ;
    USE SIGNAL ;
    PORT
      LAYER M4 ;
        RECT  23.676 71.04 23.76 71.064 ;
    END
  END dst_d[332]
  PIN dst_d[333]
    DIRECTION OUTPUT ;
    USE SIGNAL ;
    PORT
      LAYER M4 ;
        RECT  23.676 71.232 23.76 71.256 ;
    END
  END dst_d[333]
  PIN dst_d[334]
    DIRECTION OUTPUT ;
    USE SIGNAL ;
    PORT
      LAYER M4 ;
        RECT  23.676 71.472 23.76 71.496 ;
    END
  END dst_d[334]
  PIN dst_d[335]
    DIRECTION OUTPUT ;
    USE SIGNAL ;
    PORT
      LAYER M4 ;
        RECT  23.676 71.664 23.76 71.688 ;
    END
  END dst_d[335]
  PIN dst_d[336]
    DIRECTION OUTPUT ;
    USE SIGNAL ;
    PORT
      LAYER M4 ;
        RECT  23.676 71.856 23.76 71.88 ;
    END
  END dst_d[336]
  PIN dst_d[337]
    DIRECTION OUTPUT ;
    USE SIGNAL ;
    PORT
      LAYER M4 ;
        RECT  23.676 72.096 23.76 72.12 ;
    END
  END dst_d[337]
  PIN dst_d[338]
    DIRECTION OUTPUT ;
    USE SIGNAL ;
    PORT
      LAYER M4 ;
        RECT  23.676 72.288 23.76 72.312 ;
    END
  END dst_d[338]
  PIN dst_d[339]
    DIRECTION OUTPUT ;
    USE SIGNAL ;
    PORT
      LAYER M4 ;
        RECT  23.676 72.48 23.76 72.504 ;
    END
  END dst_d[339]
  PIN dst_d[33]
    DIRECTION OUTPUT ;
    USE SIGNAL ;
    PORT
      LAYER M4 ;
        RECT  23.676 9.408 23.76 9.432 ;
    END
  END dst_d[33]
  PIN dst_d[340]
    DIRECTION OUTPUT ;
    USE SIGNAL ;
    PORT
      LAYER M4 ;
        RECT  23.676 72.672 23.76 72.696 ;
    END
  END dst_d[340]
  PIN dst_d[341]
    DIRECTION OUTPUT ;
    USE SIGNAL ;
    PORT
      LAYER M4 ;
        RECT  23.676 72.912 23.76 72.936 ;
    END
  END dst_d[341]
  PIN dst_d[342]
    DIRECTION OUTPUT ;
    USE SIGNAL ;
    PORT
      LAYER M4 ;
        RECT  23.676 73.104 23.76 73.128 ;
    END
  END dst_d[342]
  PIN dst_d[343]
    DIRECTION OUTPUT ;
    USE SIGNAL ;
    PORT
      LAYER M4 ;
        RECT  23.676 73.296 23.76 73.32 ;
    END
  END dst_d[343]
  PIN dst_d[344]
    DIRECTION OUTPUT ;
    USE SIGNAL ;
    PORT
      LAYER M4 ;
        RECT  23.676 73.536 23.76 73.56 ;
    END
  END dst_d[344]
  PIN dst_d[345]
    DIRECTION OUTPUT ;
    USE SIGNAL ;
    PORT
      LAYER M4 ;
        RECT  23.676 73.728 23.76 73.752 ;
    END
  END dst_d[345]
  PIN dst_d[346]
    DIRECTION OUTPUT ;
    USE SIGNAL ;
    PORT
      LAYER M4 ;
        RECT  23.676 73.92 23.76 73.944 ;
    END
  END dst_d[346]
  PIN dst_d[347]
    DIRECTION OUTPUT ;
    USE SIGNAL ;
    PORT
      LAYER M4 ;
        RECT  23.676 74.16 23.76 74.184 ;
    END
  END dst_d[347]
  PIN dst_d[348]
    DIRECTION OUTPUT ;
    USE SIGNAL ;
    PORT
      LAYER M4 ;
        RECT  23.676 74.352 23.76 74.376 ;
    END
  END dst_d[348]
  PIN dst_d[349]
    DIRECTION OUTPUT ;
    USE SIGNAL ;
    PORT
      LAYER M4 ;
        RECT  23.676 74.544 23.76 74.568 ;
    END
  END dst_d[349]
  PIN dst_d[34]
    DIRECTION OUTPUT ;
    USE SIGNAL ;
    PORT
      LAYER M4 ;
        RECT  23.676 9.6 23.76 9.624 ;
    END
  END dst_d[34]
  PIN dst_d[350]
    DIRECTION OUTPUT ;
    USE SIGNAL ;
    PORT
      LAYER M4 ;
        RECT  23.676 74.736 23.76 74.76 ;
    END
  END dst_d[350]
  PIN dst_d[351]
    DIRECTION OUTPUT ;
    USE SIGNAL ;
    PORT
      LAYER M4 ;
        RECT  23.676 74.976 23.76 75 ;
    END
  END dst_d[351]
  PIN dst_d[352]
    DIRECTION OUTPUT ;
    USE SIGNAL ;
    PORT
      LAYER M4 ;
        RECT  23.676 75.168 23.76 75.192 ;
    END
  END dst_d[352]
  PIN dst_d[353]
    DIRECTION OUTPUT ;
    USE SIGNAL ;
    PORT
      LAYER M4 ;
        RECT  23.676 75.36 23.76 75.384 ;
    END
  END dst_d[353]
  PIN dst_d[354]
    DIRECTION OUTPUT ;
    USE SIGNAL ;
    PORT
      LAYER M4 ;
        RECT  23.676 75.6 23.76 75.624 ;
    END
  END dst_d[354]
  PIN dst_d[355]
    DIRECTION OUTPUT ;
    USE SIGNAL ;
    PORT
      LAYER M4 ;
        RECT  23.676 75.792 23.76 75.816 ;
    END
  END dst_d[355]
  PIN dst_d[356]
    DIRECTION OUTPUT ;
    USE SIGNAL ;
    PORT
      LAYER M4 ;
        RECT  23.676 75.984 23.76 76.008 ;
    END
  END dst_d[356]
  PIN dst_d[357]
    DIRECTION OUTPUT ;
    USE SIGNAL ;
    PORT
      LAYER M4 ;
        RECT  23.676 76.176 23.76 76.2 ;
    END
  END dst_d[357]
  PIN dst_d[358]
    DIRECTION OUTPUT ;
    USE SIGNAL ;
    PORT
      LAYER M4 ;
        RECT  23.676 76.416 23.76 76.44 ;
    END
  END dst_d[358]
  PIN dst_d[359]
    DIRECTION OUTPUT ;
    USE SIGNAL ;
    PORT
      LAYER M4 ;
        RECT  23.676 76.608 23.76 76.632 ;
    END
  END dst_d[359]
  PIN dst_d[35]
    DIRECTION OUTPUT ;
    USE SIGNAL ;
    PORT
      LAYER M4 ;
        RECT  23.676 9.792 23.76 9.816 ;
    END
  END dst_d[35]
  PIN dst_d[360]
    DIRECTION OUTPUT ;
    USE SIGNAL ;
    PORT
      LAYER M4 ;
        RECT  23.676 76.8 23.76 76.824 ;
    END
  END dst_d[360]
  PIN dst_d[361]
    DIRECTION OUTPUT ;
    USE SIGNAL ;
    PORT
      LAYER M4 ;
        RECT  23.676 77.04 23.76 77.064 ;
    END
  END dst_d[361]
  PIN dst_d[362]
    DIRECTION OUTPUT ;
    USE SIGNAL ;
    PORT
      LAYER M4 ;
        RECT  23.676 77.232 23.76 77.256 ;
    END
  END dst_d[362]
  PIN dst_d[363]
    DIRECTION OUTPUT ;
    USE SIGNAL ;
    PORT
      LAYER M4 ;
        RECT  23.676 77.424 23.76 77.448 ;
    END
  END dst_d[363]
  PIN dst_d[364]
    DIRECTION OUTPUT ;
    USE SIGNAL ;
    PORT
      LAYER M4 ;
        RECT  23.676 77.664 23.76 77.688 ;
    END
  END dst_d[364]
  PIN dst_d[365]
    DIRECTION OUTPUT ;
    USE SIGNAL ;
    PORT
      LAYER M4 ;
        RECT  23.676 77.856 23.76 77.88 ;
    END
  END dst_d[365]
  PIN dst_d[366]
    DIRECTION OUTPUT ;
    USE SIGNAL ;
    PORT
      LAYER M4 ;
        RECT  23.676 78.048 23.76 78.072 ;
    END
  END dst_d[366]
  PIN dst_d[367]
    DIRECTION OUTPUT ;
    USE SIGNAL ;
    PORT
      LAYER M4 ;
        RECT  23.676 78.24 23.76 78.264 ;
    END
  END dst_d[367]
  PIN dst_d[368]
    DIRECTION OUTPUT ;
    USE SIGNAL ;
    PORT
      LAYER M4 ;
        RECT  23.676 78.48 23.76 78.504 ;
    END
  END dst_d[368]
  PIN dst_d[369]
    DIRECTION OUTPUT ;
    USE SIGNAL ;
    PORT
      LAYER M4 ;
        RECT  23.676 78.672 23.76 78.696 ;
    END
  END dst_d[369]
  PIN dst_d[36]
    DIRECTION OUTPUT ;
    USE SIGNAL ;
    PORT
      LAYER M4 ;
        RECT  23.676 10.032 23.76 10.056 ;
    END
  END dst_d[36]
  PIN dst_d[370]
    DIRECTION OUTPUT ;
    USE SIGNAL ;
    PORT
      LAYER M4 ;
        RECT  23.676 78.864 23.76 78.888 ;
    END
  END dst_d[370]
  PIN dst_d[371]
    DIRECTION OUTPUT ;
    USE SIGNAL ;
    PORT
      LAYER M4 ;
        RECT  23.676 79.104 23.76 79.128 ;
    END
  END dst_d[371]
  PIN dst_d[372]
    DIRECTION OUTPUT ;
    USE SIGNAL ;
    PORT
      LAYER M4 ;
        RECT  23.676 79.296 23.76 79.32 ;
    END
  END dst_d[372]
  PIN dst_d[373]
    DIRECTION OUTPUT ;
    USE SIGNAL ;
    PORT
      LAYER M4 ;
        RECT  23.676 79.488 23.76 79.512 ;
    END
  END dst_d[373]
  PIN dst_d[374]
    DIRECTION OUTPUT ;
    USE SIGNAL ;
    PORT
      LAYER M4 ;
        RECT  23.676 79.728 23.76 79.752 ;
    END
  END dst_d[374]
  PIN dst_d[375]
    DIRECTION OUTPUT ;
    USE SIGNAL ;
    PORT
      LAYER M4 ;
        RECT  23.676 79.92 23.76 79.944 ;
    END
  END dst_d[375]
  PIN dst_d[376]
    DIRECTION OUTPUT ;
    USE SIGNAL ;
    PORT
      LAYER M4 ;
        RECT  23.676 80.112 23.76 80.136 ;
    END
  END dst_d[376]
  PIN dst_d[377]
    DIRECTION OUTPUT ;
    USE SIGNAL ;
    PORT
      LAYER M4 ;
        RECT  23.676 80.304 23.76 80.328 ;
    END
  END dst_d[377]
  PIN dst_d[378]
    DIRECTION OUTPUT ;
    USE SIGNAL ;
    PORT
      LAYER M4 ;
        RECT  23.676 80.544 23.76 80.568 ;
    END
  END dst_d[378]
  PIN dst_d[379]
    DIRECTION OUTPUT ;
    USE SIGNAL ;
    PORT
      LAYER M4 ;
        RECT  23.676 80.736 23.76 80.76 ;
    END
  END dst_d[379]
  PIN dst_d[37]
    DIRECTION OUTPUT ;
    USE SIGNAL ;
    PORT
      LAYER M4 ;
        RECT  23.676 10.224 23.76 10.248 ;
    END
  END dst_d[37]
  PIN dst_d[380]
    DIRECTION OUTPUT ;
    USE SIGNAL ;
    PORT
      LAYER M4 ;
        RECT  23.676 80.928 23.76 80.952 ;
    END
  END dst_d[380]
  PIN dst_d[381]
    DIRECTION OUTPUT ;
    USE SIGNAL ;
    PORT
      LAYER M4 ;
        RECT  23.676 81.168 23.76 81.192 ;
    END
  END dst_d[381]
  PIN dst_d[382]
    DIRECTION OUTPUT ;
    USE SIGNAL ;
    PORT
      LAYER M4 ;
        RECT  23.676 81.36 23.76 81.384 ;
    END
  END dst_d[382]
  PIN dst_d[383]
    DIRECTION OUTPUT ;
    USE SIGNAL ;
    PORT
      LAYER M4 ;
        RECT  23.676 81.552 23.76 81.576 ;
    END
  END dst_d[383]
  PIN dst_d[384]
    DIRECTION OUTPUT ;
    USE SIGNAL ;
    PORT
      LAYER M4 ;
        RECT  23.676 81.744 23.76 81.768 ;
    END
  END dst_d[384]
  PIN dst_d[385]
    DIRECTION OUTPUT ;
    USE SIGNAL ;
    PORT
      LAYER M4 ;
        RECT  23.676 81.984 23.76 82.008 ;
    END
  END dst_d[385]
  PIN dst_d[386]
    DIRECTION OUTPUT ;
    USE SIGNAL ;
    PORT
      LAYER M4 ;
        RECT  23.676 82.176 23.76 82.2 ;
    END
  END dst_d[386]
  PIN dst_d[387]
    DIRECTION OUTPUT ;
    USE SIGNAL ;
    PORT
      LAYER M4 ;
        RECT  23.676 82.368 23.76 82.392 ;
    END
  END dst_d[387]
  PIN dst_d[388]
    DIRECTION OUTPUT ;
    USE SIGNAL ;
    PORT
      LAYER M4 ;
        RECT  23.676 82.608 23.76 82.632 ;
    END
  END dst_d[388]
  PIN dst_d[389]
    DIRECTION OUTPUT ;
    USE SIGNAL ;
    PORT
      LAYER M4 ;
        RECT  23.676 82.8 23.76 82.824 ;
    END
  END dst_d[389]
  PIN dst_d[38]
    DIRECTION OUTPUT ;
    USE SIGNAL ;
    PORT
      LAYER M4 ;
        RECT  23.676 10.416 23.76 10.44 ;
    END
  END dst_d[38]
  PIN dst_d[390]
    DIRECTION OUTPUT ;
    USE SIGNAL ;
    PORT
      LAYER M4 ;
        RECT  23.676 82.992 23.76 83.016 ;
    END
  END dst_d[390]
  PIN dst_d[391]
    DIRECTION OUTPUT ;
    USE SIGNAL ;
    PORT
      LAYER M4 ;
        RECT  23.676 83.232 23.76 83.256 ;
    END
  END dst_d[391]
  PIN dst_d[392]
    DIRECTION OUTPUT ;
    USE SIGNAL ;
    PORT
      LAYER M4 ;
        RECT  23.676 83.424 23.76 83.448 ;
    END
  END dst_d[392]
  PIN dst_d[393]
    DIRECTION OUTPUT ;
    USE SIGNAL ;
    PORT
      LAYER M4 ;
        RECT  23.676 83.616 23.76 83.64 ;
    END
  END dst_d[393]
  PIN dst_d[394]
    DIRECTION OUTPUT ;
    USE SIGNAL ;
    PORT
      LAYER M4 ;
        RECT  23.676 83.808 23.76 83.832 ;
    END
  END dst_d[394]
  PIN dst_d[395]
    DIRECTION OUTPUT ;
    USE SIGNAL ;
    PORT
      LAYER M4 ;
        RECT  23.676 84.048 23.76 84.072 ;
    END
  END dst_d[395]
  PIN dst_d[396]
    DIRECTION OUTPUT ;
    USE SIGNAL ;
    PORT
      LAYER M4 ;
        RECT  23.676 84.24 23.76 84.264 ;
    END
  END dst_d[396]
  PIN dst_d[397]
    DIRECTION OUTPUT ;
    USE SIGNAL ;
    PORT
      LAYER M4 ;
        RECT  23.676 84.432 23.76 84.456 ;
    END
  END dst_d[397]
  PIN dst_d[398]
    DIRECTION OUTPUT ;
    USE SIGNAL ;
    PORT
      LAYER M4 ;
        RECT  23.676 84.672 23.76 84.696 ;
    END
  END dst_d[398]
  PIN dst_d[399]
    DIRECTION OUTPUT ;
    USE SIGNAL ;
    PORT
      LAYER M4 ;
        RECT  23.676 84.864 23.76 84.888 ;
    END
  END dst_d[399]
  PIN dst_d[39]
    DIRECTION OUTPUT ;
    USE SIGNAL ;
    PORT
      LAYER M4 ;
        RECT  23.676 10.656 23.76 10.68 ;
    END
  END dst_d[39]
  PIN dst_d[3]
    DIRECTION OUTPUT ;
    USE SIGNAL ;
    PORT
      LAYER M4 ;
        RECT  23.676 3.216 23.76 3.24 ;
    END
  END dst_d[3]
  PIN dst_d[400]
    DIRECTION OUTPUT ;
    USE SIGNAL ;
    PORT
      LAYER M4 ;
        RECT  23.676 85.056 23.76 85.08 ;
    END
  END dst_d[400]
  PIN dst_d[401]
    DIRECTION OUTPUT ;
    USE SIGNAL ;
    PORT
      LAYER M4 ;
        RECT  23.676 85.248 23.76 85.272 ;
    END
  END dst_d[401]
  PIN dst_d[402]
    DIRECTION OUTPUT ;
    USE SIGNAL ;
    PORT
      LAYER M4 ;
        RECT  23.676 85.488 23.76 85.512 ;
    END
  END dst_d[402]
  PIN dst_d[403]
    DIRECTION OUTPUT ;
    USE SIGNAL ;
    PORT
      LAYER M4 ;
        RECT  23.676 85.68 23.76 85.704 ;
    END
  END dst_d[403]
  PIN dst_d[404]
    DIRECTION OUTPUT ;
    USE SIGNAL ;
    PORT
      LAYER M4 ;
        RECT  23.676 85.872 23.76 85.896 ;
    END
  END dst_d[404]
  PIN dst_d[405]
    DIRECTION OUTPUT ;
    USE SIGNAL ;
    PORT
      LAYER M4 ;
        RECT  23.676 86.112 23.76 86.136 ;
    END
  END dst_d[405]
  PIN dst_d[406]
    DIRECTION OUTPUT ;
    USE SIGNAL ;
    PORT
      LAYER M4 ;
        RECT  23.676 86.304 23.76 86.328 ;
    END
  END dst_d[406]
  PIN dst_d[407]
    DIRECTION OUTPUT ;
    USE SIGNAL ;
    PORT
      LAYER M4 ;
        RECT  23.676 86.496 23.76 86.52 ;
    END
  END dst_d[407]
  PIN dst_d[408]
    DIRECTION OUTPUT ;
    USE SIGNAL ;
    PORT
      LAYER M4 ;
        RECT  23.676 86.736 23.76 86.76 ;
    END
  END dst_d[408]
  PIN dst_d[409]
    DIRECTION OUTPUT ;
    USE SIGNAL ;
    PORT
      LAYER M4 ;
        RECT  23.676 86.928 23.76 86.952 ;
    END
  END dst_d[409]
  PIN dst_d[40]
    DIRECTION OUTPUT ;
    USE SIGNAL ;
    PORT
      LAYER M4 ;
        RECT  23.676 10.848 23.76 10.872 ;
    END
  END dst_d[40]
  PIN dst_d[410]
    DIRECTION OUTPUT ;
    USE SIGNAL ;
    PORT
      LAYER M4 ;
        RECT  23.676 87.12 23.76 87.144 ;
    END
  END dst_d[410]
  PIN dst_d[411]
    DIRECTION OUTPUT ;
    USE SIGNAL ;
    PORT
      LAYER M4 ;
        RECT  23.676 87.312 23.76 87.336 ;
    END
  END dst_d[411]
  PIN dst_d[412]
    DIRECTION OUTPUT ;
    USE SIGNAL ;
    PORT
      LAYER M4 ;
        RECT  23.676 87.552 23.76 87.576 ;
    END
  END dst_d[412]
  PIN dst_d[413]
    DIRECTION OUTPUT ;
    USE SIGNAL ;
    PORT
      LAYER M4 ;
        RECT  23.676 87.744 23.76 87.768 ;
    END
  END dst_d[413]
  PIN dst_d[414]
    DIRECTION OUTPUT ;
    USE SIGNAL ;
    PORT
      LAYER M4 ;
        RECT  23.676 87.936 23.76 87.96 ;
    END
  END dst_d[414]
  PIN dst_d[415]
    DIRECTION OUTPUT ;
    USE SIGNAL ;
    PORT
      LAYER M4 ;
        RECT  23.676 88.176 23.76 88.2 ;
    END
  END dst_d[415]
  PIN dst_d[416]
    DIRECTION OUTPUT ;
    USE SIGNAL ;
    PORT
      LAYER M4 ;
        RECT  23.676 88.368 23.76 88.392 ;
    END
  END dst_d[416]
  PIN dst_d[417]
    DIRECTION OUTPUT ;
    USE SIGNAL ;
    PORT
      LAYER M4 ;
        RECT  23.676 88.56 23.76 88.584 ;
    END
  END dst_d[417]
  PIN dst_d[418]
    DIRECTION OUTPUT ;
    USE SIGNAL ;
    PORT
      LAYER M4 ;
        RECT  23.676 88.8 23.76 88.824 ;
    END
  END dst_d[418]
  PIN dst_d[419]
    DIRECTION OUTPUT ;
    USE SIGNAL ;
    PORT
      LAYER M4 ;
        RECT  23.676 88.992 23.76 89.016 ;
    END
  END dst_d[419]
  PIN dst_d[41]
    DIRECTION OUTPUT ;
    USE SIGNAL ;
    PORT
      LAYER M4 ;
        RECT  23.676 11.04 23.76 11.064 ;
    END
  END dst_d[41]
  PIN dst_d[420]
    DIRECTION OUTPUT ;
    USE SIGNAL ;
    PORT
      LAYER M4 ;
        RECT  23.676 89.184 23.76 89.208 ;
    END
  END dst_d[420]
  PIN dst_d[421]
    DIRECTION OUTPUT ;
    USE SIGNAL ;
    PORT
      LAYER M4 ;
        RECT  23.676 89.376 23.76 89.4 ;
    END
  END dst_d[421]
  PIN dst_d[422]
    DIRECTION OUTPUT ;
    USE SIGNAL ;
    PORT
      LAYER M4 ;
        RECT  23.676 89.616 23.76 89.64 ;
    END
  END dst_d[422]
  PIN dst_d[423]
    DIRECTION OUTPUT ;
    USE SIGNAL ;
    PORT
      LAYER M4 ;
        RECT  23.676 89.808 23.76 89.832 ;
    END
  END dst_d[423]
  PIN dst_d[424]
    DIRECTION OUTPUT ;
    USE SIGNAL ;
    PORT
      LAYER M4 ;
        RECT  23.676 90 23.76 90.024 ;
    END
  END dst_d[424]
  PIN dst_d[425]
    DIRECTION OUTPUT ;
    USE SIGNAL ;
    PORT
      LAYER M4 ;
        RECT  23.676 90.24 23.76 90.264 ;
    END
  END dst_d[425]
  PIN dst_d[426]
    DIRECTION OUTPUT ;
    USE SIGNAL ;
    PORT
      LAYER M4 ;
        RECT  23.676 90.432 23.76 90.456 ;
    END
  END dst_d[426]
  PIN dst_d[427]
    DIRECTION OUTPUT ;
    USE SIGNAL ;
    PORT
      LAYER M4 ;
        RECT  23.676 90.624 23.76 90.648 ;
    END
  END dst_d[427]
  PIN dst_d[428]
    DIRECTION OUTPUT ;
    USE SIGNAL ;
    PORT
      LAYER M4 ;
        RECT  23.676 90.816 23.76 90.84 ;
    END
  END dst_d[428]
  PIN dst_d[429]
    DIRECTION OUTPUT ;
    USE SIGNAL ;
    PORT
      LAYER M4 ;
        RECT  23.676 91.056 23.76 91.08 ;
    END
  END dst_d[429]
  PIN dst_d[42]
    DIRECTION OUTPUT ;
    USE SIGNAL ;
    PORT
      LAYER M4 ;
        RECT  23.676 11.232 23.76 11.256 ;
    END
  END dst_d[42]
  PIN dst_d[430]
    DIRECTION OUTPUT ;
    USE SIGNAL ;
    PORT
      LAYER M4 ;
        RECT  23.676 91.248 23.76 91.272 ;
    END
  END dst_d[430]
  PIN dst_d[431]
    DIRECTION OUTPUT ;
    USE SIGNAL ;
    PORT
      LAYER M4 ;
        RECT  23.676 91.44 23.76 91.464 ;
    END
  END dst_d[431]
  PIN dst_d[432]
    DIRECTION OUTPUT ;
    USE SIGNAL ;
    PORT
      LAYER M4 ;
        RECT  23.676 91.68 23.76 91.704 ;
    END
  END dst_d[432]
  PIN dst_d[433]
    DIRECTION OUTPUT ;
    USE SIGNAL ;
    PORT
      LAYER M4 ;
        RECT  23.676 91.872 23.76 91.896 ;
    END
  END dst_d[433]
  PIN dst_d[434]
    DIRECTION OUTPUT ;
    USE SIGNAL ;
    PORT
      LAYER M4 ;
        RECT  23.676 92.064 23.76 92.088 ;
    END
  END dst_d[434]
  PIN dst_d[435]
    DIRECTION OUTPUT ;
    USE SIGNAL ;
    PORT
      LAYER M4 ;
        RECT  23.676 92.304 23.76 92.328 ;
    END
  END dst_d[435]
  PIN dst_d[436]
    DIRECTION OUTPUT ;
    USE SIGNAL ;
    PORT
      LAYER M4 ;
        RECT  23.676 92.496 23.76 92.52 ;
    END
  END dst_d[436]
  PIN dst_d[437]
    DIRECTION OUTPUT ;
    USE SIGNAL ;
    PORT
      LAYER M4 ;
        RECT  23.676 92.688 23.76 92.712 ;
    END
  END dst_d[437]
  PIN dst_d[438]
    DIRECTION OUTPUT ;
    USE SIGNAL ;
    PORT
      LAYER M4 ;
        RECT  23.676 92.88 23.76 92.904 ;
    END
  END dst_d[438]
  PIN dst_d[439]
    DIRECTION OUTPUT ;
    USE SIGNAL ;
    PORT
      LAYER M4 ;
        RECT  23.676 93.12 23.76 93.144 ;
    END
  END dst_d[439]
  PIN dst_d[43]
    DIRECTION OUTPUT ;
    USE SIGNAL ;
    PORT
      LAYER M4 ;
        RECT  23.676 11.472 23.76 11.496 ;
    END
  END dst_d[43]
  PIN dst_d[440]
    DIRECTION OUTPUT ;
    USE SIGNAL ;
    PORT
      LAYER M4 ;
        RECT  23.676 93.312 23.76 93.336 ;
    END
  END dst_d[440]
  PIN dst_d[441]
    DIRECTION OUTPUT ;
    USE SIGNAL ;
    PORT
      LAYER M4 ;
        RECT  23.676 93.504 23.76 93.528 ;
    END
  END dst_d[441]
  PIN dst_d[442]
    DIRECTION OUTPUT ;
    USE SIGNAL ;
    PORT
      LAYER M4 ;
        RECT  23.676 93.744 23.76 93.768 ;
    END
  END dst_d[442]
  PIN dst_d[443]
    DIRECTION OUTPUT ;
    USE SIGNAL ;
    PORT
      LAYER M4 ;
        RECT  23.676 93.936 23.76 93.96 ;
    END
  END dst_d[443]
  PIN dst_d[444]
    DIRECTION OUTPUT ;
    USE SIGNAL ;
    PORT
      LAYER M4 ;
        RECT  23.676 94.128 23.76 94.152 ;
    END
  END dst_d[444]
  PIN dst_d[445]
    DIRECTION OUTPUT ;
    USE SIGNAL ;
    PORT
      LAYER M4 ;
        RECT  23.676 94.32 23.76 94.344 ;
    END
  END dst_d[445]
  PIN dst_d[446]
    DIRECTION OUTPUT ;
    USE SIGNAL ;
    PORT
      LAYER M4 ;
        RECT  23.676 94.56 23.76 94.584 ;
    END
  END dst_d[446]
  PIN dst_d[447]
    DIRECTION OUTPUT ;
    USE SIGNAL ;
    PORT
      LAYER M4 ;
        RECT  23.676 94.752 23.76 94.776 ;
    END
  END dst_d[447]
  PIN dst_d[44]
    DIRECTION OUTPUT ;
    USE SIGNAL ;
    PORT
      LAYER M4 ;
        RECT  23.676 11.664 23.76 11.688 ;
    END
  END dst_d[44]
  PIN dst_d[45]
    DIRECTION OUTPUT ;
    USE SIGNAL ;
    PORT
      LAYER M4 ;
        RECT  23.676 11.856 23.76 11.88 ;
    END
  END dst_d[45]
  PIN dst_d[46]
    DIRECTION OUTPUT ;
    USE SIGNAL ;
    PORT
      LAYER M4 ;
        RECT  23.676 12.096 23.76 12.12 ;
    END
  END dst_d[46]
  PIN dst_d[47]
    DIRECTION OUTPUT ;
    USE SIGNAL ;
    PORT
      LAYER M4 ;
        RECT  23.676 12.288 23.76 12.312 ;
    END
  END dst_d[47]
  PIN dst_d[48]
    DIRECTION OUTPUT ;
    USE SIGNAL ;
    PORT
      LAYER M4 ;
        RECT  23.676 12.48 23.76 12.504 ;
    END
  END dst_d[48]
  PIN dst_d[49]
    DIRECTION OUTPUT ;
    USE SIGNAL ;
    PORT
      LAYER M4 ;
        RECT  23.676 12.672 23.76 12.696 ;
    END
  END dst_d[49]
  PIN dst_d[4]
    DIRECTION OUTPUT ;
    USE SIGNAL ;
    PORT
      LAYER M4 ;
        RECT  23.676 3.408 23.76 3.432 ;
    END
  END dst_d[4]
  PIN dst_d[50]
    DIRECTION OUTPUT ;
    USE SIGNAL ;
    PORT
      LAYER M4 ;
        RECT  23.676 12.912 23.76 12.936 ;
    END
  END dst_d[50]
  PIN dst_d[51]
    DIRECTION OUTPUT ;
    USE SIGNAL ;
    PORT
      LAYER M4 ;
        RECT  23.676 13.104 23.76 13.128 ;
    END
  END dst_d[51]
  PIN dst_d[52]
    DIRECTION OUTPUT ;
    USE SIGNAL ;
    PORT
      LAYER M4 ;
        RECT  23.676 13.296 23.76 13.32 ;
    END
  END dst_d[52]
  PIN dst_d[53]
    DIRECTION OUTPUT ;
    USE SIGNAL ;
    PORT
      LAYER M4 ;
        RECT  23.676 13.536 23.76 13.56 ;
    END
  END dst_d[53]
  PIN dst_d[54]
    DIRECTION OUTPUT ;
    USE SIGNAL ;
    PORT
      LAYER M4 ;
        RECT  23.676 13.728 23.76 13.752 ;
    END
  END dst_d[54]
  PIN dst_d[55]
    DIRECTION OUTPUT ;
    USE SIGNAL ;
    PORT
      LAYER M4 ;
        RECT  23.676 13.92 23.76 13.944 ;
    END
  END dst_d[55]
  PIN dst_d[56]
    DIRECTION OUTPUT ;
    USE SIGNAL ;
    PORT
      LAYER M4 ;
        RECT  23.676 14.16 23.76 14.184 ;
    END
  END dst_d[56]
  PIN dst_d[57]
    DIRECTION OUTPUT ;
    USE SIGNAL ;
    PORT
      LAYER M4 ;
        RECT  23.676 14.352 23.76 14.376 ;
    END
  END dst_d[57]
  PIN dst_d[58]
    DIRECTION OUTPUT ;
    USE SIGNAL ;
    PORT
      LAYER M4 ;
        RECT  23.676 14.544 23.76 14.568 ;
    END
  END dst_d[58]
  PIN dst_d[59]
    DIRECTION OUTPUT ;
    USE SIGNAL ;
    PORT
      LAYER M4 ;
        RECT  23.676 14.736 23.76 14.76 ;
    END
  END dst_d[59]
  PIN dst_d[5]
    DIRECTION OUTPUT ;
    USE SIGNAL ;
    PORT
      LAYER M4 ;
        RECT  23.676 3.6 23.76 3.624 ;
    END
  END dst_d[5]
  PIN dst_d[60]
    DIRECTION OUTPUT ;
    USE SIGNAL ;
    PORT
      LAYER M4 ;
        RECT  23.676 14.976 23.76 15 ;
    END
  END dst_d[60]
  PIN dst_d[61]
    DIRECTION OUTPUT ;
    USE SIGNAL ;
    PORT
      LAYER M4 ;
        RECT  23.676 15.168 23.76 15.192 ;
    END
  END dst_d[61]
  PIN dst_d[62]
    DIRECTION OUTPUT ;
    USE SIGNAL ;
    PORT
      LAYER M4 ;
        RECT  23.676 15.36 23.76 15.384 ;
    END
  END dst_d[62]
  PIN dst_d[63]
    DIRECTION OUTPUT ;
    USE SIGNAL ;
    PORT
      LAYER M4 ;
        RECT  23.676 15.6 23.76 15.624 ;
    END
  END dst_d[63]
  PIN dst_d[64]
    DIRECTION OUTPUT ;
    USE SIGNAL ;
    PORT
      LAYER M4 ;
        RECT  23.676 15.792 23.76 15.816 ;
    END
  END dst_d[64]
  PIN dst_d[65]
    DIRECTION OUTPUT ;
    USE SIGNAL ;
    PORT
      LAYER M4 ;
        RECT  23.676 15.984 23.76 16.008 ;
    END
  END dst_d[65]
  PIN dst_d[66]
    DIRECTION OUTPUT ;
    USE SIGNAL ;
    PORT
      LAYER M4 ;
        RECT  23.676 16.176 23.76 16.2 ;
    END
  END dst_d[66]
  PIN dst_d[67]
    DIRECTION OUTPUT ;
    USE SIGNAL ;
    PORT
      LAYER M4 ;
        RECT  23.676 16.416 23.76 16.44 ;
    END
  END dst_d[67]
  PIN dst_d[68]
    DIRECTION OUTPUT ;
    USE SIGNAL ;
    PORT
      LAYER M4 ;
        RECT  23.676 16.608 23.76 16.632 ;
    END
  END dst_d[68]
  PIN dst_d[69]
    DIRECTION OUTPUT ;
    USE SIGNAL ;
    PORT
      LAYER M4 ;
        RECT  23.676 16.8 23.76 16.824 ;
    END
  END dst_d[69]
  PIN dst_d[6]
    DIRECTION OUTPUT ;
    USE SIGNAL ;
    PORT
      LAYER M4 ;
        RECT  23.676 3.84 23.76 3.864 ;
    END
  END dst_d[6]
  PIN dst_d[70]
    DIRECTION OUTPUT ;
    USE SIGNAL ;
    PORT
      LAYER M4 ;
        RECT  23.676 17.04 23.76 17.064 ;
    END
  END dst_d[70]
  PIN dst_d[71]
    DIRECTION OUTPUT ;
    USE SIGNAL ;
    PORT
      LAYER M4 ;
        RECT  23.676 17.232 23.76 17.256 ;
    END
  END dst_d[71]
  PIN dst_d[72]
    DIRECTION OUTPUT ;
    USE SIGNAL ;
    PORT
      LAYER M4 ;
        RECT  23.676 17.424 23.76 17.448 ;
    END
  END dst_d[72]
  PIN dst_d[73]
    DIRECTION OUTPUT ;
    USE SIGNAL ;
    PORT
      LAYER M4 ;
        RECT  23.676 17.664 23.76 17.688 ;
    END
  END dst_d[73]
  PIN dst_d[74]
    DIRECTION OUTPUT ;
    USE SIGNAL ;
    PORT
      LAYER M4 ;
        RECT  23.676 17.856 23.76 17.88 ;
    END
  END dst_d[74]
  PIN dst_d[75]
    DIRECTION OUTPUT ;
    USE SIGNAL ;
    PORT
      LAYER M4 ;
        RECT  23.676 18.048 23.76 18.072 ;
    END
  END dst_d[75]
  PIN dst_d[76]
    DIRECTION OUTPUT ;
    USE SIGNAL ;
    PORT
      LAYER M4 ;
        RECT  23.676 18.24 23.76 18.264 ;
    END
  END dst_d[76]
  PIN dst_d[77]
    DIRECTION OUTPUT ;
    USE SIGNAL ;
    PORT
      LAYER M4 ;
        RECT  23.676 18.48 23.76 18.504 ;
    END
  END dst_d[77]
  PIN dst_d[78]
    DIRECTION OUTPUT ;
    USE SIGNAL ;
    PORT
      LAYER M4 ;
        RECT  23.676 18.672 23.76 18.696 ;
    END
  END dst_d[78]
  PIN dst_d[79]
    DIRECTION OUTPUT ;
    USE SIGNAL ;
    PORT
      LAYER M4 ;
        RECT  23.676 18.864 23.76 18.888 ;
    END
  END dst_d[79]
  PIN dst_d[7]
    DIRECTION OUTPUT ;
    USE SIGNAL ;
    PORT
      LAYER M4 ;
        RECT  23.676 4.032 23.76 4.056 ;
    END
  END dst_d[7]
  PIN dst_d[80]
    DIRECTION OUTPUT ;
    USE SIGNAL ;
    PORT
      LAYER M4 ;
        RECT  23.676 19.104 23.76 19.128 ;
    END
  END dst_d[80]
  PIN dst_d[81]
    DIRECTION OUTPUT ;
    USE SIGNAL ;
    PORT
      LAYER M4 ;
        RECT  23.676 19.296 23.76 19.32 ;
    END
  END dst_d[81]
  PIN dst_d[82]
    DIRECTION OUTPUT ;
    USE SIGNAL ;
    PORT
      LAYER M4 ;
        RECT  23.676 19.488 23.76 19.512 ;
    END
  END dst_d[82]
  PIN dst_d[83]
    DIRECTION OUTPUT ;
    USE SIGNAL ;
    PORT
      LAYER M4 ;
        RECT  23.676 19.728 23.76 19.752 ;
    END
  END dst_d[83]
  PIN dst_d[84]
    DIRECTION OUTPUT ;
    USE SIGNAL ;
    PORT
      LAYER M4 ;
        RECT  23.676 19.92 23.76 19.944 ;
    END
  END dst_d[84]
  PIN dst_d[85]
    DIRECTION OUTPUT ;
    USE SIGNAL ;
    PORT
      LAYER M4 ;
        RECT  23.676 20.112 23.76 20.136 ;
    END
  END dst_d[85]
  PIN dst_d[86]
    DIRECTION OUTPUT ;
    USE SIGNAL ;
    PORT
      LAYER M4 ;
        RECT  23.676 20.304 23.76 20.328 ;
    END
  END dst_d[86]
  PIN dst_d[87]
    DIRECTION OUTPUT ;
    USE SIGNAL ;
    PORT
      LAYER M4 ;
        RECT  23.676 20.544 23.76 20.568 ;
    END
  END dst_d[87]
  PIN dst_d[88]
    DIRECTION OUTPUT ;
    USE SIGNAL ;
    PORT
      LAYER M4 ;
        RECT  23.676 20.736 23.76 20.76 ;
    END
  END dst_d[88]
  PIN dst_d[89]
    DIRECTION OUTPUT ;
    USE SIGNAL ;
    PORT
      LAYER M4 ;
        RECT  23.676 20.928 23.76 20.952 ;
    END
  END dst_d[89]
  PIN dst_d[8]
    DIRECTION OUTPUT ;
    USE SIGNAL ;
    PORT
      LAYER M4 ;
        RECT  23.676 4.224 23.76 4.248 ;
    END
  END dst_d[8]
  PIN dst_d[90]
    DIRECTION OUTPUT ;
    USE SIGNAL ;
    PORT
      LAYER M4 ;
        RECT  23.676 21.168 23.76 21.192 ;
    END
  END dst_d[90]
  PIN dst_d[91]
    DIRECTION OUTPUT ;
    USE SIGNAL ;
    PORT
      LAYER M4 ;
        RECT  23.676 21.36 23.76 21.384 ;
    END
  END dst_d[91]
  PIN dst_d[92]
    DIRECTION OUTPUT ;
    USE SIGNAL ;
    PORT
      LAYER M4 ;
        RECT  23.676 21.552 23.76 21.576 ;
    END
  END dst_d[92]
  PIN dst_d[93]
    DIRECTION OUTPUT ;
    USE SIGNAL ;
    PORT
      LAYER M4 ;
        RECT  23.676 21.744 23.76 21.768 ;
    END
  END dst_d[93]
  PIN dst_d[94]
    DIRECTION OUTPUT ;
    USE SIGNAL ;
    PORT
      LAYER M4 ;
        RECT  23.676 21.984 23.76 22.008 ;
    END
  END dst_d[94]
  PIN dst_d[95]
    DIRECTION OUTPUT ;
    USE SIGNAL ;
    PORT
      LAYER M4 ;
        RECT  23.676 22.176 23.76 22.2 ;
    END
  END dst_d[95]
  PIN dst_d[96]
    DIRECTION OUTPUT ;
    USE SIGNAL ;
    PORT
      LAYER M4 ;
        RECT  23.676 22.368 23.76 22.392 ;
    END
  END dst_d[96]
  PIN dst_d[97]
    DIRECTION OUTPUT ;
    USE SIGNAL ;
    PORT
      LAYER M4 ;
        RECT  23.676 22.608 23.76 22.632 ;
    END
  END dst_d[97]
  PIN dst_d[98]
    DIRECTION OUTPUT ;
    USE SIGNAL ;
    PORT
      LAYER M4 ;
        RECT  23.676 22.8 23.76 22.824 ;
    END
  END dst_d[98]
  PIN dst_d[99]
    DIRECTION OUTPUT ;
    USE SIGNAL ;
    PORT
      LAYER M4 ;
        RECT  23.676 22.992 23.76 23.016 ;
    END
  END dst_d[99]
  PIN dst_d[9]
    DIRECTION OUTPUT ;
    USE SIGNAL ;
    PORT
      LAYER M4 ;
        RECT  23.676 4.464 23.76 4.488 ;
    END
  END dst_d[9]
  PIN dst_v[0]
    DIRECTION OUTPUT ;
    USE SIGNAL ;
    PORT
      LAYER M4 ;
        RECT  23.676 95.184 23.76 95.208 ;
    END
  END dst_v[0]
  PIN dst_v[10]
    DIRECTION OUTPUT ;
    USE SIGNAL ;
    PORT
      LAYER M4 ;
        RECT  23.676 97.872 23.76 97.896 ;
    END
  END dst_v[10]
  PIN dst_v[11]
    DIRECTION OUTPUT ;
    USE SIGNAL ;
    PORT
      LAYER M4 ;
        RECT  23.676 98.16 23.76 98.184 ;
    END
  END dst_v[11]
  PIN dst_v[12]
    DIRECTION OUTPUT ;
    USE SIGNAL ;
    PORT
      LAYER M4 ;
        RECT  23.676 98.4 23.76 98.424 ;
    END
  END dst_v[12]
  PIN dst_v[13]
    DIRECTION OUTPUT ;
    USE SIGNAL ;
    PORT
      LAYER M4 ;
        RECT  23.676 98.688 23.76 98.712 ;
    END
  END dst_v[13]
  PIN dst_v[1]
    DIRECTION OUTPUT ;
    USE SIGNAL ;
    PORT
      LAYER M4 ;
        RECT  23.676 95.472 23.76 95.496 ;
    END
  END dst_v[1]
  PIN dst_v[2]
    DIRECTION OUTPUT ;
    USE SIGNAL ;
    PORT
      LAYER M4 ;
        RECT  23.676 95.712 23.76 95.736 ;
    END
  END dst_v[2]
  PIN dst_v[3]
    DIRECTION OUTPUT ;
    USE SIGNAL ;
    PORT
      LAYER M4 ;
        RECT  23.676 96 23.76 96.024 ;
    END
  END dst_v[3]
  PIN dst_v[4]
    DIRECTION OUTPUT ;
    USE SIGNAL ;
    PORT
      LAYER M4 ;
        RECT  23.676 96.24 23.76 96.264 ;
    END
  END dst_v[4]
  PIN dst_v[5]
    DIRECTION OUTPUT ;
    USE SIGNAL ;
    PORT
      LAYER M4 ;
        RECT  23.676 96.528 23.76 96.552 ;
    END
  END dst_v[5]
  PIN dst_v[6]
    DIRECTION OUTPUT ;
    USE SIGNAL ;
    PORT
      LAYER M4 ;
        RECT  23.676 96.816 23.76 96.84 ;
    END
  END dst_v[6]
  PIN dst_v[7]
    DIRECTION OUTPUT ;
    USE SIGNAL ;
    PORT
      LAYER M4 ;
        RECT  23.676 97.056 23.76 97.08 ;
    END
  END dst_v[7]
  PIN dst_v[8]
    DIRECTION OUTPUT ;
    USE SIGNAL ;
    PORT
      LAYER M4 ;
        RECT  23.676 97.344 23.76 97.368 ;
    END
  END dst_v[8]
  PIN dst_v[9]
    DIRECTION OUTPUT ;
    USE SIGNAL ;
    PORT
      LAYER M4 ;
        RECT  23.676 97.584 23.76 97.608 ;
    END
  END dst_v[9]
  PIN rst_n
    DIRECTION INPUT ;
    USE SIGNAL ;
    PORT
      LAYER M5 ;
        RECT  22.272 101.436 22.296 101.52 ;
    END
  END rst_n
  PIN select_fault
    DIRECTION OUTPUT ;
    USE SIGNAL ;
    PORT
      LAYER M5 ;
        RECT  22.8 101.436 22.824 101.52 ;
    END
  END select_fault
  PIN sink_select[0]
    DIRECTION INPUT ;
    USE SIGNAL ;
    PORT
      LAYER M5 ;
        RECT  6.576 101.436 6.6 101.52 ;
    END
  END sink_select[0]
  PIN sink_select[10]
    DIRECTION INPUT ;
    USE SIGNAL ;
    PORT
      LAYER M5 ;
        RECT  9.264 101.436 9.288 101.52 ;
    END
  END sink_select[10]
  PIN sink_select[11]
    DIRECTION INPUT ;
    USE SIGNAL ;
    PORT
      LAYER M5 ;
        RECT  9.504 101.436 9.528 101.52 ;
    END
  END sink_select[11]
  PIN sink_select[12]
    DIRECTION INPUT ;
    USE SIGNAL ;
    PORT
      LAYER M5 ;
        RECT  9.792 101.436 9.816 101.52 ;
    END
  END sink_select[12]
  PIN sink_select[13]
    DIRECTION INPUT ;
    USE SIGNAL ;
    PORT
      LAYER M5 ;
        RECT  10.032 101.436 10.056 101.52 ;
    END
  END sink_select[13]
  PIN sink_select[14]
    DIRECTION INPUT ;
    USE SIGNAL ;
    PORT
      LAYER M5 ;
        RECT  10.32 101.436 10.344 101.52 ;
    END
  END sink_select[14]
  PIN sink_select[15]
    DIRECTION INPUT ;
    USE SIGNAL ;
    PORT
      LAYER M5 ;
        RECT  10.608 101.436 10.632 101.52 ;
    END
  END sink_select[15]
  PIN sink_select[16]
    DIRECTION INPUT ;
    USE SIGNAL ;
    PORT
      LAYER M5 ;
        RECT  10.848 101.436 10.872 101.52 ;
    END
  END sink_select[16]
  PIN sink_select[17]
    DIRECTION INPUT ;
    USE SIGNAL ;
    PORT
      LAYER M5 ;
        RECT  11.136 101.436 11.16 101.52 ;
    END
  END sink_select[17]
  PIN sink_select[18]
    DIRECTION INPUT ;
    USE SIGNAL ;
    PORT
      LAYER M5 ;
        RECT  11.376 101.436 11.4 101.52 ;
    END
  END sink_select[18]
  PIN sink_select[19]
    DIRECTION INPUT ;
    USE SIGNAL ;
    PORT
      LAYER M5 ;
        RECT  11.664 101.436 11.688 101.52 ;
    END
  END sink_select[19]
  PIN sink_select[1]
    DIRECTION INPUT ;
    USE SIGNAL ;
    PORT
      LAYER M5 ;
        RECT  6.864 101.436 6.888 101.52 ;
    END
  END sink_select[1]
  PIN sink_select[20]
    DIRECTION INPUT ;
    USE SIGNAL ;
    PORT
      LAYER M5 ;
        RECT  11.952 101.436 11.976 101.52 ;
    END
  END sink_select[20]
  PIN sink_select[21]
    DIRECTION INPUT ;
    USE SIGNAL ;
    PORT
      LAYER M5 ;
        RECT  12.192 101.436 12.216 101.52 ;
    END
  END sink_select[21]
  PIN sink_select[22]
    DIRECTION INPUT ;
    USE SIGNAL ;
    PORT
      LAYER M5 ;
        RECT  12.48 101.436 12.504 101.52 ;
    END
  END sink_select[22]
  PIN sink_select[23]
    DIRECTION INPUT ;
    USE SIGNAL ;
    PORT
      LAYER M5 ;
        RECT  12.72 101.436 12.744 101.52 ;
    END
  END sink_select[23]
  PIN sink_select[24]
    DIRECTION INPUT ;
    USE SIGNAL ;
    PORT
      LAYER M5 ;
        RECT  13.008 101.436 13.032 101.52 ;
    END
  END sink_select[24]
  PIN sink_select[25]
    DIRECTION INPUT ;
    USE SIGNAL ;
    PORT
      LAYER M5 ;
        RECT  13.248 101.436 13.272 101.52 ;
    END
  END sink_select[25]
  PIN sink_select[26]
    DIRECTION INPUT ;
    USE SIGNAL ;
    PORT
      LAYER M5 ;
        RECT  13.536 101.436 13.56 101.52 ;
    END
  END sink_select[26]
  PIN sink_select[27]
    DIRECTION INPUT ;
    USE SIGNAL ;
    PORT
      LAYER M5 ;
        RECT  13.824 101.436 13.848 101.52 ;
    END
  END sink_select[27]
  PIN sink_select[28]
    DIRECTION INPUT ;
    USE SIGNAL ;
    PORT
      LAYER M5 ;
        RECT  14.064 101.436 14.088 101.52 ;
    END
  END sink_select[28]
  PIN sink_select[29]
    DIRECTION INPUT ;
    USE SIGNAL ;
    PORT
      LAYER M5 ;
        RECT  14.352 101.436 14.376 101.52 ;
    END
  END sink_select[29]
  PIN sink_select[2]
    DIRECTION INPUT ;
    USE SIGNAL ;
    PORT
      LAYER M5 ;
        RECT  7.104 101.436 7.128 101.52 ;
    END
  END sink_select[2]
  PIN sink_select[30]
    DIRECTION INPUT ;
    USE SIGNAL ;
    PORT
      LAYER M5 ;
        RECT  14.592 101.436 14.616 101.52 ;
    END
  END sink_select[30]
  PIN sink_select[31]
    DIRECTION INPUT ;
    USE SIGNAL ;
    PORT
      LAYER M5 ;
        RECT  14.88 101.436 14.904 101.52 ;
    END
  END sink_select[31]
  PIN sink_select[32]
    DIRECTION INPUT ;
    USE SIGNAL ;
    PORT
      LAYER M5 ;
        RECT  15.12 101.436 15.144 101.52 ;
    END
  END sink_select[32]
  PIN sink_select[33]
    DIRECTION INPUT ;
    USE SIGNAL ;
    PORT
      LAYER M5 ;
        RECT  15.408 101.436 15.432 101.52 ;
    END
  END sink_select[33]
  PIN sink_select[34]
    DIRECTION INPUT ;
    USE SIGNAL ;
    PORT
      LAYER M5 ;
        RECT  15.696 101.436 15.72 101.52 ;
    END
  END sink_select[34]
  PIN sink_select[35]
    DIRECTION INPUT ;
    USE SIGNAL ;
    PORT
      LAYER M5 ;
        RECT  15.936 101.436 15.96 101.52 ;
    END
  END sink_select[35]
  PIN sink_select[36]
    DIRECTION INPUT ;
    USE SIGNAL ;
    PORT
      LAYER M5 ;
        RECT  16.224 101.436 16.248 101.52 ;
    END
  END sink_select[36]
  PIN sink_select[37]
    DIRECTION INPUT ;
    USE SIGNAL ;
    PORT
      LAYER M5 ;
        RECT  16.464 101.436 16.488 101.52 ;
    END
  END sink_select[37]
  PIN sink_select[38]
    DIRECTION INPUT ;
    USE SIGNAL ;
    PORT
      LAYER M5 ;
        RECT  16.752 101.436 16.776 101.52 ;
    END
  END sink_select[38]
  PIN sink_select[39]
    DIRECTION INPUT ;
    USE SIGNAL ;
    PORT
      LAYER M5 ;
        RECT  17.04 101.436 17.064 101.52 ;
    END
  END sink_select[39]
  PIN sink_select[3]
    DIRECTION INPUT ;
    USE SIGNAL ;
    PORT
      LAYER M5 ;
        RECT  7.392 101.436 7.416 101.52 ;
    END
  END sink_select[3]
  PIN sink_select[40]
    DIRECTION INPUT ;
    USE SIGNAL ;
    PORT
      LAYER M5 ;
        RECT  17.28 101.436 17.304 101.52 ;
    END
  END sink_select[40]
  PIN sink_select[41]
    DIRECTION INPUT ;
    USE SIGNAL ;
    PORT
      LAYER M5 ;
        RECT  17.568 101.436 17.592 101.52 ;
    END
  END sink_select[41]
  PIN sink_select[42]
    DIRECTION INPUT ;
    USE SIGNAL ;
    PORT
      LAYER M5 ;
        RECT  17.808 101.436 17.832 101.52 ;
    END
  END sink_select[42]
  PIN sink_select[43]
    DIRECTION INPUT ;
    USE SIGNAL ;
    PORT
      LAYER M5 ;
        RECT  18.096 101.436 18.12 101.52 ;
    END
  END sink_select[43]
  PIN sink_select[44]
    DIRECTION INPUT ;
    USE SIGNAL ;
    PORT
      LAYER M5 ;
        RECT  18.336 101.436 18.36 101.52 ;
    END
  END sink_select[44]
  PIN sink_select[45]
    DIRECTION INPUT ;
    USE SIGNAL ;
    PORT
      LAYER M5 ;
        RECT  18.624 101.436 18.648 101.52 ;
    END
  END sink_select[45]
  PIN sink_select[46]
    DIRECTION INPUT ;
    USE SIGNAL ;
    PORT
      LAYER M5 ;
        RECT  18.912 101.436 18.936 101.52 ;
    END
  END sink_select[46]
  PIN sink_select[47]
    DIRECTION INPUT ;
    USE SIGNAL ;
    PORT
      LAYER M5 ;
        RECT  19.152 101.436 19.176 101.52 ;
    END
  END sink_select[47]
  PIN sink_select[48]
    DIRECTION INPUT ;
    USE SIGNAL ;
    PORT
      LAYER M5 ;
        RECT  19.44 101.436 19.464 101.52 ;
    END
  END sink_select[48]
  PIN sink_select[49]
    DIRECTION INPUT ;
    USE SIGNAL ;
    PORT
      LAYER M5 ;
        RECT  19.68 101.436 19.704 101.52 ;
    END
  END sink_select[49]
  PIN sink_select[4]
    DIRECTION INPUT ;
    USE SIGNAL ;
    PORT
      LAYER M5 ;
        RECT  7.632 101.436 7.656 101.52 ;
    END
  END sink_select[4]
  PIN sink_select[50]
    DIRECTION INPUT ;
    USE SIGNAL ;
    PORT
      LAYER M5 ;
        RECT  19.968 101.436 19.992 101.52 ;
    END
  END sink_select[50]
  PIN sink_select[51]
    DIRECTION INPUT ;
    USE SIGNAL ;
    PORT
      LAYER M5 ;
        RECT  20.256 101.436 20.28 101.52 ;
    END
  END sink_select[51]
  PIN sink_select[52]
    DIRECTION INPUT ;
    USE SIGNAL ;
    PORT
      LAYER M5 ;
        RECT  20.496 101.436 20.52 101.52 ;
    END
  END sink_select[52]
  PIN sink_select[53]
    DIRECTION INPUT ;
    USE SIGNAL ;
    PORT
      LAYER M5 ;
        RECT  20.784 101.436 20.808 101.52 ;
    END
  END sink_select[53]
  PIN sink_select[54]
    DIRECTION INPUT ;
    USE SIGNAL ;
    PORT
      LAYER M5 ;
        RECT  21.024 101.436 21.048 101.52 ;
    END
  END sink_select[54]
  PIN sink_select[55]
    DIRECTION INPUT ;
    USE SIGNAL ;
    PORT
      LAYER M5 ;
        RECT  21.312 101.436 21.336 101.52 ;
    END
  END sink_select[55]
  PIN sink_select[5]
    DIRECTION INPUT ;
    USE SIGNAL ;
    PORT
      LAYER M5 ;
        RECT  7.92 101.436 7.944 101.52 ;
    END
  END sink_select[5]
  PIN sink_select[6]
    DIRECTION INPUT ;
    USE SIGNAL ;
    PORT
      LAYER M5 ;
        RECT  8.16 101.436 8.184 101.52 ;
    END
  END sink_select[6]
  PIN sink_select[7]
    DIRECTION INPUT ;
    USE SIGNAL ;
    PORT
      LAYER M5 ;
        RECT  8.448 101.436 8.472 101.52 ;
    END
  END sink_select[7]
  PIN sink_select[8]
    DIRECTION INPUT ;
    USE SIGNAL ;
    PORT
      LAYER M5 ;
        RECT  8.736 101.436 8.76 101.52 ;
    END
  END sink_select[8]
  PIN sink_select[9]
    DIRECTION INPUT ;
    USE SIGNAL ;
    PORT
      LAYER M5 ;
        RECT  8.976 101.436 9 101.52 ;
    END
  END sink_select[9]
  PIN sink_slot[0]
    DIRECTION INPUT ;
    USE SIGNAL ;
    PORT
      LAYER M5 ;
        RECT  2.64 101.436 2.664 101.52 ;
    END
  END sink_slot[0]
  PIN sink_slot[10]
    DIRECTION INPUT ;
    USE SIGNAL ;
    PORT
      LAYER M5 ;
        RECT  5.28 101.436 5.304 101.52 ;
    END
  END sink_slot[10]
  PIN sink_slot[11]
    DIRECTION INPUT ;
    USE SIGNAL ;
    PORT
      LAYER M5 ;
        RECT  5.568 101.436 5.592 101.52 ;
    END
  END sink_slot[11]
  PIN sink_slot[12]
    DIRECTION INPUT ;
    USE SIGNAL ;
    PORT
      LAYER M5 ;
        RECT  5.856 101.436 5.88 101.52 ;
    END
  END sink_slot[12]
  PIN sink_slot[13]
    DIRECTION INPUT ;
    USE SIGNAL ;
    PORT
      LAYER M5 ;
        RECT  6.096 101.436 6.12 101.52 ;
    END
  END sink_slot[13]
  PIN sink_slot[1]
    DIRECTION INPUT ;
    USE SIGNAL ;
    PORT
      LAYER M5 ;
        RECT  2.88 101.436 2.904 101.52 ;
    END
  END sink_slot[1]
  PIN sink_slot[2]
    DIRECTION INPUT ;
    USE SIGNAL ;
    PORT
      LAYER M5 ;
        RECT  3.168 101.436 3.192 101.52 ;
    END
  END sink_slot[2]
  PIN sink_slot[3]
    DIRECTION INPUT ;
    USE SIGNAL ;
    PORT
      LAYER M5 ;
        RECT  3.408 101.436 3.432 101.52 ;
    END
  END sink_slot[3]
  PIN sink_slot[4]
    DIRECTION INPUT ;
    USE SIGNAL ;
    PORT
      LAYER M5 ;
        RECT  3.696 101.436 3.72 101.52 ;
    END
  END sink_slot[4]
  PIN sink_slot[5]
    DIRECTION INPUT ;
    USE SIGNAL ;
    PORT
      LAYER M5 ;
        RECT  3.984 101.436 4.008 101.52 ;
    END
  END sink_slot[5]
  PIN sink_slot[6]
    DIRECTION INPUT ;
    USE SIGNAL ;
    PORT
      LAYER M5 ;
        RECT  4.224 101.436 4.248 101.52 ;
    END
  END sink_slot[6]
  PIN sink_slot[7]
    DIRECTION INPUT ;
    USE SIGNAL ;
    PORT
      LAYER M5 ;
        RECT  4.512 101.436 4.536 101.52 ;
    END
  END sink_slot[7]
  PIN sink_slot[8]
    DIRECTION INPUT ;
    USE SIGNAL ;
    PORT
      LAYER M5 ;
        RECT  4.752 101.436 4.776 101.52 ;
    END
  END sink_slot[8]
  PIN sink_slot[9]
    DIRECTION INPUT ;
    USE SIGNAL ;
    PORT
      LAYER M5 ;
        RECT  5.04 101.436 5.064 101.52 ;
    END
  END sink_slot[9]
  PIN unavailable_fault
    DIRECTION OUTPUT ;
    USE SIGNAL ;
    PORT
      LAYER M5 ;
        RECT  23.28 101.436 23.304 101.52 ;
    END
  END unavailable_fault
  PIN VDD
    DIRECTION INOUT ;
    USE POWER ;
    PORT
      LAYER M5 ;
        RECT  18.792 2.151 18.912 99.369 ;
        RECT  13.392 2.151 13.512 99.369 ;
        RECT  7.992 2.151 8.112 99.369 ;
        RECT  2.592 2.151 2.712 99.369 ;
    END
  END VDD
  PIN VSS
    DIRECTION INOUT ;
    USE GROUND ;
    PORT
      LAYER M5 ;
        RECT  18.6 2.137 18.72 99.383 ;
        RECT  13.2 2.137 13.32 99.383 ;
        RECT  7.8 2.137 7.92 99.383 ;
        RECT  2.4 2.137 2.52 99.383 ;
    END
  END VSS
  OBS
    LAYER RVTN ;
     RECT  2.16 2.16 21.6 2.295 ;
     RECT  2.16 2.565 21.6 2.835 ;
     RECT  2.16 3.105 21.6 3.375 ;
     RECT  2.16 3.645 21.6 3.915 ;
     RECT  2.16 4.185 21.6 4.455 ;
     RECT  2.16 4.725 21.6 4.995 ;
     RECT  2.16 5.265 21.6 5.535 ;
     RECT  2.16 5.805 21.6 6.075 ;
     RECT  2.16 6.345 21.6 6.615 ;
     RECT  2.16 6.885 21.6 7.155 ;
     RECT  2.16 7.425 21.6 7.695 ;
     RECT  2.16 7.965 21.6 8.235 ;
     RECT  2.16 8.505 21.6 8.775 ;
     RECT  2.16 9.045 21.6 9.315 ;
     RECT  2.16 9.585 21.6 9.855 ;
     RECT  2.16 10.125 21.6 10.395 ;
     RECT  2.16 10.665 21.6 10.935 ;
     RECT  2.16 11.205 21.6 11.475 ;
     RECT  2.16 11.745 21.6 12.015 ;
     RECT  2.16 12.285 21.6 12.555 ;
     RECT  2.16 12.825 21.6 13.095 ;
     RECT  2.16 13.365 21.6 13.635 ;
     RECT  2.16 13.905 21.6 14.175 ;
     RECT  2.16 14.445 21.6 14.715 ;
     RECT  2.16 14.985 21.6 15.255 ;
     RECT  2.16 15.525 21.6 15.795 ;
     RECT  2.16 16.065 21.6 16.335 ;
     RECT  2.16 16.605 21.6 16.875 ;
     RECT  2.16 17.145 21.6 17.415 ;
     RECT  2.16 17.685 21.6 17.955 ;
     RECT  2.16 18.225 21.6 18.495 ;
     RECT  2.16 18.765 21.6 19.035 ;
     RECT  2.16 19.305 21.6 19.575 ;
     RECT  2.16 19.845 21.6 20.115 ;
     RECT  2.16 20.385 21.6 20.655 ;
     RECT  2.16 20.925 21.6 21.195 ;
     RECT  2.16 21.465 21.6 21.735 ;
     RECT  2.16 22.005 21.6 22.275 ;
     RECT  2.16 22.545 21.6 22.815 ;
     RECT  2.16 23.085 21.6 23.355 ;
     RECT  2.16 23.625 21.6 23.895 ;
     RECT  2.16 24.165 21.6 24.435 ;
     RECT  2.16 24.705 21.6 24.975 ;
     RECT  2.16 25.245 21.6 25.515 ;
     RECT  2.16 25.785 21.6 26.055 ;
     RECT  2.16 26.325 21.6 26.595 ;
     RECT  2.16 26.865 21.6 27.135 ;
     RECT  2.16 27.405 21.6 27.675 ;
     RECT  2.16 27.945 21.6 28.215 ;
     RECT  2.16 28.485 21.6 28.755 ;
     RECT  2.16 29.025 21.6 29.295 ;
     RECT  2.16 29.565 21.6 29.835 ;
     RECT  2.16 30.105 21.6 30.375 ;
     RECT  2.16 30.645 21.6 30.915 ;
     RECT  2.16 31.185 21.6 31.455 ;
     RECT  2.16 31.725 21.6 31.995 ;
     RECT  2.16 32.265 21.6 32.535 ;
     RECT  2.16 32.805 21.6 33.075 ;
     RECT  2.16 33.345 21.6 33.615 ;
     RECT  2.16 33.885 21.6 34.155 ;
     RECT  2.16 34.425 21.6 34.695 ;
     RECT  2.16 34.965 21.6 35.235 ;
     RECT  2.16 35.505 21.6 35.775 ;
     RECT  2.16 36.045 21.6 36.315 ;
     RECT  2.16 36.585 21.6 36.855 ;
     RECT  2.16 37.125 21.6 37.395 ;
     RECT  2.16 37.665 21.6 37.935 ;
     RECT  2.16 38.205 21.6 38.475 ;
     RECT  2.16 38.745 21.6 39.015 ;
     RECT  2.16 39.285 21.6 39.555 ;
     RECT  2.16 39.825 21.6 40.095 ;
     RECT  2.16 40.365 21.6 40.635 ;
     RECT  2.16 40.905 21.6 41.175 ;
     RECT  2.16 41.445 21.6 41.715 ;
     RECT  2.16 41.985 21.6 42.255 ;
     RECT  2.16 42.525 21.6 42.795 ;
     RECT  2.16 43.065 21.6 43.335 ;
     RECT  2.16 43.605 21.6 43.875 ;
     RECT  2.16 44.145 21.6 44.415 ;
     RECT  2.16 44.685 21.6 44.955 ;
     RECT  2.16 45.225 21.6 45.495 ;
     RECT  2.16 45.765 21.6 46.035 ;
     RECT  2.16 46.305 21.6 46.575 ;
     RECT  2.16 46.845 21.6 47.115 ;
     RECT  2.16 47.385 21.6 47.655 ;
     RECT  2.16 47.925 21.6 48.195 ;
     RECT  2.16 48.465 21.6 48.735 ;
     RECT  2.16 49.005 21.6 49.275 ;
     RECT  2.16 49.545 21.6 49.815 ;
     RECT  2.16 50.085 21.6 50.355 ;
     RECT  2.16 50.625 21.6 50.895 ;
     RECT  2.16 51.165 21.6 51.435 ;
     RECT  2.16 51.705 21.6 51.975 ;
     RECT  2.16 52.245 21.6 52.515 ;
     RECT  2.16 52.785 21.6 53.055 ;
     RECT  2.16 53.325 21.6 53.595 ;
     RECT  2.16 53.865 21.6 54.135 ;
     RECT  2.16 54.405 21.6 54.675 ;
     RECT  2.16 54.945 21.6 55.215 ;
     RECT  2.16 55.485 21.6 55.755 ;
     RECT  2.16 56.025 21.6 56.295 ;
     RECT  2.16 56.565 21.6 56.835 ;
     RECT  2.16 57.105 21.6 57.375 ;
     RECT  2.16 57.645 21.6 57.915 ;
     RECT  2.16 58.185 21.6 58.455 ;
     RECT  2.16 58.725 21.6 58.995 ;
     RECT  2.16 59.265 21.6 59.535 ;
     RECT  2.16 59.805 21.6 60.075 ;
     RECT  2.16 60.345 21.6 60.615 ;
     RECT  2.16 60.885 21.6 61.155 ;
     RECT  2.16 61.425 21.6 61.695 ;
     RECT  2.16 61.965 21.6 62.235 ;
     RECT  2.16 62.505 21.6 62.775 ;
     RECT  2.16 63.045 21.6 63.315 ;
     RECT  2.16 63.585 21.6 63.855 ;
     RECT  2.16 64.125 21.6 64.395 ;
     RECT  2.16 64.665 21.6 64.935 ;
     RECT  2.16 65.205 21.6 65.475 ;
     RECT  2.16 65.745 21.6 66.015 ;
     RECT  2.16 66.285 21.6 66.555 ;
     RECT  2.16 66.825 21.6 67.095 ;
     RECT  2.16 67.365 21.6 67.635 ;
     RECT  2.16 67.905 21.6 68.175 ;
     RECT  2.16 68.445 21.6 68.715 ;
     RECT  2.16 68.985 21.6 69.255 ;
     RECT  2.16 69.525 21.6 69.795 ;
     RECT  2.16 70.065 21.6 70.335 ;
     RECT  2.16 70.605 21.6 70.875 ;
     RECT  2.16 71.145 21.6 71.415 ;
     RECT  2.16 71.685 21.6 71.955 ;
     RECT  2.16 72.225 21.6 72.495 ;
     RECT  2.16 72.765 21.6 73.035 ;
     RECT  2.16 73.305 21.6 73.575 ;
     RECT  2.16 73.845 21.6 74.115 ;
     RECT  2.16 74.385 21.6 74.655 ;
     RECT  2.16 74.925 21.6 75.195 ;
     RECT  2.16 75.465 21.6 75.735 ;
     RECT  2.16 76.005 21.6 76.275 ;
     RECT  2.16 76.545 21.6 76.815 ;
     RECT  2.16 77.085 21.6 77.355 ;
     RECT  2.16 77.625 21.6 77.895 ;
     RECT  2.16 78.165 21.6 78.435 ;
     RECT  2.16 78.705 21.6 78.975 ;
     RECT  2.16 79.245 21.6 79.515 ;
     RECT  2.16 79.785 21.6 80.055 ;
     RECT  2.16 80.325 21.6 80.595 ;
     RECT  2.16 80.865 21.6 81.135 ;
     RECT  2.16 81.405 21.6 81.675 ;
     RECT  2.16 81.945 21.6 82.215 ;
     RECT  2.16 82.485 21.6 82.755 ;
     RECT  2.16 83.025 21.6 83.295 ;
     RECT  2.16 83.565 21.6 83.835 ;
     RECT  2.16 84.105 21.6 84.375 ;
     RECT  2.16 84.645 21.6 84.915 ;
     RECT  2.16 85.185 21.6 85.455 ;
     RECT  2.16 85.725 21.6 85.995 ;
     RECT  2.16 86.265 21.6 86.535 ;
     RECT  2.16 86.805 21.6 87.075 ;
     RECT  2.16 87.345 21.6 87.615 ;
     RECT  2.16 87.885 21.6 88.155 ;
     RECT  2.16 88.425 21.6 88.695 ;
     RECT  2.16 88.965 21.6 89.235 ;
     RECT  2.16 89.505 21.6 89.775 ;
     RECT  2.16 90.045 21.6 90.315 ;
     RECT  2.16 90.585 21.6 90.855 ;
     RECT  2.16 91.125 21.6 91.395 ;
     RECT  2.16 91.665 21.6 91.935 ;
     RECT  2.16 92.205 21.6 92.475 ;
     RECT  2.16 92.745 21.6 93.015 ;
     RECT  2.16 93.285 21.6 93.555 ;
     RECT  2.16 93.825 21.6 94.095 ;
     RECT  2.16 94.365 21.6 94.635 ;
     RECT  2.16 94.905 21.6 95.175 ;
     RECT  2.16 95.445 21.6 95.715 ;
     RECT  2.16 95.985 21.6 96.255 ;
     RECT  2.16 96.525 21.6 96.795 ;
     RECT  2.16 97.065 21.6 97.335 ;
     RECT  2.16 97.605 21.6 97.875 ;
     RECT  2.16 98.145 21.6 98.415 ;
     RECT  2.16 98.685 21.6 98.955 ;
     RECT  2.16 99.225 21.6 99.36 ;
    LAYER RVTP ;
     RECT  2.16 2.295 21.6 2.565 ;
     RECT  2.16 2.835 21.6 3.105 ;
     RECT  2.16 3.375 21.6 3.645 ;
     RECT  2.16 3.915 21.6 4.185 ;
     RECT  2.16 4.455 21.6 4.725 ;
     RECT  2.16 4.995 21.6 5.265 ;
     RECT  2.16 5.535 21.6 5.805 ;
     RECT  2.16 6.075 21.6 6.345 ;
     RECT  2.16 6.615 21.6 6.885 ;
     RECT  2.16 7.155 21.6 7.425 ;
     RECT  2.16 7.695 21.6 7.965 ;
     RECT  2.16 8.235 21.6 8.505 ;
     RECT  2.16 8.775 21.6 9.045 ;
     RECT  2.16 9.315 21.6 9.585 ;
     RECT  2.16 9.855 21.6 10.125 ;
     RECT  2.16 10.395 21.6 10.665 ;
     RECT  2.16 10.935 21.6 11.205 ;
     RECT  2.16 11.475 21.6 11.745 ;
     RECT  2.16 12.015 21.6 12.285 ;
     RECT  2.16 12.555 21.6 12.825 ;
     RECT  2.16 13.095 21.6 13.365 ;
     RECT  2.16 13.635 21.6 13.905 ;
     RECT  2.16 14.175 21.6 14.445 ;
     RECT  2.16 14.715 21.6 14.985 ;
     RECT  2.16 15.255 21.6 15.525 ;
     RECT  2.16 15.795 21.6 16.065 ;
     RECT  2.16 16.335 21.6 16.605 ;
     RECT  2.16 16.875 21.6 17.145 ;
     RECT  2.16 17.415 21.6 17.685 ;
     RECT  2.16 17.955 21.6 18.225 ;
     RECT  2.16 18.495 21.6 18.765 ;
     RECT  2.16 19.035 21.6 19.305 ;
     RECT  2.16 19.575 21.6 19.845 ;
     RECT  2.16 20.115 21.6 20.385 ;
     RECT  2.16 20.655 21.6 20.925 ;
     RECT  2.16 21.195 21.6 21.465 ;
     RECT  2.16 21.735 21.6 22.005 ;
     RECT  2.16 22.275 21.6 22.545 ;
     RECT  2.16 22.815 21.6 23.085 ;
     RECT  2.16 23.355 21.6 23.625 ;
     RECT  2.16 23.895 21.6 24.165 ;
     RECT  2.16 24.435 21.6 24.705 ;
     RECT  2.16 24.975 21.6 25.245 ;
     RECT  2.16 25.515 21.6 25.785 ;
     RECT  2.16 26.055 21.6 26.325 ;
     RECT  2.16 26.595 21.6 26.865 ;
     RECT  2.16 27.135 21.6 27.405 ;
     RECT  2.16 27.675 21.6 27.945 ;
     RECT  2.16 28.215 21.6 28.485 ;
     RECT  2.16 28.755 21.6 29.025 ;
     RECT  2.16 29.295 21.6 29.565 ;
     RECT  2.16 29.835 21.6 30.105 ;
     RECT  2.16 30.375 21.6 30.645 ;
     RECT  2.16 30.915 21.6 31.185 ;
     RECT  2.16 31.455 21.6 31.725 ;
     RECT  2.16 31.995 21.6 32.265 ;
     RECT  2.16 32.535 21.6 32.805 ;
     RECT  2.16 33.075 21.6 33.345 ;
     RECT  2.16 33.615 21.6 33.885 ;
     RECT  2.16 34.155 21.6 34.425 ;
     RECT  2.16 34.695 21.6 34.965 ;
     RECT  2.16 35.235 21.6 35.505 ;
     RECT  2.16 35.775 21.6 36.045 ;
     RECT  2.16 36.315 21.6 36.585 ;
     RECT  2.16 36.855 21.6 37.125 ;
     RECT  2.16 37.395 21.6 37.665 ;
     RECT  2.16 37.935 21.6 38.205 ;
     RECT  2.16 38.475 21.6 38.745 ;
     RECT  2.16 39.015 21.6 39.285 ;
     RECT  2.16 39.555 21.6 39.825 ;
     RECT  2.16 40.095 21.6 40.365 ;
     RECT  2.16 40.635 21.6 40.905 ;
     RECT  2.16 41.175 21.6 41.445 ;
     RECT  2.16 41.715 21.6 41.985 ;
     RECT  2.16 42.255 21.6 42.525 ;
     RECT  2.16 42.795 21.6 43.065 ;
     RECT  2.16 43.335 21.6 43.605 ;
     RECT  2.16 43.875 21.6 44.145 ;
     RECT  2.16 44.415 21.6 44.685 ;
     RECT  2.16 44.955 21.6 45.225 ;
     RECT  2.16 45.495 21.6 45.765 ;
     RECT  2.16 46.035 21.6 46.305 ;
     RECT  2.16 46.575 21.6 46.845 ;
     RECT  2.16 47.115 21.6 47.385 ;
     RECT  2.16 47.655 21.6 47.925 ;
     RECT  2.16 48.195 21.6 48.465 ;
     RECT  2.16 48.735 21.6 49.005 ;
     RECT  2.16 49.275 21.6 49.545 ;
     RECT  2.16 49.815 21.6 50.085 ;
     RECT  2.16 50.355 21.6 50.625 ;
     RECT  2.16 50.895 21.6 51.165 ;
     RECT  2.16 51.435 21.6 51.705 ;
     RECT  2.16 51.975 21.6 52.245 ;
     RECT  2.16 52.515 21.6 52.785 ;
     RECT  2.16 53.055 21.6 53.325 ;
     RECT  2.16 53.595 21.6 53.865 ;
     RECT  2.16 54.135 21.6 54.405 ;
     RECT  2.16 54.675 21.6 54.945 ;
     RECT  2.16 55.215 21.6 55.485 ;
     RECT  2.16 55.755 21.6 56.025 ;
     RECT  2.16 56.295 21.6 56.565 ;
     RECT  2.16 56.835 21.6 57.105 ;
     RECT  2.16 57.375 21.6 57.645 ;
     RECT  2.16 57.915 21.6 58.185 ;
     RECT  2.16 58.455 21.6 58.725 ;
     RECT  2.16 58.995 21.6 59.265 ;
     RECT  2.16 59.535 21.6 59.805 ;
     RECT  2.16 60.075 21.6 60.345 ;
     RECT  2.16 60.615 21.6 60.885 ;
     RECT  2.16 61.155 21.6 61.425 ;
     RECT  2.16 61.695 21.6 61.965 ;
     RECT  2.16 62.235 21.6 62.505 ;
     RECT  2.16 62.775 21.6 63.045 ;
     RECT  2.16 63.315 21.6 63.585 ;
     RECT  2.16 63.855 21.6 64.125 ;
     RECT  2.16 64.395 21.6 64.665 ;
     RECT  2.16 64.935 21.6 65.205 ;
     RECT  2.16 65.475 21.6 65.745 ;
     RECT  2.16 66.015 21.6 66.285 ;
     RECT  2.16 66.555 21.6 66.825 ;
     RECT  2.16 67.095 21.6 67.365 ;
     RECT  2.16 67.635 21.6 67.905 ;
     RECT  2.16 68.175 21.6 68.445 ;
     RECT  2.16 68.715 21.6 68.985 ;
     RECT  2.16 69.255 21.6 69.525 ;
     RECT  2.16 69.795 21.6 70.065 ;
     RECT  2.16 70.335 21.6 70.605 ;
     RECT  2.16 70.875 21.6 71.145 ;
     RECT  2.16 71.415 21.6 71.685 ;
     RECT  2.16 71.955 21.6 72.225 ;
     RECT  2.16 72.495 21.6 72.765 ;
     RECT  2.16 73.035 21.6 73.305 ;
     RECT  2.16 73.575 21.6 73.845 ;
     RECT  2.16 74.115 21.6 74.385 ;
     RECT  2.16 74.655 21.6 74.925 ;
     RECT  2.16 75.195 21.6 75.465 ;
     RECT  2.16 75.735 21.6 76.005 ;
     RECT  2.16 76.275 21.6 76.545 ;
     RECT  2.16 76.815 21.6 77.085 ;
     RECT  2.16 77.355 21.6 77.625 ;
     RECT  2.16 77.895 21.6 78.165 ;
     RECT  2.16 78.435 21.6 78.705 ;
     RECT  2.16 78.975 21.6 79.245 ;
     RECT  2.16 79.515 21.6 79.785 ;
     RECT  2.16 80.055 21.6 80.325 ;
     RECT  2.16 80.595 21.6 80.865 ;
     RECT  2.16 81.135 21.6 81.405 ;
     RECT  2.16 81.675 21.6 81.945 ;
     RECT  2.16 82.215 21.6 82.485 ;
     RECT  2.16 82.755 21.6 83.025 ;
     RECT  2.16 83.295 21.6 83.565 ;
     RECT  2.16 83.835 21.6 84.105 ;
     RECT  2.16 84.375 21.6 84.645 ;
     RECT  2.16 84.915 21.6 85.185 ;
     RECT  2.16 85.455 21.6 85.725 ;
     RECT  2.16 85.995 21.6 86.265 ;
     RECT  2.16 86.535 21.6 86.805 ;
     RECT  2.16 87.075 21.6 87.345 ;
     RECT  2.16 87.615 21.6 87.885 ;
     RECT  2.16 88.155 21.6 88.425 ;
     RECT  2.16 88.695 21.6 88.965 ;
     RECT  2.16 89.235 21.6 89.505 ;
     RECT  2.16 89.775 21.6 90.045 ;
     RECT  2.16 90.315 21.6 90.585 ;
     RECT  2.16 90.855 21.6 91.125 ;
     RECT  2.16 91.395 21.6 91.665 ;
     RECT  2.16 91.935 21.6 92.205 ;
     RECT  2.16 92.475 21.6 92.745 ;
     RECT  2.16 93.015 21.6 93.285 ;
     RECT  2.16 93.555 21.6 93.825 ;
     RECT  2.16 94.095 21.6 94.365 ;
     RECT  2.16 94.635 21.6 94.905 ;
     RECT  2.16 95.175 21.6 95.445 ;
     RECT  2.16 95.715 21.6 95.985 ;
     RECT  2.16 96.255 21.6 96.525 ;
     RECT  2.16 96.795 21.6 97.065 ;
     RECT  2.16 97.335 21.6 97.605 ;
     RECT  2.16 97.875 21.6 98.145 ;
     RECT  2.16 98.415 21.6 98.685 ;
     RECT  2.16 98.955 21.6 99.225 ;
    LAYER M1 ;
     RECT  2.16 2.151 21.6 99.369 ;
    LAYER M2 ;
     RECT  0.103 41.76 0.139 41.778 ;
     RECT  0.067 85.536 0.167 85.554 ;
     RECT  0.103 43.272 0.175 43.83 ;
     RECT  0.103 5.544 2.16 5.994 ;
     RECT  0.535 8.442 2.16 8.46 ;
     RECT  0.103 13.302 2.16 13.968 ;
     RECT  0.103 15.3 2.16 15.318 ;
     RECT  0.103 16.38 2.16 18.558 ;
     RECT  0.139 41.652 2.16 41.778 ;
     RECT  0.175 42.57 2.16 43.83 ;
     RECT  0.103 45 2.16 45.558 ;
     RECT  0.103 47.16 2.16 48.258 ;
     RECT  0.103 58.5 2.16 58.518 ;
     RECT  0.031 73.512 2.16 73.53 ;
     RECT  0.067 78.48 2.16 78.498 ;
     RECT  0.031 91.638 2.16 91.656 ;
     RECT  1.975 93.024 2.16 93.042 ;
     RECT  0.103 94.572 2.16 94.59 ;
     RECT  0.103 96.84 2.16 96.858 ;
     RECT  2.16 2.151 21.163 99.369 ;
     RECT  21.163 2.106 21.6 99.369 ;
     RECT  21.6 3.852 21.659 65.232 ;
     RECT  21.6 66.096 21.659 78.264 ;
     RECT  21.6 79.056 21.659 99.288 ;
     RECT  21.659 3.852 21.695 62.604 ;
     RECT  21.659 89.136 21.695 99.288 ;
     RECT  21.695 45.846 21.731 62.604 ;
     RECT  21.659 76.554 21.731 78.264 ;
     RECT  21.695 89.136 21.731 93.474 ;
     RECT  21.695 7.866 21.767 32.094 ;
     RECT  21.731 45.846 21.767 48.834 ;
     RECT  21.659 63.594 21.767 65.232 ;
     RECT  21.659 66.096 21.767 75.798 ;
     RECT  21.659 79.056 21.767 88.344 ;
     RECT  21.731 89.136 21.767 91.584 ;
     RECT  21.767 20.286 21.803 32.094 ;
     RECT  21.695 32.886 21.803 44.784 ;
     RECT  21.767 66.096 21.803 69.354 ;
     RECT  21.767 71.658 21.803 72.324 ;
     RECT  21.767 79.056 21.803 81.504 ;
     RECT  21.767 7.866 21.839 19.224 ;
     RECT  21.767 73.278 21.839 75.798 ;
     RECT  21.767 82.296 21.839 88.344 ;
     RECT  21.731 49.896 21.875 62.604 ;
     RECT  21.767 63.594 21.875 64.962 ;
     RECT  21.803 71.658 21.875 72.054 ;
     RECT  21.731 92.448 21.875 93.474 ;
     RECT  21.803 32.886 21.911 44.514 ;
     RECT  21.875 49.896 21.911 50.886 ;
     RECT  21.875 51.984 21.911 57.294 ;
     RECT  21.839 9.756 21.947 19.224 ;
     RECT  21.911 32.886 21.947 36.036 ;
     RECT  21.767 46.008 21.947 48.834 ;
     RECT  21.911 50.328 21.947 50.886 ;
     RECT  21.839 73.35 21.947 75.798 ;
     RECT  21.767 89.136 21.947 90.306 ;
     RECT  21.911 36.828 22.199 44.514 ;
     RECT  21.803 66.726 22.199 69.354 ;
     RECT  21.695 94.806 22.199 98.604 ;
     RECT  21.695 3.852 22.235 7.11 ;
     RECT  21.947 10.836 22.235 15.354 ;
     RECT  21.803 20.286 22.235 24.264 ;
     RECT  21.803 25.056 22.235 32.094 ;
     RECT  21.947 32.886 22.235 35.874 ;
     RECT  22.199 36.936 22.235 42.894 ;
     RECT  22.199 43.686 22.235 44.514 ;
     RECT  21.947 50.706 22.235 50.886 ;
     RECT  21.911 52.056 22.235 57.294 ;
     RECT  21.875 58.428 22.235 62.604 ;
     RECT  22.199 66.726 22.235 66.744 ;
     RECT  21.767 70.506 22.235 70.902 ;
     RECT  21.875 71.73 22.235 72.054 ;
     RECT  21.947 73.35 22.235 74.844 ;
     RECT  21.947 89.136 22.235 90.036 ;
     RECT  22.199 94.806 22.235 95.634 ;
     RECT  22.199 96.426 22.235 98.604 ;
     RECT  21.947 9.756 22.271 9.954 ;
     RECT  22.235 12.456 22.271 14.004 ;
     RECT  21.947 16.308 22.271 19.224 ;
     RECT  22.235 23.166 22.271 24.192 ;
     RECT  22.235 31.194 22.271 32.094 ;
     RECT  22.235 32.976 22.271 35.874 ;
     RECT  22.235 38.826 22.271 42.012 ;
     RECT  22.235 50.706 22.271 50.724 ;
     RECT  22.235 52.056 22.271 55.944 ;
     RECT  22.235 58.428 22.271 62.262 ;
     RECT  21.875 63.594 22.271 64.854 ;
     RECT  22.235 73.386 22.271 74.844 ;
     RECT  21.731 76.896 22.271 78.264 ;
     RECT  22.235 98.226 22.271 98.604 ;
     RECT  21.803 79.056 22.415 81.324 ;
     RECT  22.235 3.852 22.739 6.714 ;
     RECT  22.271 40.266 22.739 42.012 ;
     RECT  21.839 82.296 22.739 85.644 ;
     RECT  22.739 4.662 22.775 6.714 ;
     RECT  22.271 12.456 22.775 13.824 ;
     RECT  22.235 20.286 22.775 20.574 ;
     RECT  22.235 25.056 22.775 30.438 ;
     RECT  22.271 32.976 22.775 34.074 ;
     RECT  22.739 40.266 22.775 40.554 ;
     RECT  22.235 44.19 22.775 44.514 ;
     RECT  22.271 58.428 22.775 59.994 ;
     RECT  22.199 67.608 22.775 69.354 ;
     RECT  22.415 79.416 22.775 81.324 ;
     RECT  21.839 86.436 22.775 88.344 ;
     RECT  21.6 2.106 22.811 3.024 ;
     RECT  22.739 3.852 22.811 3.87 ;
     RECT  22.775 4.662 22.811 4.68 ;
     RECT  22.775 5.436 22.811 6.714 ;
     RECT  21.839 7.866 22.811 8.964 ;
     RECT  22.271 9.756 22.811 9.774 ;
     RECT  22.235 10.836 22.811 11.664 ;
     RECT  22.775 12.456 22.811 12.924 ;
     RECT  22.775 13.806 22.811 13.824 ;
     RECT  22.235 14.994 22.811 15.012 ;
     RECT  22.271 16.308 22.811 16.434 ;
     RECT  22.271 17.496 22.811 19.224 ;
     RECT  22.775 20.556 22.811 20.574 ;
     RECT  22.235 21.474 22.811 22.194 ;
     RECT  22.775 26.334 22.811 30.438 ;
     RECT  22.271 31.536 22.811 32.094 ;
     RECT  22.775 32.976 22.811 32.994 ;
     RECT  22.775 34.056 22.811 34.074 ;
     RECT  22.235 37.404 22.811 38.034 ;
     RECT  22.271 38.826 22.811 39.474 ;
     RECT  22.775 40.266 22.811 40.284 ;
     RECT  22.739 41.616 22.811 42.012 ;
     RECT  22.775 44.226 22.811 44.514 ;
     RECT  21.947 46.08 22.811 48.834 ;
     RECT  22.271 52.056 22.811 54.324 ;
     RECT  22.271 55.188 22.811 55.944 ;
     RECT  22.235 57.276 22.811 57.294 ;
     RECT  22.775 58.428 22.811 59.724 ;
     RECT  22.271 61.056 22.811 62.262 ;
     RECT  22.271 64.296 22.811 64.854 ;
     RECT  22.775 67.608 22.811 68.364 ;
     RECT  22.235 70.686 22.811 70.902 ;
     RECT  22.271 74.826 22.811 74.844 ;
     RECT  21.947 75.744 22.811 75.798 ;
     RECT  22.775 79.416 22.811 80.964 ;
     RECT  22.739 83.07 22.811 85.644 ;
     RECT  22.775 86.436 22.811 87.534 ;
     RECT  22.775 88.326 22.811 88.344 ;
     RECT  22.235 89.136 22.811 89.838 ;
     RECT  21.767 91.206 22.811 91.584 ;
     RECT  21.875 92.916 22.811 93.474 ;
     RECT  22.235 95.076 22.811 95.634 ;
     RECT  22.235 97.236 22.811 97.254 ;
     RECT  22.811 2.106 22.847 2.286 ;
     RECT  22.811 5.814 22.847 6.714 ;
     RECT  22.811 8.28 22.847 8.298 ;
     RECT  22.811 11.178 22.847 11.574 ;
     RECT  22.811 12.636 22.847 12.924 ;
     RECT  22.811 17.496 22.847 17.514 ;
     RECT  22.271 24.174 22.847 24.192 ;
     RECT  22.775 25.056 22.847 25.578 ;
     RECT  22.811 27.18 22.847 28.242 ;
     RECT  22.271 35.244 22.847 35.604 ;
     RECT  22.235 42.876 22.847 42.894 ;
     RECT  22.811 46.89 22.847 46.908 ;
     RECT  22.811 52.056 22.847 53.586 ;
     RECT  22.811 62.244 22.847 62.262 ;
     RECT  22.811 64.296 22.847 64.314 ;
     RECT  22.811 83.07 22.847 84.294 ;
     RECT  22.811 85.464 22.847 85.482 ;
     RECT  22.811 86.886 22.847 86.904 ;
     RECT  22.847 2.268 22.883 2.286 ;
     RECT  22.811 18.504 22.883 18.594 ;
     RECT  22.811 38.826 22.883 39.042 ;
     RECT  22.883 38.952 22.919 39.042 ;
     RECT  22.811 16.344 23.639 16.434 ;
     RECT  22.811 29.376 23.639 29.556 ;
     RECT  22.847 35.514 23.639 35.604 ;
     RECT  22.811 37.404 23.639 37.764 ;
     RECT  22.271 73.386 23.639 73.872 ;
     RECT  22.271 77.094 23.639 78.264 ;
     RECT  22.811 80.064 23.639 80.622 ;
     RECT  22.847 5.814 23.675 5.832 ;
     RECT  22.847 6.696 23.675 6.714 ;
     RECT  22.847 12.906 23.675 12.924 ;
     RECT  23.639 16.344 23.675 16.362 ;
     RECT  22.883 18.576 23.675 18.594 ;
     RECT  22.811 21.474 23.675 21.492 ;
     RECT  22.271 23.166 23.675 23.184 ;
     RECT  22.811 26.334 23.675 26.352 ;
     RECT  22.847 28.224 23.675 28.242 ;
     RECT  23.639 29.376 23.675 29.394 ;
     RECT  22.811 30.42 23.675 30.438 ;
     RECT  22.811 31.536 23.675 31.554 ;
     RECT  23.639 35.514 23.675 35.532 ;
     RECT  23.639 37.404 23.675 37.422 ;
     RECT  22.811 41.796 23.675 41.814 ;
     RECT  22.811 46.08 23.675 46.098 ;
     RECT  22.811 47.97 23.675 47.988 ;
     RECT  22.811 55.188 23.675 55.206 ;
     RECT  22.811 58.428 23.675 59.022 ;
     RECT  22.811 67.608 23.675 67.626 ;
     RECT  22.775 69.336 23.675 69.354 ;
     RECT  22.811 70.686 23.675 70.704 ;
     RECT  22.235 71.73 23.675 71.748 ;
     RECT  23.639 73.854 23.675 73.872 ;
     RECT  22.811 75.744 23.675 75.762 ;
     RECT  23.639 77.094 23.675 77.652 ;
     RECT  23.639 80.136 23.675 80.622 ;
     RECT  22.739 82.296 23.675 82.314 ;
     RECT  22.847 83.106 23.675 84.132 ;
     RECT  22.811 91.206 23.675 91.224 ;
     RECT  22.811 93.06 23.675 93.078 ;
     RECT  22.271 98.226 23.675 98.244 ;
    LAYER M3 ;
     RECT  21.168 2.101 21.186 2.191 ;
     RECT  18.615 2.143 18.705 2.227 ;
     RECT  20.844 2.191 21.186 2.263 ;
     RECT  22.824 2.101 22.842 2.263 ;
     RECT  20.844 2.263 21.258 2.335 ;
     RECT  20.16 2.335 21.258 2.371 ;
     RECT  2.415 2.143 2.505 2.413 ;
     RECT  7.815 2.143 7.905 2.413 ;
     RECT  13.215 2.143 13.305 2.413 ;
     RECT  18.576 2.227 18.705 2.413 ;
     RECT  22.824 2.263 22.878 2.461 ;
     RECT  18.576 2.413 18.897 2.731 ;
     RECT  19.8 2.371 21.258 2.731 ;
     RECT  0.108 2.683 0.126 2.813 ;
     RECT  22.248 2.461 22.878 2.813 ;
     RECT  7.815 2.413 8.097 3.001 ;
     RECT  17.64 2.263 17.658 3.001 ;
     RECT  22.248 2.813 22.806 3.053 ;
     RECT  3.42 2.779 3.438 3.065 ;
     RECT  5.436 3.019 5.454 3.181 ;
     RECT  17.604 3.001 17.658 3.181 ;
     RECT  18.576 2.731 21.402 3.181 ;
     RECT  5.436 3.181 5.634 3.299 ;
     RECT  10.836 3.181 10.854 3.307 ;
     RECT  11.592 3.271 11.61 3.307 ;
     RECT  5.436 3.299 5.454 3.335 ;
     RECT  2.415 2.413 2.697 3.403 ;
     RECT  10.836 3.307 11.61 3.407 ;
     RECT  7.815 3.001 8.37 3.451 ;
     RECT  15.948 3.181 15.966 3.451 ;
     RECT  16.704 3.271 16.722 3.451 ;
     RECT  17.604 3.181 21.402 3.451 ;
     RECT  16.704 3.451 21.402 3.479 ;
     RECT  16.704 3.479 17.73 3.569 ;
     RECT  11.592 3.407 11.61 3.605 ;
     RECT  22.248 3.053 22.77 3.629 ;
     RECT  9.9 3.379 9.918 3.649 ;
     RECT  15.588 3.451 15.966 3.649 ;
     RECT  16.704 3.569 16.722 3.649 ;
     RECT  13.215 2.413 13.497 3.721 ;
     RECT  15.588 3.649 16.722 3.721 ;
     RECT  15.084 3.721 16.722 3.749 ;
     RECT  2.304 3.403 2.697 3.787 ;
     RECT  2.268 3.787 2.697 3.811 ;
     RECT  22.716 3.629 22.77 3.835 ;
     RECT  7.815 3.451 8.586 3.875 ;
     RECT  22.716 3.835 22.806 3.875 ;
     RECT  2.268 3.811 2.79 3.931 ;
     RECT  9.9 3.649 9.99 3.931 ;
     RECT  12.024 3.685 12.042 3.965 ;
     RECT  17.604 3.569 17.73 3.983 ;
     RECT  2.268 3.931 3.186 3.991 ;
     RECT  9.684 3.931 9.99 3.991 ;
     RECT  18.468 3.479 21.402 4.027 ;
     RECT  2.268 3.991 3.33 4.145 ;
     RECT  9.684 3.991 10.674 4.145 ;
     RECT  4.248 3.811 4.266 4.189 ;
     RECT  9.684 4.145 9.99 4.189 ;
     RECT  18.468 4.027 21.834 4.217 ;
     RECT  13.104 3.721 13.497 4.261 ;
     RECT  17.64 3.983 17.73 4.261 ;
     RECT  18.468 4.217 21.726 4.261 ;
     RECT  3.528 4.189 4.266 4.289 ;
     RECT  22.716 3.875 22.734 4.289 ;
     RECT  15.084 3.749 15.966 4.507 ;
     RECT  16.704 3.749 16.722 4.507 ;
     RECT  17.64 4.261 21.726 4.523 ;
     RECT  10.836 4.351 10.854 4.685 ;
     RECT  19.728 4.523 21.726 4.757 ;
     RECT  3.96 4.289 4.266 4.801 ;
     RECT  13.104 4.261 13.95 4.801 ;
     RECT  15.084 4.507 16.722 4.801 ;
     RECT  19.728 4.757 21.294 4.919 ;
     RECT  12.672 4.801 13.95 4.927 ;
     RECT  14.832 4.801 16.722 4.955 ;
     RECT  9.396 4.189 9.99 4.963 ;
     RECT  5.148 4.123 5.166 5.071 ;
     RECT  22.788 4.648 22.806 5.071 ;
     RECT  15.084 4.955 16.722 5.131 ;
     RECT  17.64 4.523 18.897 5.131 ;
     RECT  22.752 5.071 22.806 5.467 ;
     RECT  20.16 4.919 21.294 5.531 ;
     RECT  12.06 4.927 13.95 5.575 ;
     RECT  11.7 5.575 13.95 5.603 ;
     RECT  2.304 4.145 2.697 5.611 ;
     RECT  5.148 5.071 5.706 5.611 ;
     RECT  20.16 5.531 20.754 5.701 ;
     RECT  22.212 5.467 22.806 5.729 ;
     RECT  2.304 5.611 2.862 5.765 ;
     RECT  3.96 4.801 4.374 5.809 ;
     RECT  7.815 3.875 8.097 5.809 ;
     RECT  23.652 5.659 23.67 5.837 ;
     RECT  15.084 5.131 18.897 5.845 ;
     RECT  19.656 5.701 20.754 5.845 ;
     RECT  15.084 5.845 20.754 5.873 ;
     RECT  3.888 5.809 4.374 5.909 ;
     RECT  3.96 5.909 4.374 5.995 ;
     RECT  0.108 4.843 0.126 5.999 ;
     RECT  17.64 5.873 20.754 5.999 ;
     RECT  7.308 5.809 8.097 6.007 ;
     RECT  8.964 4.963 9.99 6.007 ;
     RECT  3.96 5.995 4.41 6.029 ;
     RECT  15.084 5.873 16.722 6.037 ;
     RECT  4.068 6.029 4.41 6.151 ;
     RECT  5.148 5.611 6.03 6.151 ;
     RECT  7.308 6.007 9.99 6.241 ;
     RECT  13.104 5.603 13.95 6.241 ;
     RECT  14.76 6.037 16.722 6.241 ;
     RECT  4.068 6.151 6.03 6.269 ;
     RECT  4.068 6.269 4.41 6.305 ;
     RECT  5.22 6.269 6.03 6.305 ;
     RECT  22.788 5.729 22.806 6.349 ;
     RECT  19.764 5.999 20.754 6.385 ;
     RECT  21.708 5.899 21.762 6.385 ;
     RECT  19.764 6.385 21.762 6.719 ;
     RECT  22.788 6.349 22.842 6.749 ;
     RECT  7.308 6.241 10.422 6.781 ;
     RECT  11.7 5.603 12.078 6.781 ;
     RECT  13.104 6.241 16.722 6.781 ;
     RECT  17.64 5.999 18.897 6.781 ;
     RECT  13.104 6.781 18.897 6.817 ;
     RECT  19.764 6.719 21.474 6.817 ;
     RECT  6.804 6.781 10.422 6.845 ;
     RECT  23.652 6.691 23.67 6.941 ;
     RECT  22.788 6.749 22.806 7.087 ;
     RECT  22.212 7.087 22.806 7.133 ;
     RECT  0.108 7.051 0.126 7.181 ;
     RECT  4.104 6.305 4.41 7.231 ;
     RECT  5.256 6.305 6.03 7.231 ;
     RECT  4.104 7.231 6.03 7.321 ;
     RECT  11.268 6.781 12.078 7.321 ;
     RECT  13.104 6.817 21.474 7.321 ;
     RECT  11.268 7.321 21.474 7.349 ;
     RECT  11.268 7.349 16.65 7.385 ;
     RECT  6.804 6.845 9.99 7.529 ;
     RECT  17.424 7.349 21.474 7.531 ;
     RECT  2.304 5.765 2.79 7.771 ;
     RECT  3.816 7.321 6.03 7.771 ;
     RECT  23.652 7.963 23.67 8.093 ;
     RECT  2.304 7.771 6.03 8.195 ;
     RECT  17.424 7.531 21.69 8.195 ;
     RECT  22.788 7.133 22.806 8.275 ;
     RECT  11.7 7.385 16.65 8.303 ;
     RECT  4.248 8.195 6.03 8.311 ;
     RECT  17.568 8.195 21.69 8.347 ;
     RECT  4.248 8.311 6.174 8.437 ;
     RECT  7.2 7.529 9.99 8.437 ;
     RECT  4.248 8.437 9.99 8.473 ;
     RECT  10.908 8.401 10.926 8.473 ;
     RECT  17.568 8.347 21.87 8.501 ;
     RECT  4.248 8.473 10.926 8.509 ;
     RECT  11.7 8.303 12.078 8.509 ;
     RECT  4.248 8.509 12.078 8.537 ;
     RECT  22.788 8.275 22.842 8.621 ;
     RECT  0.54 8.437 0.558 8.957 ;
     RECT  12.852 8.303 16.65 8.971 ;
     RECT  17.568 8.501 21.834 8.971 ;
     RECT  4.248 8.537 6.03 9.391 ;
     RECT  6.804 8.537 12.078 9.391 ;
     RECT  4.248 9.391 12.078 9.451 ;
     RECT  12.852 8.971 21.834 9.595 ;
     RECT  2.304 8.195 2.934 9.661 ;
     RECT  2.304 9.661 3.222 9.895 ;
     RECT  4.212 9.451 12.078 9.895 ;
     RECT  12.852 9.595 21.942 9.931 ;
     RECT  22.788 8.621 22.806 9.931 ;
     RECT  12.852 9.931 22.806 10.253 ;
     RECT  12.852 10.253 21.942 10.391 ;
     RECT  2.304 9.895 12.078 10.471 ;
     RECT  12.852 10.391 21.474 10.471 ;
     RECT  2.304 10.471 21.474 10.625 ;
     RECT  22.788 10.253 22.806 10.651 ;
     RECT  2.304 10.625 2.697 11.371 ;
     RECT  3.42 10.625 21.474 11.371 ;
     RECT  2.304 11.371 21.474 11.399 ;
     RECT  2.304 11.399 4.23 11.405 ;
     RECT  22.788 10.651 22.842 11.467 ;
     RECT  2.304 11.405 4.122 11.693 ;
     RECT  22.212 11.467 22.842 11.693 ;
     RECT  4.968 11.399 21.474 11.749 ;
     RECT  22.212 11.693 22.806 11.749 ;
     RECT  4.968 11.749 22.806 11.885 ;
     RECT  2.304 11.693 3.942 12.475 ;
     RECT  4.968 11.885 21.294 12.475 ;
     RECT  22.212 11.885 22.806 12.509 ;
     RECT  22.824 12.631 22.842 12.701 ;
     RECT  2.304 12.475 21.294 12.829 ;
     RECT  23.652 12.283 23.67 12.929 ;
     RECT  2.304 12.829 21.654 13.291 ;
     RECT  2.304 13.291 22.23 13.397 ;
     RECT  19.656 13.397 22.23 13.603 ;
     RECT  19.656 13.603 22.77 13.723 ;
     RECT  19.656 13.723 22.806 13.829 ;
     RECT  2.304 13.397 18.897 13.865 ;
     RECT  3.78 13.865 18.897 13.973 ;
     RECT  2.304 13.865 2.754 14.009 ;
     RECT  2.304 14.009 2.697 14.135 ;
     RECT  19.656 13.829 22.77 14.189 ;
     RECT  5.04 13.973 18.897 14.251 ;
     RECT  19.656 14.189 22.266 14.251 ;
     RECT  3.78 13.973 3.978 14.587 ;
     RECT  5.04 14.251 22.266 14.971 ;
     RECT  5.04 14.971 22.806 15.017 ;
     RECT  2.376 14.135 2.697 15.025 ;
     RECT  5.04 15.017 22.23 15.025 ;
     RECT  3.6 14.587 3.978 15.061 ;
     RECT  4.824 15.025 22.23 15.061 ;
     RECT  2.304 15.025 2.79 15.331 ;
     RECT  3.6 15.061 22.23 15.331 ;
     RECT  2.304 15.331 22.23 15.389 ;
     RECT  0.108 13.297 0.126 15.533 ;
     RECT  2.304 15.389 21.942 16.061 ;
     RECT  23.652 15.979 23.67 16.171 ;
     RECT  23.616 16.171 23.67 16.367 ;
     RECT  23.616 16.367 23.634 16.439 ;
     RECT  22.788 16.303 22.806 16.637 ;
     RECT  2.304 16.061 21.654 16.879 ;
     RECT  2.304 16.879 21.762 16.951 ;
     RECT  2.304 16.951 22.266 17.021 ;
     RECT  2.415 17.021 22.266 17.456 ;
     RECT  0.108 16.375 0.126 17.617 ;
     RECT  2.415 17.456 21.69 17.645 ;
     RECT  3.816 17.645 21.69 17.681 ;
     RECT  22.824 17.491 22.842 17.693 ;
     RECT  5.076 17.681 21.69 17.885 ;
     RECT  0.108 17.617 0.162 18.125 ;
     RECT  3.816 17.681 3.834 18.419 ;
     RECT  22.788 18.193 22.806 18.475 ;
     RECT  22.248 18.475 22.806 18.499 ;
     RECT  5.076 17.885 21.33 18.535 ;
     RECT  23.652 18.043 23.67 18.599 ;
     RECT  4.068 18.535 21.33 18.667 ;
     RECT  22.248 18.499 22.878 18.667 ;
     RECT  4.068 18.667 22.878 18.761 ;
     RECT  0.108 18.125 0.126 18.845 ;
     RECT  22.212 18.761 22.878 18.893 ;
     RECT  2.415 17.645 2.697 19.075 ;
     RECT  4.068 18.761 21.366 19.085 ;
     RECT  22.212 18.893 22.806 19.133 ;
     RECT  2.415 19.075 3.186 19.147 ;
     RECT  4.068 19.085 4.914 19.229 ;
     RECT  2.304 19.147 3.186 19.345 ;
     RECT  4.068 19.229 4.59 19.409 ;
     RECT  5.976 19.085 21.366 19.483 ;
     RECT  2.304 19.345 3.33 19.499 ;
     RECT  4.068 19.409 4.266 19.651 ;
     RECT  3.924 19.651 4.266 19.769 ;
     RECT  22.788 19.133 22.806 20.107 ;
     RECT  3.924 19.769 4.086 20.281 ;
     RECT  5.976 19.483 21.762 20.299 ;
     RECT  5.94 20.299 21.762 20.345 ;
     RECT  6.048 20.345 21.762 20.417 ;
     RECT  2.304 19.499 2.697 20.425 ;
     RECT  3.636 20.281 4.086 20.425 ;
     RECT  22.752 20.107 22.806 20.461 ;
     RECT  6.048 20.417 21.258 20.489 ;
     RECT  2.304 20.425 4.086 20.551 ;
     RECT  2.304 20.551 4.734 20.731 ;
     RECT  6.12 20.489 21.258 20.849 ;
     RECT  22.176 20.461 22.806 20.957 ;
     RECT  2.304 20.731 4.95 21.001 ;
     RECT  6.12 20.849 21.186 21.005 ;
     RECT  6.264 21.005 21.186 21.053 ;
     RECT  22.212 20.957 22.806 21.119 ;
     RECT  6.48 21.053 21.186 21.263 ;
     RECT  2.304 21.001 5.166 21.389 ;
     RECT  2.304 21.389 4.95 21.425 ;
     RECT  23.652 21.355 23.67 21.497 ;
     RECT  6.516 21.263 21.186 21.659 ;
     RECT  2.304 21.425 4.626 21.965 ;
     RECT  20.916 21.659 21.186 21.979 ;
     RECT  3.96 21.965 4.626 22.199 ;
     RECT  22.788 21.119 22.806 22.199 ;
     RECT  2.304 21.965 3.114 22.235 ;
     RECT  3.96 22.199 4.554 22.541 ;
     RECT  6.516 21.659 20.178 22.585 ;
     RECT  20.916 21.979 21.87 22.585 ;
     RECT  4.176 22.541 4.554 22.775 ;
     RECT  5.292 22.621 5.454 22.795 ;
     RECT  6.516 22.585 22.23 22.795 ;
     RECT  5.292 22.795 22.23 22.829 ;
     RECT  2.304 22.235 2.697 23.125 ;
     RECT  2.304 23.125 2.934 23.161 ;
     RECT  23.652 22.987 23.67 23.189 ;
     RECT  2.268 23.161 2.934 23.213 ;
     RECT  5.724 22.829 22.23 23.227 ;
     RECT  4.5 22.775 4.554 23.357 ;
     RECT  2.304 23.213 2.934 23.395 ;
     RECT  2.304 23.395 3.294 23.431 ;
     RECT  4.68 23.431 4.698 23.549 ;
     RECT  5.724 23.227 22.266 23.549 ;
     RECT  2.304 23.431 3.474 23.585 ;
     RECT  5.724 23.549 5.742 23.585 ;
     RECT  2.304 23.585 3.294 23.729 ;
     RECT  6.516 23.549 22.266 24.169 ;
     RECT  6.516 24.169 22.842 24.269 ;
     RECT  4.86 24.205 5.454 24.359 ;
     RECT  4.86 24.359 5.274 24.475 ;
     RECT  4.752 24.475 5.274 24.509 ;
     RECT  4.752 24.509 4.77 24.523 ;
     RECT  6.516 24.269 21.798 24.601 ;
     RECT  6.48 24.601 21.798 24.653 ;
     RECT  2.304 23.729 3.222 24.781 ;
     RECT  6.516 24.653 21.798 24.809 ;
     RECT  4.356 24.523 4.77 25.169 ;
     RECT  4.356 25.169 4.374 25.321 ;
     RECT  6.516 24.809 21.69 25.349 ;
     RECT  2.304 24.781 3.438 25.411 ;
     RECT  4.212 25.321 4.374 25.411 ;
     RECT  22.824 25.051 22.842 25.483 ;
     RECT  22.788 25.483 22.842 25.709 ;
     RECT  2.304 25.411 4.374 25.745 ;
     RECT  22.788 25.709 22.806 25.861 ;
     RECT  6.516 25.349 21.294 26.221 ;
     RECT  6.48 26.221 21.294 26.257 ;
     RECT  23.652 25.867 23.67 26.357 ;
     RECT  6.156 26.257 21.294 26.429 ;
     RECT  2.304 25.745 3.906 26.491 ;
     RECT  6.48 26.429 21.294 26.491 ;
     RECT  2.304 26.491 4.446 26.528 ;
     RECT  6.48 26.491 21.69 26.555 ;
     RECT  6.516 26.555 21.69 26.599 ;
     RECT  22.752 25.861 22.806 26.599 ;
     RECT  6.516 26.599 22.806 26.765 ;
     RECT  2.304 26.528 3.906 26.825 ;
     RECT  2.304 26.825 2.754 27.059 ;
     RECT  6.516 26.765 21.87 27.131 ;
     RECT  22.788 26.765 22.806 27.175 ;
     RECT  3.6 26.825 3.906 27.481 ;
     RECT  3.6 27.481 4.05 27.635 ;
     RECT  6.516 27.131 21.186 27.679 ;
     RECT  5.796 27.679 21.186 27.779 ;
     RECT  6.012 27.779 21.186 27.905 ;
     RECT  6.12 27.905 21.186 27.913 ;
     RECT  22.788 27.175 22.842 27.965 ;
     RECT  22.788 27.965 22.806 28.021 ;
     RECT  6.12 27.913 21.258 28.049 ;
     RECT  7.092 28.049 21.258 28.171 ;
     RECT  22.248 28.021 22.806 28.171 ;
     RECT  4.212 27.883 4.59 28.381 ;
     RECT  7.092 28.171 22.806 28.397 ;
     RECT  3.708 28.381 4.59 28.417 ;
     RECT  3.672 28.417 4.59 28.493 ;
     RECT  2.304 27.059 2.697 28.525 ;
     RECT  2.304 28.525 2.862 28.561 ;
     RECT  3.672 28.493 4.482 28.561 ;
     RECT  22.788 28.397 22.806 28.679 ;
     RECT  2.304 28.561 4.482 28.877 ;
     RECT  6.12 28.049 6.138 28.949 ;
     RECT  23.652 27.547 23.67 28.987 ;
     RECT  7.092 28.397 21.834 29.057 ;
     RECT  7.092 29.057 21.762 29.093 ;
     RECT  2.304 28.877 3.726 29.219 ;
     RECT  4.464 28.877 4.482 29.219 ;
     RECT  3.42 29.219 3.726 29.255 ;
     RECT  5.652 29.221 5.814 29.335 ;
     RECT  5.04 29.335 5.814 29.489 ;
     RECT  5.256 29.489 5.274 29.525 ;
     RECT  23.616 28.987 23.67 29.561 ;
     RECT  2.304 29.219 2.697 29.995 ;
     RECT  22.788 29.611 22.806 30.029 ;
     RECT  2.304 29.995 3.366 30.181 ;
     RECT  7.308 29.093 21.762 30.427 ;
     RECT  23.652 29.561 23.67 30.443 ;
     RECT  2.304 30.181 3.51 30.451 ;
     RECT  2.304 30.451 3.618 30.541 ;
     RECT  5.508 30.427 5.526 30.569 ;
     RECT  2.304 30.541 3.726 30.685 ;
     RECT  2.304 30.685 3.798 30.721 ;
     RECT  7.308 30.427 22.23 30.811 ;
     RECT  2.304 30.721 3.87 30.839 ;
     RECT  2.304 30.839 3.726 30.875 ;
     RECT  2.304 30.875 3.618 31.109 ;
     RECT  5.796 30.991 6.534 31.109 ;
     RECT  3.456 31.109 3.474 31.145 ;
     RECT  5.796 31.109 6.354 31.145 ;
     RECT  7.308 30.811 22.266 31.217 ;
     RECT  23.652 31.243 23.67 31.559 ;
     RECT  6.336 31.145 6.354 31.661 ;
     RECT  4.788 31.627 4.806 31.729 ;
     RECT  4.284 31.729 4.806 31.801 ;
     RECT  4.284 31.801 4.95 31.829 ;
     RECT  4.716 31.829 4.95 31.955 ;
     RECT  7.308 31.217 22.23 32.059 ;
     RECT  7.308 32.059 22.806 32.099 ;
     RECT  7.308 32.099 22.23 32.305 ;
     RECT  6.948 32.305 22.23 32.381 ;
     RECT  7.092 32.381 22.23 32.459 ;
     RECT  2.304 31.109 2.697 32.491 ;
     RECT  6.084 32.341 6.102 32.495 ;
     RECT  7.308 32.459 22.23 32.531 ;
     RECT  7.308 32.531 21.33 32.765 ;
     RECT  22.212 32.531 22.23 32.875 ;
     RECT  2.304 32.491 3.33 32.881 ;
     RECT  22.212 32.875 22.806 32.909 ;
     RECT  2.304 32.881 3.438 32.999 ;
     RECT  4.5 33.115 4.518 33.151 ;
     RECT  5.256 32.071 5.274 33.151 ;
     RECT  4.392 33.151 5.274 33.259 ;
     RECT  22.752 32.909 22.806 33.341 ;
     RECT  4.392 33.259 5.922 33.511 ;
     RECT  4.392 33.511 6.282 33.539 ;
     RECT  5.256 33.539 6.282 33.575 ;
     RECT  7.308 32.765 21.294 33.739 ;
     RECT  4.392 33.539 4.518 33.845 ;
     RECT  2.304 32.999 3.402 34.027 ;
     RECT  6.264 33.575 6.282 34.159 ;
     RECT  7.308 33.739 21.834 34.315 ;
     RECT  22.788 33.341 22.806 34.315 ;
     RECT  6.264 34.159 6.462 34.501 ;
     RECT  7.308 34.315 22.806 34.501 ;
     RECT  6.264 34.501 22.806 34.619 ;
     RECT  7.308 34.619 22.806 34.727 ;
     RECT  5.256 33.575 5.274 34.771 ;
     RECT  2.304 34.027 4.158 34.795 ;
     RECT  5.256 34.771 5.346 34.795 ;
     RECT  2.304 34.795 5.346 34.861 ;
     RECT  6.264 34.619 6.462 34.861 ;
     RECT  2.304 34.861 6.462 34.889 ;
     RECT  2.304 34.889 4.158 34.925 ;
     RECT  2.304 34.925 3.798 34.961 ;
     RECT  5.328 34.889 6.462 34.961 ;
     RECT  5.328 34.961 5.526 35.159 ;
     RECT  22.824 34.747 22.842 35.267 ;
     RECT  23.652 34.939 23.67 35.371 ;
     RECT  23.616 35.371 23.67 35.537 ;
     RECT  7.308 34.727 21.87 35.563 ;
     RECT  23.616 35.537 23.634 35.609 ;
     RECT  2.304 34.961 2.697 35.659 ;
     RECT  7.308 35.563 21.942 35.851 ;
     RECT  3.42 34.961 3.798 35.977 ;
     RECT  2.268 35.659 2.697 36.005 ;
     RECT  7.308 35.851 22.266 36.029 ;
     RECT  5.328 35.159 5.346 36.121 ;
     RECT  2.304 36.005 2.697 36.211 ;
     RECT  3.42 35.977 4.266 36.211 ;
     RECT  7.308 36.029 22.23 36.239 ;
     RECT  5.04 36.121 5.382 36.275 ;
     RECT  21.744 36.239 22.23 36.383 ;
     RECT  2.304 36.211 4.266 36.391 ;
     RECT  2.304 36.391 4.59 36.509 ;
     RECT  2.304 36.509 3.438 36.545 ;
     RECT  4.392 36.509 4.59 36.545 ;
     RECT  5.328 36.275 5.382 36.661 ;
     RECT  4.392 36.545 4.41 36.797 ;
     RECT  5.328 36.661 5.49 36.895 ;
     RECT  6.372 34.961 6.462 36.895 ;
     RECT  21.78 36.383 22.23 36.959 ;
     RECT  21.78 36.959 21.87 37.037 ;
     RECT  5.328 36.895 6.462 37.085 ;
     RECT  7.308 36.239 20.97 37.129 ;
     RECT  7.236 37.129 20.97 37.201 ;
     RECT  21.78 37.037 21.798 37.201 ;
     RECT  23.652 37.243 23.67 37.426 ;
     RECT  23.616 37.426 23.67 37.427 ;
     RECT  2.304 36.545 3.078 37.561 ;
     RECT  2.304 37.561 3.222 37.579 ;
     RECT  4.068 37.471 4.086 37.597 ;
     RECT  0.108 37.483 0.126 37.613 ;
     RECT  2.304 37.579 3.294 37.705 ;
     RECT  4.068 37.597 4.302 37.705 ;
     RECT  2.304 37.705 4.302 37.741 ;
     RECT  23.616 37.427 23.634 37.769 ;
     RECT  5.328 37.085 5.346 37.867 ;
     RECT  5.328 37.867 5.49 37.904 ;
     RECT  5.328 37.904 5.346 37.915 ;
     RECT  2.304 37.741 4.41 38.011 ;
     RECT  5.148 37.915 5.346 38.011 ;
     RECT  6.372 37.085 6.462 38.011 ;
     RECT  6.192 38.011 6.462 38.155 ;
     RECT  7.236 37.201 21.798 38.155 ;
     RECT  2.304 38.011 5.346 38.399 ;
     RECT  2.304 38.399 4.302 38.435 ;
     RECT  6.192 38.155 21.798 38.443 ;
     RECT  22.788 37.741 22.806 38.443 ;
     RECT  6.192 38.443 22.806 38.507 ;
     RECT  22.788 38.507 22.806 38.683 ;
     RECT  6.192 38.507 21.762 38.741 ;
     RECT  5.112 38.399 5.346 38.821 ;
     RECT  6.192 38.741 21.222 38.821 ;
     RECT  22.788 38.683 22.842 38.821 ;
     RECT  22.788 38.821 22.878 38.947 ;
     RECT  22.788 38.947 22.914 39.047 ;
     RECT  5.112 38.821 21.222 39.245 ;
     RECT  5.148 39.245 21.222 39.499 ;
     RECT  5.148 39.499 21.654 39.691 ;
     RECT  23.652 39.883 23.67 40.013 ;
     RECT  5.148 39.691 21.798 40.099 ;
     RECT  22.788 39.047 22.806 40.099 ;
     RECT  5.148 40.099 22.806 40.165 ;
     RECT  2.304 38.435 4.086 40.171 ;
     RECT  4.968 40.165 22.806 40.171 ;
     RECT  2.304 40.171 22.806 40.325 ;
     RECT  4.824 40.325 22.806 40.349 ;
     RECT  2.304 40.325 4.086 40.559 ;
     RECT  4.824 40.349 21.834 40.865 ;
     RECT  5.256 40.865 21.834 41.449 ;
     RECT  22.716 40.349 22.806 41.449 ;
     RECT  2.304 40.559 4.014 41.521 ;
     RECT  2.304 41.521 4.266 41.683 ;
     RECT  0.144 41.647 0.162 41.755 ;
     RECT  23.652 41.371 23.67 41.819 ;
     RECT  2.304 41.683 4.446 41.945 ;
     RECT  5.256 41.449 22.806 41.945 ;
     RECT  2.415 41.945 4.446 42.061 ;
     RECT  5.256 41.945 5.274 42.061 ;
     RECT  6.12 41.945 22.806 42.089 ;
     RECT  0.108 41.755 0.162 42.317 ;
     RECT  0.144 42.317 0.162 42.565 ;
     RECT  2.415 42.061 5.274 42.755 ;
     RECT  6.12 42.089 21.366 42.811 ;
     RECT  22.176 42.089 22.806 42.811 ;
     RECT  6.12 42.811 22.806 42.871 ;
     RECT  2.415 42.755 4.338 42.989 ;
     RECT  2.415 42.989 3.366 42.997 ;
     RECT  2.304 42.997 3.366 43.037 ;
     RECT  6.12 42.871 22.842 43.229 ;
     RECT  0.144 42.565 0.198 43.267 ;
     RECT  5.148 42.755 5.274 43.501 ;
     RECT  6.12 43.229 22.23 43.501 ;
     RECT  5.148 43.501 22.23 43.565 ;
     RECT  6.12 43.565 22.23 43.637 ;
     RECT  4.104 42.989 4.338 43.645 ;
     RECT  5.148 43.565 5.274 43.645 ;
     RECT  0.108 43.267 0.198 43.757 ;
     RECT  2.415 43.037 3.366 43.843 ;
     RECT  4.104 43.645 5.274 43.843 ;
     RECT  22.212 43.637 22.23 43.871 ;
     RECT  2.415 43.843 5.274 44.077 ;
     RECT  2.304 44.077 5.274 44.477 ;
     RECT  22.752 44.011 22.806 44.519 ;
     RECT  5.148 44.477 5.274 44.609 ;
     RECT  6.12 43.637 21.438 44.635 ;
     RECT  22.752 44.519 22.77 44.909 ;
     RECT  6.12 44.635 21.798 45.259 ;
     RECT  5.256 44.609 5.274 45.391 ;
     RECT  6.12 45.259 21.942 45.391 ;
     RECT  2.304 44.477 4.41 45.581 ;
     RECT  0.108 43.757 0.126 45.965 ;
     RECT  23.652 45.691 23.67 46.103 ;
     RECT  22.788 46.075 22.806 46.201 ;
     RECT  2.415 45.581 4.41 46.315 ;
     RECT  5.256 45.391 21.942 46.409 ;
     RECT  22.752 46.201 22.806 46.699 ;
     RECT  2.304 46.315 4.41 46.885 ;
     RECT  5.256 46.409 21.294 46.885 ;
     RECT  22.14 46.699 22.806 46.885 ;
     RECT  22.14 46.885 22.842 46.973 ;
     RECT  2.304 46.885 21.294 47.323 ;
     RECT  22.14 46.973 22.806 47.357 ;
     RECT  2.304 47.323 21.366 47.515 ;
     RECT  2.304 47.515 21.726 47.687 ;
     RECT  2.304 47.687 21.366 47.693 ;
     RECT  2.304 47.693 4.482 47.789 ;
     RECT  5.256 47.693 21.366 47.849 ;
     RECT  23.652 47.755 23.67 47.993 ;
     RECT  22.752 47.357 22.806 48.389 ;
     RECT  0.108 47.155 0.126 48.557 ;
     RECT  5.652 47.849 21.258 48.571 ;
     RECT  5.652 48.571 21.402 48.763 ;
     RECT  2.415 47.789 4.482 48.775 ;
     RECT  2.304 48.775 4.482 48.811 ;
     RECT  22.788 48.389 22.806 48.839 ;
     RECT  2.304 48.811 4.518 48.937 ;
     RECT  2.304 48.937 4.734 48.989 ;
     RECT  5.652 48.763 21.906 49.819 ;
     RECT  2.304 48.989 4.554 49.981 ;
     RECT  5.652 49.819 21.942 49.981 ;
     RECT  2.304 49.981 21.942 50.443 ;
     RECT  2.304 50.443 22.23 50.635 ;
     RECT  2.304 50.635 22.266 50.717 ;
     RECT  2.34 50.717 22.266 50.729 ;
     RECT  2.34 50.729 22.23 51.125 ;
     RECT  2.376 51.125 22.23 51.737 ;
     RECT  2.376 51.737 4.986 51.883 ;
     RECT  5.868 51.737 22.23 52.051 ;
     RECT  2.304 51.883 4.986 52.795 ;
     RECT  2.304 52.795 5.058 52.825 ;
     RECT  5.868 52.051 22.842 52.825 ;
     RECT  2.304 52.825 22.842 53.021 ;
     RECT  5.868 53.021 22.842 53.117 ;
     RECT  22.788 53.117 22.842 53.741 ;
     RECT  2.304 53.021 5.094 53.905 ;
     RECT  5.868 53.117 21.69 53.905 ;
     RECT  22.788 53.741 22.806 54.329 ;
     RECT  2.304 53.905 21.69 54.331 ;
     RECT  2.304 54.331 21.834 54.437 ;
     RECT  2.304 54.437 21.33 54.905 ;
     RECT  2.376 54.905 21.33 55.139 ;
     RECT  22.212 54.523 22.266 55.183 ;
     RECT  22.212 55.183 22.806 55.211 ;
     RECT  23.652 54.955 23.67 55.211 ;
     RECT  2.415 55.139 21.33 55.319 ;
     RECT  7.164 55.319 21.33 55.387 ;
     RECT  7.164 55.387 21.834 55.787 ;
     RECT  2.415 55.319 6.39 56.101 ;
     RECT  7.164 55.787 21.69 56.101 ;
     RECT  2.415 56.101 21.69 56.335 ;
     RECT  2.376 56.335 21.69 56.569 ;
     RECT  22.788 55.211 22.806 56.569 ;
     RECT  2.376 56.569 22.806 56.587 ;
     RECT  2.304 56.587 22.806 57.245 ;
     RECT  22.788 57.245 22.806 57.299 ;
     RECT  2.304 57.245 21.87 57.875 ;
     RECT  2.34 57.875 21.87 58.019 ;
     RECT  2.34 58.019 21.762 58.559 ;
     RECT  2.34 58.559 21.33 58.649 ;
     RECT  2.34 58.649 21.294 58.693 ;
     RECT  2.304 58.693 21.294 58.699 ;
     RECT  2.232 58.699 21.294 58.955 ;
     RECT  23.652 57.451 23.67 59.027 ;
     RECT  22.248 59.071 22.266 59.083 ;
     RECT  2.304 58.955 21.294 59.099 ;
     RECT  0.108 58.495 0.126 59.165 ;
     RECT  2.376 59.099 21.294 59.707 ;
     RECT  22.248 59.083 22.806 59.707 ;
     RECT  2.376 59.707 22.806 60.647 ;
     RECT  2.376 60.647 21.87 60.655 ;
     RECT  2.34 60.655 21.87 61.051 ;
     RECT  2.304 61.051 21.87 61.771 ;
     RECT  22.788 60.647 22.806 61.771 ;
     RECT  2.304 61.771 22.806 62.239 ;
     RECT  2.304 62.239 22.842 62.429 ;
     RECT  2.304 62.429 22.266 63.149 ;
     RECT  2.304 63.149 21.114 63.931 ;
     RECT  21.852 63.149 22.266 63.931 ;
     RECT  2.304 63.931 22.266 64.291 ;
     RECT  2.304 64.291 22.842 64.685 ;
     RECT  2.304 64.685 22.806 64.697 ;
     RECT  22.788 64.697 22.806 64.859 ;
     RECT  2.304 64.697 21.87 64.967 ;
     RECT  2.304 64.967 21.798 66.515 ;
     RECT  2.376 66.515 21.798 66.523 ;
     RECT  2.376 66.523 22.23 66.929 ;
     RECT  2.376 66.929 21.726 67.291 ;
     RECT  2.304 67.291 21.726 67.595 ;
     RECT  23.652 67.531 23.67 67.631 ;
     RECT  22.788 67.339 22.806 68.155 ;
     RECT  2.415 67.595 21.726 68.251 ;
     RECT  22.752 68.155 22.806 68.369 ;
     RECT  2.415 68.251 21.762 68.395 ;
     RECT  2.304 68.395 21.762 68.587 ;
     RECT  22.752 68.369 22.77 68.587 ;
     RECT  2.304 68.587 22.77 68.819 ;
     RECT  22.752 68.819 22.77 68.909 ;
     RECT  2.304 68.819 21.762 70.025 ;
     RECT  2.415 70.025 21.762 70.411 ;
     RECT  2.415 70.411 22.23 70.529 ;
     RECT  23.652 68.779 23.67 70.709 ;
     RECT  22.788 70.681 22.806 70.907 ;
     RECT  2.415 70.529 21.87 71.275 ;
     RECT  23.652 71.467 23.67 71.753 ;
     RECT  2.304 71.275 21.87 71.837 ;
     RECT  2.34 71.837 21.87 72.031 ;
     RECT  2.34 72.031 22.23 72.317 ;
     RECT  2.34 72.317 21.834 72.329 ;
     RECT  23.652 72.667 23.67 72.907 ;
     RECT  2.415 72.329 21.834 73.075 ;
     RECT  2.412 73.075 21.834 73.099 ;
     RECT  2.412 73.099 22.23 73.373 ;
     RECT  2.412 73.373 21.726 73.381 ;
     RECT  23.616 72.907 23.67 73.409 ;
     RECT  23.652 73.409 23.67 73.877 ;
     RECT  2.376 73.381 21.726 73.885 ;
     RECT  2.304 73.885 21.726 74.345 ;
     RECT  2.34 74.345 21.726 74.353 ;
     RECT  22.788 74.347 22.806 74.353 ;
     RECT  2.34 74.353 22.806 74.849 ;
     RECT  2.34 74.849 22.266 75.005 ;
     RECT  2.34 75.005 21.942 75.199 ;
     RECT  2.304 75.199 21.942 75.245 ;
     RECT  0.036 73.507 0.054 75.259 ;
     RECT  0.036 75.259 0.126 75.389 ;
     RECT  23.652 75.595 23.67 75.767 ;
     RECT  22.788 75.775 22.806 75.821 ;
     RECT  2.34 75.245 21.942 76.315 ;
     RECT  2.304 76.315 21.942 76.505 ;
     RECT  2.34 76.505 21.942 76.891 ;
     RECT  22.788 76.603 22.806 76.891 ;
     RECT  2.34 76.891 22.806 77.549 ;
     RECT  23.652 76.795 23.67 77.656 ;
     RECT  23.616 77.656 23.67 77.657 ;
     RECT  23.616 77.657 23.634 78.269 ;
     RECT  0.036 75.389 0.054 78.475 ;
     RECT  2.34 77.549 22.41 78.475 ;
     RECT  2.34 78.475 22.806 78.667 ;
     RECT  2.304 78.667 22.806 79.205 ;
     RECT  2.34 79.205 22.806 79.781 ;
     RECT  23.652 79.291 23.67 79.915 ;
     RECT  2.34 79.781 21.546 80.059 ;
     RECT  23.616 79.915 23.67 80.087 ;
     RECT  2.304 80.059 21.546 80.285 ;
     RECT  23.652 80.087 23.67 80.627 ;
     RECT  2.34 80.285 21.546 80.731 ;
     RECT  22.752 79.781 22.806 80.969 ;
     RECT  2.34 80.731 21.654 81.067 ;
     RECT  22.752 80.969 22.77 81.329 ;
     RECT  2.304 81.067 21.654 81.355 ;
     RECT  2.304 81.355 21.798 81.979 ;
     RECT  2.304 81.979 22.266 82.787 ;
     RECT  23.652 81.739 23.67 82.795 ;
     RECT  22.212 82.787 22.266 82.859 ;
     RECT  2.304 82.787 21.366 82.949 ;
     RECT  23.616 82.795 23.67 82.987 ;
     RECT  22.716 83.029 22.734 83.065 ;
     RECT  2.304 82.949 21.294 83.264 ;
     RECT  23.58 82.987 23.67 83.489 ;
     RECT  22.716 83.065 22.842 83.803 ;
     RECT  2.376 83.264 21.294 84.091 ;
     RECT  23.652 83.489 23.67 84.137 ;
     RECT  22.212 83.803 22.842 84.209 ;
     RECT  22.788 84.209 22.842 84.461 ;
     RECT  2.304 84.091 21.294 84.721 ;
     RECT  2.304 84.721 21.798 84.893 ;
     RECT  0.036 78.475 0.09 85.003 ;
     RECT  0.036 85.003 0.126 85.037 ;
     RECT  22.788 84.461 22.806 85.051 ;
     RECT  22.212 85.051 22.806 85.289 ;
     RECT  22.788 85.289 22.806 85.459 ;
     RECT  22.788 85.459 22.842 85.517 ;
     RECT  0.072 85.037 0.126 85.531 ;
     RECT  0.072 85.531 0.162 85.559 ;
     RECT  0.144 85.559 0.162 85.568 ;
     RECT  2.304 84.893 21.186 85.675 ;
     RECT  2.304 85.675 21.834 85.991 ;
     RECT  2.304 85.991 21.798 86.639 ;
     RECT  2.304 86.639 21.726 86.837 ;
     RECT  22.788 85.517 22.806 86.881 ;
     RECT  22.788 86.881 22.842 86.957 ;
     RECT  22.788 86.957 22.806 87.421 ;
     RECT  22.212 87.421 22.806 87.581 ;
     RECT  2.304 86.837 21.474 87.931 ;
     RECT  2.304 87.931 21.87 88.259 ;
     RECT  2.304 88.259 21.654 88.889 ;
     RECT  8.892 88.889 21.654 89.239 ;
     RECT  8.892 89.239 21.762 89.537 ;
     RECT  14.688 89.537 21.762 89.611 ;
     RECT  2.304 88.889 8.097 89.735 ;
     RECT  22.752 87.581 22.806 89.843 ;
     RECT  2.34 89.735 8.097 89.879 ;
     RECT  14.688 89.611 21.942 89.995 ;
     RECT  14.688 89.995 22.23 90.041 ;
     RECT  14.688 90.041 21.942 90.311 ;
     RECT  8.892 89.537 13.95 90.553 ;
     RECT  14.688 90.311 21.762 90.553 ;
     RECT  8.892 90.553 21.762 90.617 ;
     RECT  2.376 89.879 8.097 90.619 ;
     RECT  2.304 90.619 8.097 90.667 ;
     RECT  8.892 90.617 21.654 90.851 ;
     RECT  2.232 90.667 8.097 90.887 ;
     RECT  23.652 91.051 23.67 91.229 ;
     RECT  8.892 90.851 21.618 91.675 ;
     RECT  8.892 91.675 21.87 92.201 ;
     RECT  2.304 90.887 8.097 92.749 ;
     RECT  2.304 92.749 8.154 92.861 ;
     RECT  4.896 92.861 8.154 92.923 ;
     RECT  8.892 92.201 20.286 92.923 ;
     RECT  4.896 92.923 20.286 92.939 ;
     RECT  6.444 92.939 20.286 92.947 ;
     RECT  21.096 92.201 21.87 92.947 ;
     RECT  2.304 92.861 4.158 92.975 ;
     RECT  2.304 92.975 4.014 93.019 ;
     RECT  23.652 92.491 23.67 93.083 ;
     RECT  6.444 92.947 21.87 93.307 ;
     RECT  22.788 90.619 22.806 93.307 ;
     RECT  0.036 91.633 0.054 93.595 ;
     RECT  4.968 92.939 5.706 93.629 ;
     RECT  1.98 93.019 4.014 93.865 ;
     RECT  4.968 93.629 5.67 93.865 ;
     RECT  1.98 93.865 5.67 94.019 ;
     RECT  1.98 94.019 4.194 94.091 ;
     RECT  4.968 94.019 5.67 94.603 ;
     RECT  6.444 93.307 22.806 94.603 ;
     RECT  4.968 94.603 22.806 94.937 ;
     RECT  1.98 94.091 4.014 95.083 ;
     RECT  4.968 94.937 21.294 95.083 ;
     RECT  1.98 95.083 21.294 95.441 ;
     RECT  0.036 93.595 0.126 95.453 ;
     RECT  22.176 94.937 22.806 95.639 ;
     RECT  19.836 95.441 21.294 95.707 ;
     RECT  22.176 95.639 22.23 95.707 ;
     RECT  4.968 95.441 19.062 96.331 ;
     RECT  19.836 95.707 22.23 96.331 ;
     RECT  1.98 95.441 4.23 96.449 ;
     RECT  4.212 96.449 4.23 96.565 ;
     RECT  4.968 96.331 22.23 96.565 ;
     RECT  4.212 96.565 22.23 96.811 ;
     RECT  0.036 95.453 0.054 96.835 ;
     RECT  0.036 96.835 0.126 97.085 ;
     RECT  4.212 96.811 22.806 97.259 ;
     RECT  0.108 97.085 0.126 97.277 ;
     RECT  1.98 96.449 3.474 98.041 ;
     RECT  4.212 97.259 22.23 98.041 ;
     RECT  1.98 98.041 22.23 98.155 ;
     RECT  1.98 98.155 22.266 98.519 ;
     RECT  22.248 98.519 22.266 98.609 ;
     RECT  1.98 98.519 21.294 98.717 ;
     RECT  23.652 98.221 23.67 98.717 ;
     RECT  2.415 98.717 21.294 99.149 ;
     RECT  2.415 99.149 20.61 99.185 ;
     RECT  2.415 99.185 9.126 99.197 ;
     RECT  9.9 99.185 20.61 99.197 ;
     RECT  3.24 99.197 5.094 99.245 ;
     RECT  6.516 99.197 9.126 99.245 ;
     RECT  12.996 99.197 14.166 99.257 ;
     RECT  14.904 99.197 20.61 99.257 ;
     RECT  3.276 99.245 3.294 99.341 ;
     RECT  4.5 99.245 5.094 99.341 ;
     RECT  15.948 99.257 20.61 99.341 ;
     RECT  2.415 99.197 2.505 99.377 ;
     RECT  12.996 99.257 13.914 99.377 ;
     RECT  15.948 99.341 19.422 99.377 ;
     RECT  6.516 99.245 8.154 99.485 ;
     RECT  12.996 99.377 13.158 99.485 ;
     RECT  15.948 99.377 18.558 99.485 ;
     RECT  6.516 99.485 7.578 99.533 ;
     RECT  15.948 99.485 18.486 99.533 ;
     RECT  12.024 99.197 12.15 99.677 ;
     RECT  6.516 99.533 7.398 99.725 ;
     RECT  10.728 99.197 11.142 99.725 ;
     RECT  12.132 99.677 12.15 99.725 ;
     RECT  20.556 99.341 20.61 99.725 ;
     RECT  15.948 99.533 18.27 100.013 ;
     RECT  15.948 100.013 17.766 100.301 ;
     RECT  6.768 99.725 6.786 100.349 ;
     RECT  13.896 99.377 13.914 100.349 ;
     RECT  14.904 99.257 15.21 100.349 ;
     RECT  15.948 100.301 17.694 100.349 ;
     RECT  19.404 99.377 19.422 100.349 ;
     RECT  17.316 100.349 17.694 100.589 ;
     RECT  9.108 99.245 9.126 100.877 ;
     RECT  12.996 99.485 13.014 100.877 ;
     RECT  17.316 100.589 17.334 100.877 ;
     RECT  15.192 100.349 15.21 100.925 ;
     RECT  20.556 99.725 20.574 100.973 ;
     RECT  5.076 99.341 5.094 101.405 ;
     RECT  21.672 99.265 21.69 101.405 ;
     RECT  15.948 100.349 16.506 101.453 ;
     RECT  16.488 101.453 16.506 101.501 ;
    LAYER M4 ;
     RECT  0.025 85.008 0.06 85.032 ;
     RECT  0.025 97.056 0.06 97.08 ;
     RECT  0.06 2.688 0.137 98.712 ;
     RECT  0.137 18.096 0.173 18.12 ;
     RECT  0.137 19.152 0.173 47.784 ;
     RECT  0.137 48.864 0.179 98.712 ;
     RECT  0.173 43.008 0.209 47.784 ;
     RECT  0.179 60.96 0.227 98.712 ;
     RECT  0.227 60.96 0.275 92.52 ;
     RECT  0.227 93.504 0.323 98.712 ;
     RECT  0.137 2.784 2.408 5.256 ;
     RECT  0.137 6.336 2.408 17.016 ;
     RECT  0.173 19.152 2.408 41.928 ;
     RECT  0.209 43.008 2.408 43.032 ;
     RECT  0.209 44.112 2.408 47.784 ;
     RECT  0.179 48.864 2.408 59.88 ;
     RECT  0.275 61.056 2.408 92.52 ;
     RECT  0.323 93.504 2.408 94.728 ;
     RECT  0.323 95.712 2.408 98.712 ;
     RECT  2.408 2.148 2.512 99.372 ;
     RECT  2.512 2.418 2.704 99.336 ;
     RECT  2.704 67.584 2.765 68.52 ;
     RECT  2.704 80.928 2.819 80.952 ;
     RECT  2.704 93.6 2.819 94.056 ;
     RECT  2.629 101.376 2.819 101.4 ;
     RECT  2.704 83.232 2.845 83.4 ;
     RECT  2.704 95.76 2.845 95.784 ;
     RECT  2.704 23.04 2.867 23.88 ;
     RECT  2.704 58.128 2.873 61.656 ;
     RECT  2.765 67.776 2.915 68.232 ;
     RECT  2.873 58.128 3.059 60.264 ;
     RECT  2.704 64.896 3.125 65.16 ;
     RECT  3.059 58.128 3.155 59.592 ;
     RECT  2.704 2.784 3.241 4.152 ;
     RECT  2.704 36.384 3.305 37.608 ;
     RECT  2.704 99.168 3.305 99.336 ;
     RECT  2.704 32.496 3.341 32.52 ;
     RECT  2.704 90.48 3.395 90.504 ;
     RECT  2.704 42.576 3.436 42.6 ;
     RECT  2.704 30 3.443 30.312 ;
     RECT  3.155 59.232 3.443 59.592 ;
     RECT  3.125 64.896 3.443 64.92 ;
     RECT  3.241 2.784 3.449 3.048 ;
     RECT  3.443 30.288 3.484 30.312 ;
     RECT  2.873 61.632 3.485 61.656 ;
     RECT  2.704 66.144 3.485 66.168 ;
     RECT  2.704 73.968 3.491 75.432 ;
     RECT  2.704 28.464 3.539 28.968 ;
     RECT  3.305 36.384 3.539 37.032 ;
     RECT  3.155 58.128 3.565 58.152 ;
     RECT  2.704 52.176 3.629 53.256 ;
     RECT  2.704 15.6 3.635 17.496 ;
     RECT  2.704 20.784 3.635 21 ;
     RECT  2.704 33.6 3.635 33.624 ;
     RECT  2.704 55.248 3.635 56.568 ;
     RECT  2.704 72.912 3.697 72.936 ;
     RECT  3.635 20.88 3.769 21 ;
     RECT  2.704 45.936 3.805 45.96 ;
     RECT  2.704 25.584 3.836 26.76 ;
     RECT  3.836 25.584 3.923 27.336 ;
     RECT  2.704 7.056 3.973 7.08 ;
     RECT  3.805 8.16 3.973 8.184 ;
     RECT  2.704 12.48 3.973 12.504 ;
     RECT  2.867 23.856 3.973 23.88 ;
     RECT  2.704 44.352 3.973 44.376 ;
     RECT  3.805 45.552 3.973 45.96 ;
     RECT  2.704 47.088 3.973 47.352 ;
     RECT  3.635 55.824 3.973 56.568 ;
     RECT  2.704 34.608 3.985 34.632 ;
     RECT  3.973 23.328 4.019 24.552 ;
     RECT  3.973 44.352 4.019 47.352 ;
     RECT  2.704 82.032 4.021 82.056 ;
     RECT  2.845 83.376 4.021 83.4 ;
     RECT  2.704 77.52 4.061 77.544 ;
     RECT  4.021 82.032 4.061 83.4 ;
     RECT  3.539 36.384 4.069 36.792 ;
     RECT  2.704 70.944 4.069 70.968 ;
     RECT  3.697 72.048 4.069 72.936 ;
     RECT  3.973 12.48 4.093 12.552 ;
     RECT  2.704 88.896 4.097 88.92 ;
     RECT  2.704 9.984 4.129 10.008 ;
     RECT  4.069 70.944 4.129 72.936 ;
     RECT  4.061 82.56 4.129 83.4 ;
     RECT  3.973 7.056 4.133 8.184 ;
     RECT  4.019 46.176 4.133 47.352 ;
     RECT  4.129 9.984 4.172 10.344 ;
     RECT  4.093 11.664 4.201 12.552 ;
     RECT  4.133 46.704 4.201 47.352 ;
     RECT  2.704 48.912 4.201 48.936 ;
     RECT  4.019 44.352 4.205 45 ;
     RECT  3.769 30.72 4.213 30.744 ;
     RECT  4.205 44.352 4.213 44.616 ;
     RECT  4.129 78.672 4.213 78.696 ;
     RECT  2.704 92.16 4.213 92.184 ;
     RECT  2.819 93.6 4.213 93.624 ;
     RECT  4.172 9.456 4.259 10.344 ;
     RECT  2.704 39.024 4.259 39.048 ;
     RECT  3.491 74.592 4.273 75.432 ;
     RECT  2.704 50.256 4.309 50.28 ;
     RECT  3.443 59.232 4.349 59.256 ;
     RECT  4.213 44.256 4.381 44.616 ;
     RECT  4.213 95.088 4.381 95.112 ;
     RECT  3.923 25.584 4.385 26.52 ;
     RECT  3.629 52.176 4.385 52.2 ;
     RECT  3.973 55.824 4.385 57.048 ;
     RECT  2.704 79.776 4.385 79.8 ;
     RECT  4.309 90.624 4.405 90.648 ;
     RECT  4.019 24.48 4.412 24.552 ;
     RECT  4.381 44.208 4.412 44.616 ;
     RECT  3.949 5.568 4.421 6.024 ;
     RECT  4.133 7.056 4.421 7.08 ;
     RECT  4.405 90.624 4.451 90.744 ;
     RECT  3.305 99.168 4.46 99.24 ;
     RECT  4.412 24.48 4.499 25.128 ;
     RECT  3.539 28.464 4.501 28.872 ;
     RECT  4.213 30.72 4.501 31.32 ;
     RECT  3.829 41.856 4.501 42.456 ;
     RECT  4.201 46.704 4.501 48.936 ;
     RECT  4.451 90.72 4.501 90.744 ;
     RECT  4.213 92.16 4.501 93.912 ;
     RECT  4.381 95.088 4.501 95.208 ;
     RECT  4.309 50.16 4.525 50.376 ;
     RECT  4.019 23.328 4.529 23.352 ;
     RECT  4.501 90.72 4.547 95.208 ;
     RECT  4.501 41.856 4.549 42.6 ;
     RECT  4.412 43.824 4.549 44.616 ;
     RECT  4.129 82.56 4.549 84.36 ;
     RECT  3.829 97.776 4.549 97.8 ;
     RECT  4.501 28.464 4.561 29.256 ;
     RECT  2.915 67.776 4.561 67.8 ;
     RECT  3.769 20.88 4.565 21.672 ;
     RECT  4.385 56.544 4.597 57.048 ;
     RECT  4.489 63.504 4.597 63.528 ;
     RECT  4.561 27.888 4.601 29.256 ;
     RECT  3.985 34.032 4.604 34.632 ;
     RECT  4.604 33.216 4.633 34.632 ;
     RECT  4.561 67.248 4.633 67.8 ;
     RECT  4.489 18.768 4.691 18.792 ;
     RECT  4.633 33.216 4.691 34.824 ;
     RECT  4.691 34.8 4.717 34.824 ;
     RECT  3.635 17.472 4.732 17.496 ;
     RECT  4.549 82.56 4.739 85.08 ;
     RECT  4.633 66.816 4.741 67.8 ;
     RECT  4.501 46.704 4.745 48.984 ;
     RECT  4.739 82.56 4.745 84.984 ;
     RECT  4.547 92.832 4.745 95.208 ;
     RECT  4.525 38.016 4.777 38.04 ;
     RECT  3.629 53.232 4.777 53.256 ;
     RECT  4.748 54.48 4.777 54.504 ;
     RECT  4.273 74.592 4.813 75.528 ;
     RECT  4.501 30.72 4.817 31.656 ;
     RECT  4.777 53.232 4.835 54.504 ;
     RECT  4.597 56.544 4.835 58.68 ;
     RECT  4.597 63.456 4.844 63.528 ;
     RECT  4.669 62.208 4.849 62.232 ;
     RECT  4.849 61.872 4.885 62.232 ;
     RECT  4.597 65.136 4.885 65.16 ;
     RECT  4.741 66.192 4.885 67.8 ;
     RECT  4.357 81.312 4.885 81.336 ;
     RECT  4.745 82.56 4.931 84.6 ;
     RECT  4.813 74.448 4.933 75.528 ;
     RECT  4.885 65.136 4.94 67.8 ;
     RECT  2.704 14.592 4.957 14.616 ;
     RECT  4.94 65.136 4.957 68.76 ;
     RECT  4.835 53.232 4.993 54.216 ;
     RECT  4.885 61.2 5.029 62.28 ;
     RECT  4.561 77.904 5.029 78.648 ;
     RECT  4.745 93.6 5.029 95.208 ;
     RECT  4.405 96.48 5.029 96.504 ;
     RECT  4.931 82.944 5.033 84.6 ;
     RECT  4.46 99.168 5.036 99.336 ;
     RECT  4.549 97.728 5.057 97.8 ;
     RECT  5.036 99.168 5.057 99.768 ;
     RECT  5.057 97.728 5.123 99.768 ;
     RECT  4.069 35.808 5.125 36.792 ;
     RECT  4.957 40.176 5.125 40.2 ;
     RECT  4.777 38.016 5.137 38.184 ;
     RECT  4.957 65.136 5.137 68.904 ;
     RECT  2.704 69.936 5.137 69.96 ;
     RECT  4.129 70.944 5.137 73.032 ;
     RECT  4.933 74.448 5.137 76.104 ;
     RECT  5.137 37.92 5.171 38.184 ;
     RECT  4.844 63.456 5.173 63.672 ;
     RECT  5.137 65.136 5.173 69.96 ;
     RECT  5.137 70.944 5.173 76.104 ;
     RECT  5.029 77.136 5.173 78.648 ;
     RECT  4.525 88.08 5.173 88.104 ;
     RECT  3.241 4.128 5.177 4.152 ;
     RECT  5.171 37.92 5.177 38.04 ;
     RECT  4.993 52.8 5.219 54.216 ;
     RECT  4.133 8.16 5.221 8.184 ;
     RECT  4.259 9.456 5.221 9.48 ;
     RECT  5.173 63.456 5.221 69.96 ;
     RECT  5.173 70.944 5.221 78.648 ;
     RECT  5.221 63.456 5.228 78.648 ;
     RECT  4.421 5.568 5.249 5.592 ;
     RECT  5.173 88.08 5.257 88.968 ;
     RECT  5.029 93.6 5.281 96.504 ;
     RECT  5.123 97.728 5.281 99.192 ;
     RECT  4.499 24.48 5.285 24.504 ;
     RECT  5.029 61.152 5.309 62.28 ;
     RECT  5.228 63.36 5.309 78.648 ;
     RECT  5.221 8.16 5.313 9.48 ;
     RECT  5.309 61.152 5.317 78.648 ;
     RECT  4.547 91.056 5.357 91.512 ;
     RECT  5.245 59.856 5.365 59.88 ;
     RECT  5.317 61.008 5.365 78.648 ;
     RECT  5.313 8.736 5.393 9.48 ;
     RECT  5.021 101.376 5.411 101.4 ;
     RECT  4.957 14.592 5.413 15.192 ;
     RECT  3.877 86.88 5.425 86.904 ;
     RECT  5.125 35.808 5.461 36.936 ;
     RECT  5.177 37.92 5.461 37.944 ;
     RECT  3.449 3.024 5.465 3.048 ;
     RECT  5.381 6.816 5.465 6.84 ;
     RECT  4.817 30.72 5.497 31.128 ;
     RECT  5.461 35.808 5.497 37.944 ;
     RECT  4.885 80.928 5.557 81.336 ;
     RECT  5.557 80.928 5.569 81.912 ;
     RECT  5.033 82.944 5.603 82.968 ;
     RECT  5.365 59.856 5.605 78.648 ;
     RECT  5.357 91.056 5.669 91.08 ;
     RECT  4.601 29.232 5.681 29.256 ;
     RECT  4.549 41.856 5.701 44.616 ;
     RECT  5.425 86.064 5.701 86.904 ;
     RECT  5.257 88.08 5.701 88.104 ;
     RECT  5.219 52.992 5.717 54.216 ;
     RECT  5.281 93.6 5.717 99.192 ;
     RECT  5.701 86.064 5.747 88.104 ;
     RECT  5.389 89.472 5.747 89.496 ;
     RECT  5.569 80.64 5.753 81.912 ;
     RECT  5.497 35.04 5.797 37.944 ;
     RECT  5.797 34.944 5.897 37.944 ;
     RECT  5.747 86.064 5.897 87.192 ;
     RECT  5.353 19.056 5.929 19.08 ;
     RECT  4.565 20.88 5.929 20.904 ;
     RECT  5.029 45.696 5.929 45.72 ;
     RECT  4.745 46.704 5.929 48.504 ;
     RECT  5.281 22.8 5.933 22.824 ;
     RECT  5.701 41.232 5.933 44.616 ;
     RECT  4.835 56.544 5.941 58.008 ;
     RECT  5.413 13.92 6.001 15.192 ;
     RECT  5.125 39.216 6.041 40.2 ;
     RECT  5.929 18.672 6.073 19.08 ;
     RECT  5.605 55.536 6.085 55.56 ;
     RECT  5.941 56.544 6.085 58.68 ;
     RECT  5.929 20.304 6.109 20.904 ;
     RECT  5.033 84 6.145 84.6 ;
     RECT  4.601 27.888 6.149 27.912 ;
     RECT  4.201 11.376 6.181 12.552 ;
     RECT  5.461 16.32 6.217 16.344 ;
     RECT  6.109 17.568 6.217 17.592 ;
     RECT  5.929 45.696 6.217 48.504 ;
     RECT  6.145 83.472 6.221 84.6 ;
     RECT  6.181 11.376 6.236 12.6 ;
     RECT  6.001 13.68 6.236 15.192 ;
     RECT  6.236 11.376 6.253 15.192 ;
     RECT  6.217 16.32 6.253 17.592 ;
     RECT  6.109 20.304 6.253 21 ;
     RECT  6.253 11.376 6.257 17.592 ;
     RECT  5.605 59.856 6.277 79.416 ;
     RECT  5.933 41.856 6.289 44.616 ;
     RECT  6.217 45.696 6.289 48.744 ;
     RECT  5.497 30.432 6.325 31.128 ;
     RECT  6.073 18.624 6.361 19.08 ;
     RECT  6.361 18.624 6.433 19.32 ;
     RECT  6.253 20.304 6.433 21.048 ;
     RECT  6.289 41.856 6.469 48.744 ;
     RECT  4.525 50.16 6.469 50.424 ;
     RECT  5.717 94.368 6.505 99.192 ;
     RECT  6.428 82.32 6.515 82.344 ;
     RECT  6.221 83.472 6.515 83.784 ;
     RECT  4.385 26.496 6.517 26.52 ;
     RECT  6.257 11.664 6.541 17.592 ;
     RECT  6.433 18.624 6.541 21.048 ;
     RECT  6.085 55.536 6.541 58.68 ;
     RECT  6.277 59.856 6.541 79.464 ;
     RECT  6.041 39.216 6.545 39.24 ;
     RECT  5.669 90.624 6.581 91.08 ;
     RECT  5.897 86.88 6.709 87.192 ;
     RECT  6.541 11.664 6.757 21.048 ;
     RECT  6.469 24.624 6.757 24.648 ;
     RECT  6.541 55.536 6.757 79.464 ;
     RECT  6.505 94.368 6.757 99.72 ;
     RECT  6.709 86.88 6.764 87.24 ;
     RECT  5.897 37.872 6.793 37.944 ;
     RECT  6.469 41.856 6.793 50.424 ;
     RECT  6.757 11.664 6.805 21.24 ;
     RECT  6.805 11.664 6.829 21.48 ;
     RECT  6.757 55.536 6.829 79.656 ;
     RECT  5.753 80.64 6.829 81.336 ;
     RECT  6.829 11.664 6.853 21.672 ;
     RECT  6.757 94.368 6.899 100.344 ;
     RECT  6.325 30.432 6.908 31.656 ;
     RECT  5.893 33.264 6.908 33.288 ;
     RECT  5.393 8.736 6.937 8.76 ;
     RECT  6.853 11.664 6.937 21.96 ;
     RECT  6.908 30.432 6.949 33.288 ;
     RECT  5.717 53.232 7.045 54.216 ;
     RECT  7.045 52.272 7.225 54.216 ;
     RECT  6.829 55.536 7.225 81.432 ;
     RECT  7.117 88.944 7.429 88.968 ;
     RECT  6.937 93.216 7.429 93.24 ;
     RECT  6.899 94.368 7.429 99.72 ;
     RECT  7.429 93.216 7.453 99.72 ;
     RECT  7.477 40.848 7.525 40.872 ;
     RECT  6.793 41.856 7.525 51.192 ;
     RECT  6.937 11.664 7.621 22.776 ;
     RECT  6.793 37.872 7.621 38.184 ;
     RECT  7.261 39.744 7.621 39.768 ;
     RECT  7.621 37.872 7.669 39.768 ;
     RECT  7.525 40.848 7.669 51.192 ;
     RECT  7.621 11.664 7.693 22.824 ;
     RECT  6.937 8.736 7.808 8.856 ;
     RECT  7.693 11.232 7.808 22.824 ;
     RECT  6.757 24.624 7.808 24.744 ;
     RECT  6.517 26.256 7.808 26.52 ;
     RECT  6.949 30.432 7.808 33.576 ;
     RECT  5.897 34.944 7.808 36.792 ;
     RECT  7.669 37.872 7.808 51.192 ;
     RECT  7.225 52.272 7.808 81.432 ;
     RECT  6.515 83.76 7.808 83.784 ;
     RECT  6.764 86.88 7.808 87.816 ;
     RECT  7.429 88.944 7.808 89.304 ;
     RECT  6.581 91.056 7.808 91.08 ;
     RECT  7.453 93.216 7.808 99.528 ;
     RECT  7.808 2.148 7.912 99.528 ;
     RECT  7.912 2.418 7.955 99.528 ;
     RECT  7.955 2.418 8.104 99.48 ;
     RECT  8.104 92.928 8.195 99.48 ;
     RECT  8.104 7.392 8.243 7.416 ;
     RECT  8.104 8.832 8.243 9.72 ;
     RECT  8.195 92.928 8.489 99.24 ;
     RECT  8.104 91.056 8.531 91.08 ;
     RECT  8.489 92.928 8.533 92.952 ;
     RECT  8.104 82.464 8.867 84.072 ;
     RECT  8.489 94.032 9.011 99.24 ;
     RECT  8.104 87.024 9.065 87.816 ;
     RECT  8.104 34.944 9.133 81.432 ;
     RECT  8.867 82.464 9.133 83.448 ;
     RECT  9.133 34.944 9.157 83.448 ;
     RECT  8.243 9.696 9.253 9.72 ;
     RECT  8.104 29.568 9.253 33.48 ;
     RECT  9.097 100.848 9.299 100.872 ;
     RECT  8.104 11.184 9.349 27.528 ;
     RECT  9.349 11.184 9.445 28.488 ;
     RECT  9.253 29.52 9.445 33.48 ;
     RECT  9.011 94.032 9.541 99.192 ;
     RECT  9.445 11.184 9.601 33.48 ;
     RECT  8.104 3.936 9.713 3.96 ;
     RECT  9.541 93.456 9.827 99.192 ;
     RECT  9.097 84.576 9.853 84.6 ;
     RECT  9.853 84.576 9.925 84.84 ;
     RECT  9.157 34.752 9.989 83.448 ;
     RECT  9.925 84.576 9.989 84.936 ;
     RECT  9.601 10.896 10.033 33.48 ;
     RECT  9.989 34.752 10.033 84.936 ;
     RECT  9.827 93.456 10.073 98.184 ;
     RECT  10.073 96.96 10.289 98.184 ;
     RECT  9.827 99.168 10.355 99.192 ;
     RECT  10.033 10.896 10.393 84.936 ;
     RECT  8.104 89.28 10.405 89.304 ;
     RECT  10.073 93.456 10.505 95.784 ;
     RECT  9.065 87.12 10.597 87.816 ;
     RECT  10.405 89.04 10.597 89.304 ;
     RECT  10.597 87.12 10.643 89.304 ;
     RECT  9.253 8.784 10.649 9.72 ;
     RECT  10.643 87.216 10.684 89.304 ;
     RECT  10.505 93.456 10.829 94.392 ;
     RECT  10.684 89.04 10.837 89.304 ;
     RECT  10.825 90.48 10.837 90.504 ;
     RECT  10.393 10.896 10.861 85.656 ;
     RECT  10.837 89.04 10.865 89.496 ;
     RECT  10.861 10.896 10.901 86.088 ;
     RECT  10.837 90.48 10.909 91.32 ;
     RECT  10.865 89.184 11.009 89.496 ;
     RECT  10.901 15.216 11.297 86.088 ;
     RECT  10.597 99.696 11.324 99.72 ;
     RECT  10.684 87.216 11.341 87.912 ;
     RECT  11.297 85.632 11.363 86.088 ;
     RECT  11.341 87.792 11.411 87.912 ;
     RECT  10.505 95.616 11.441 95.784 ;
     RECT  10.289 97.776 11.473 98.184 ;
     RECT  11.363 85.632 11.513 85.656 ;
     RECT  11.473 97.536 11.557 98.184 ;
     RECT  11.557 96.72 11.612 98.184 ;
     RECT  11.324 99.168 11.612 99.72 ;
     RECT  10.909 90.576 11.621 91.32 ;
     RECT  11.612 96.72 11.644 99.72 ;
     RECT  10.901 10.896 11.837 14.232 ;
     RECT  11.837 11.232 11.869 14.232 ;
     RECT  11.297 15.216 11.869 84.648 ;
     RECT  11.869 11.232 12.017 84.648 ;
     RECT  11.644 97.2 12.017 99.72 ;
     RECT  10.501 5.712 12.037 5.736 ;
     RECT  11.761 6.864 12.083 6.888 ;
     RECT  12.017 97.824 12.227 99.72 ;
     RECT  12.227 97.824 12.515 99.672 ;
     RECT  12.017 11.424 13.093 84.648 ;
     RECT  12.121 86.64 13.093 86.664 ;
     RECT  13.093 11.424 13.129 85.512 ;
     RECT  12.515 97.824 13.201 99.48 ;
     RECT  12.013 3.936 13.208 3.96 ;
     RECT  12.037 5.184 13.208 5.736 ;
     RECT  10.649 8.784 13.208 8.808 ;
     RECT  13.129 10.704 13.208 85.512 ;
     RECT  13.093 86.64 13.208 86.76 ;
     RECT  11.411 87.888 13.208 87.912 ;
     RECT  11.009 89.184 13.208 89.208 ;
     RECT  11.621 91.296 13.208 91.32 ;
     RECT  13.045 92.928 13.208 92.952 ;
     RECT  10.829 94.032 13.208 94.392 ;
     RECT  11.441 95.616 13.208 95.64 ;
     RECT  13.201 97.008 13.208 99.48 ;
     RECT  12.985 100.848 13.283 100.872 ;
     RECT  13.208 2.148 13.312 99.48 ;
     RECT  13.312 2.418 13.504 99.48 ;
     RECT  13.504 97.008 13.571 99.48 ;
     RECT  13.571 97.008 14.099 99.192 ;
     RECT  14.099 97.008 14.321 97.896 ;
     RECT  13.504 5.184 14.435 7.368 ;
     RECT  13.504 8.784 14.485 8.808 ;
     RECT  14.435 5.712 14.531 7.368 ;
     RECT  14.485 8.784 14.588 9.144 ;
     RECT  13.504 10.416 14.588 84.648 ;
     RECT  14.588 8.784 14.645 84.648 ;
     RECT  14.645 10.08 14.675 84.648 ;
     RECT  14.531 5.712 14.789 6.072 ;
     RECT  13.504 86.736 14.917 86.76 ;
     RECT  13.504 87.888 14.917 87.912 ;
     RECT  14.917 86.736 15.004 87.912 ;
     RECT  13.504 89.184 15.005 90.792 ;
     RECT  15.005 89.856 15.061 90.792 ;
     RECT  14.531 7.344 15.109 7.368 ;
     RECT  14.645 8.784 15.109 8.808 ;
     RECT  15.029 92.976 15.113 93 ;
     RECT  13.885 100.32 15.181 100.344 ;
     RECT  15.004 87.792 15.185 87.912 ;
     RECT  15.061 89.856 15.221 91.464 ;
     RECT  13.504 94.032 15.349 94.056 ;
     RECT  13.504 95.76 15.395 95.784 ;
     RECT  14.675 10.32 15.397 84.648 ;
     RECT  14.321 97.872 15.397 97.896 ;
     RECT  15.109 7.344 15.401 8.808 ;
     RECT  15.349 93.888 15.436 94.056 ;
     RECT  15.397 10.32 15.493 84.936 ;
     RECT  15.004 86.736 15.493 86.76 ;
     RECT  15.181 100.32 15.731 100.92 ;
     RECT  15.217 96.816 15.757 96.84 ;
     RECT  15.493 10.32 15.833 86.76 ;
     RECT  15.401 7.344 15.836 7.992 ;
     RECT  14.789 5.712 15.877 5.736 ;
     RECT  15.836 7.296 15.877 7.992 ;
     RECT  15.833 10.32 15.905 84.936 ;
     RECT  15.833 86.736 16.013 86.76 ;
     RECT  15.757 96.816 16.045 96.888 ;
     RECT  15.397 97.872 16.045 98.184 ;
     RECT  15.877 5.712 16.049 7.992 ;
     RECT  15.577 4.512 16.076 4.536 ;
     RECT  16.049 5.712 16.076 6.696 ;
     RECT  16.076 4.512 16.157 6.696 ;
     RECT  15.905 10.32 16.261 84.168 ;
     RECT  16.157 5.136 16.265 6.696 ;
     RECT  15.221 90.048 16.289 91.464 ;
     RECT  16.045 96.816 16.297 98.184 ;
     RECT  14.099 99.168 16.297 99.192 ;
     RECT  16.261 9.696 16.477 84.168 ;
     RECT  15.937 101.424 16.477 101.448 ;
     RECT  15.436 94.032 16.549 94.056 ;
     RECT  16.297 96.816 16.693 99.192 ;
     RECT  16.289 90.048 16.741 92.376 ;
     RECT  16.693 96.48 16.765 99.192 ;
     RECT  16.765 96.384 16.787 99.192 ;
     RECT  16.477 9.072 16.841 84.168 ;
     RECT  16.549 94.032 16.909 94.344 ;
     RECT  16.841 9.072 16.94 9.096 ;
     RECT  15.185 87.792 16.94 87.816 ;
     RECT  16.741 89.52 16.94 92.376 ;
     RECT  16.909 93.504 16.94 95.208 ;
     RECT  16.787 96.384 16.945 98.664 ;
     RECT  15.731 100.32 17.009 100.344 ;
     RECT  16.94 89.52 17.017 95.208 ;
     RECT  16.945 96.288 17.017 98.664 ;
     RECT  16.841 10.56 17.021 83.832 ;
     RECT  16.94 8.976 17.027 9.096 ;
     RECT  17.017 89.52 17.027 98.664 ;
     RECT  16.94 87.792 17.036 87.96 ;
     RECT  17.027 89.52 17.036 91.656 ;
     RECT  17.021 10.656 17.075 83.832 ;
     RECT  17.036 84.864 17.123 84.984 ;
     RECT  17.075 10.752 17.129 83.832 ;
     RECT  17.036 87.792 17.129 91.656 ;
     RECT  17.027 92.688 17.129 98.664 ;
     RECT  17.123 84.96 17.157 84.984 ;
     RECT  17.129 92.688 17.219 95.208 ;
     RECT  17.009 99.696 17.305 100.344 ;
     RECT  16.477 101.424 17.305 101.496 ;
     RECT  17.129 10.992 17.345 83.832 ;
     RECT  17.129 91.632 17.345 91.656 ;
     RECT  17.219 93.504 17.363 95.208 ;
     RECT  16.265 5.136 17.381 5.736 ;
     RECT  17.345 11.184 17.381 83.832 ;
     RECT  17.129 87.792 17.417 90.648 ;
     RECT  16.049 7.968 17.453 7.992 ;
     RECT  17.381 11.184 17.489 83.016 ;
     RECT  17.363 94.032 17.489 95.208 ;
     RECT  17.489 11.328 17.525 80.28 ;
     RECT  17.129 96.288 18.025 98.664 ;
     RECT  17.305 99.696 18.025 101.496 ;
     RECT  17.489 94.032 18.373 94.344 ;
     RECT  17.593 3.024 18.608 3.048 ;
     RECT  17.381 5.136 18.608 5.16 ;
     RECT  17.027 9.072 18.608 9.096 ;
     RECT  17.525 11.424 18.608 80.28 ;
     RECT  17.489 81.312 18.608 83.016 ;
     RECT  18.133 84.912 18.608 84.936 ;
     RECT  17.557 86.736 18.608 86.76 ;
     RECT  17.417 88.368 18.608 90.648 ;
     RECT  18.277 92.16 18.608 92.184 ;
     RECT  18.373 93.504 18.608 94.344 ;
     RECT  18.025 96.288 18.608 101.496 ;
     RECT  18.608 2.148 18.712 101.496 ;
     RECT  18.712 2.418 18.904 101.496 ;
     RECT  18.904 48.672 18.965 48.696 ;
     RECT  18.904 63.6 18.965 65.448 ;
     RECT  18.904 82.08 18.965 82.2 ;
     RECT  18.904 20.4 19.001 21.384 ;
     RECT  18.904 55.776 19.001 58.536 ;
     RECT  18.904 67.296 19.001 67.32 ;
     RECT  18.904 18.144 19.037 18.792 ;
     RECT  18.904 23.088 19.037 23.352 ;
     RECT  18.904 37.68 19.037 39.528 ;
     RECT  19.001 56.352 19.037 58.536 ;
     RECT  18.904 96.864 19.037 101.496 ;
     RECT  18.904 30.624 19.043 30.648 ;
     RECT  18.904 36.528 19.043 36.552 ;
     RECT  19.037 37.872 19.043 39.528 ;
     RECT  18.904 44.928 19.043 45.192 ;
     RECT  19.037 96.864 19.043 97.368 ;
     RECT  19.043 96.864 19.045 97.08 ;
     RECT  19.001 21.12 19.073 21.384 ;
     RECT  18.904 29.328 19.073 29.352 ;
     RECT  18.904 46.608 19.073 47.448 ;
     RECT  18.904 53.856 19.073 53.88 ;
     RECT  19.037 56.784 19.145 58.536 ;
     RECT  19.073 21.36 19.181 21.384 ;
     RECT  19.043 37.92 19.181 39.528 ;
     RECT  19.145 56.784 19.217 57.672 ;
     RECT  19.037 98.4 19.217 101.496 ;
     RECT  19.181 38.688 19.253 39.528 ;
     RECT  19.073 46.608 19.253 47.4 ;
     RECT  19.253 38.688 19.325 38.712 ;
     RECT  18.904 62.448 19.325 62.568 ;
     RECT  18.904 26.592 19.361 26.616 ;
     RECT  19.325 62.544 19.427 62.568 ;
     RECT  18.904 88.416 19.427 88.968 ;
     RECT  18.904 61.152 19.433 61.464 ;
     RECT  18.904 12.48 19.469 12.504 ;
     RECT  18.904 51.936 19.469 52.536 ;
     RECT  18.965 64.992 19.475 65.448 ;
     RECT  19.427 88.944 19.475 88.968 ;
     RECT  19.045 97.008 19.475 97.08 ;
     RECT  19.217 56.784 19.505 56.808 ;
     RECT  19.475 64.992 19.523 65.208 ;
     RECT  18.904 86.736 19.523 86.76 ;
     RECT  19.037 23.328 19.541 23.352 ;
     RECT  19.043 45.168 19.541 45.192 ;
     RECT  18.965 63.6 19.571 63.624 ;
     RECT  18.965 82.08 19.571 82.104 ;
     RECT  18.904 31.872 19.577 32.856 ;
     RECT  19.433 61.44 19.619 61.464 ;
     RECT  18.904 59.52 19.793 60.072 ;
     RECT  19.793 60.048 19.829 60.072 ;
     RECT  18.904 94.032 19.829 94.056 ;
     RECT  19.523 65.184 19.901 65.208 ;
     RECT  18.904 69.744 19.933 69.768 ;
     RECT  18.904 70.8 19.933 70.824 ;
     RECT  19.217 99.312 20.003 101.496 ;
     RECT  18.904 83.184 20.009 83.208 ;
     RECT  18.904 76.512 20.153 76.536 ;
     RECT  19.253 46.608 20.252 46.632 ;
     RECT  19.475 97.056 20.291 97.08 ;
     RECT  19.933 69.744 20.329 70.824 ;
     RECT  20.252 46.608 20.339 46.68 ;
     RECT  20.149 93.504 20.339 93.528 ;
     RECT  19.969 6.24 20.369 6.264 ;
     RECT  20.339 46.608 20.477 46.632 ;
     RECT  20.041 63.504 20.477 63.528 ;
     RECT  20.185 48.816 20.509 48.84 ;
     RECT  20.509 73.296 20.545 73.32 ;
     RECT  19.037 18.768 20.693 18.792 ;
     RECT  20.581 29.04 20.693 29.064 ;
     RECT  20.797 58.656 20.941 58.68 ;
     RECT  20.293 25.056 20.977 25.08 ;
     RECT  20.509 48.144 21.013 48.84 ;
     RECT  20.003 99.696 21.059 101.496 ;
     RECT  19.577 31.872 21.085 32.712 ;
     RECT  20.941 58.656 21.121 58.728 ;
     RECT  20.329 69.744 21.157 70.872 ;
     RECT  20.437 12.816 21.197 12.84 ;
     RECT  21.121 58.272 21.197 58.728 ;
     RECT  21.059 100.944 21.251 101.496 ;
     RECT  21.013 48.144 21.265 48.984 ;
     RECT  20.725 67.008 21.265 67.032 ;
     RECT  21.265 48.144 21.337 49.608 ;
     RECT  21.409 11.04 21.445 11.064 ;
     RECT  20.977 24.672 21.517 25.08 ;
     RECT  21.409 37.632 21.517 37.656 ;
     RECT  21.085 42.576 21.517 42.6 ;
     RECT  21.157 69.6 21.517 70.872 ;
     RECT  21.085 78.864 21.517 78.888 ;
     RECT  21.445 7.728 21.553 7.752 ;
     RECT  21.085 31.872 21.553 33.528 ;
     RECT  21.517 93.504 21.553 93.528 ;
     RECT  20.833 63.6 21.589 63.624 ;
     RECT  20.473 65.664 21.589 65.688 ;
     RECT  21.265 67.008 21.589 67.128 ;
     RECT  20.581 20.016 21.625 20.04 ;
     RECT  21.085 21.552 21.625 21.576 ;
     RECT  21.553 31.872 21.625 33.96 ;
     RECT  21.337 47.328 21.625 49.608 ;
     RECT  21.085 56.4 21.625 56.424 ;
     RECT  21.197 58.272 21.625 58.68 ;
     RECT  21.589 63.024 21.625 63.624 ;
     RECT  20.545 73.296 21.625 73.944 ;
     RECT  21.409 86.496 21.625 86.52 ;
     RECT  21.085 87.744 21.625 87.768 ;
     RECT  21.409 90.24 21.625 90.264 ;
     RECT  21.589 91.248 21.625 91.272 ;
     RECT  21.625 47.328 21.637 50.04 ;
     RECT  21.553 7.536 21.661 7.752 ;
     RECT  20.617 16.272 21.661 17.064 ;
     RECT  19.969 26.304 21.661 26.328 ;
     RECT  21.625 30.24 21.661 30.264 ;
     RECT  21.625 31.44 21.661 34.152 ;
     RECT  21.637 46.512 21.661 50.04 ;
     RECT  19.469 51.936 21.661 51.96 ;
     RECT  21.625 53.52 21.661 53.544 ;
     RECT  21.589 65.664 21.661 67.128 ;
     RECT  21.625 73.296 21.661 74.568 ;
     RECT  21.553 92.688 21.661 93.528 ;
     RECT  21.589 94.752 21.661 94.776 ;
     RECT  21.157 5.28 21.697 5.304 ;
     RECT  21.661 6.528 21.697 6.552 ;
     RECT  21.661 16.272 21.697 17.88 ;
     RECT  21.625 20.016 21.697 20.328 ;
     RECT  21.625 21.552 21.697 22.392 ;
     RECT  21.661 46.512 21.697 50.856 ;
     RECT  21.661 51.936 21.697 53.544 ;
     RECT  21.661 65.472 21.697 67.128 ;
     RECT  21.625 76.176 21.697 76.2 ;
     RECT  21.625 85.68 21.697 86.52 ;
     RECT  21.625 90.24 21.697 91.272 ;
     RECT  21.661 92.688 21.697 94.776 ;
     RECT  21.445 10.848 21.733 11.064 ;
     RECT  21.517 12.912 21.733 13.56 ;
     RECT  21.625 15.168 21.733 15.192 ;
     RECT  21.697 16.272 21.733 18.696 ;
     RECT  21.697 19.728 21.733 20.328 ;
     RECT  21.661 29.376 21.733 30.264 ;
     RECT  21.661 31.44 21.733 34.584 ;
     RECT  21.517 37.632 21.733 37.896 ;
     RECT  21.661 45.072 21.733 45.096 ;
     RECT  21.697 59.712 21.733 59.736 ;
     RECT  21.661 61.344 21.733 61.56 ;
     RECT  21.625 62.592 21.733 63.624 ;
     RECT  21.697 65.472 21.733 67.752 ;
     RECT  21.517 68.976 21.733 70.872 ;
     RECT  21.481 71.856 21.733 71.88 ;
     RECT  21.661 73.296 21.733 74.76 ;
     RECT  21.697 76.176 21.733 76.44 ;
     RECT  21.517 78.864 21.733 79.512 ;
     RECT  21.625 80.736 21.733 81.192 ;
     RECT  20.041 82.176 21.733 82.2 ;
     RECT  21.625 87.744 21.733 89.208 ;
     RECT  21.697 90.24 21.733 94.776 ;
     RECT  21.337 97.872 21.733 97.896 ;
     RECT  21.589 9.792 21.769 9.816 ;
     RECT  21.733 12.912 21.769 15.192 ;
     RECT  21.733 16.272 21.769 20.328 ;
     RECT  21.733 36.192 21.769 36.216 ;
     RECT  21.625 39.504 21.769 39.528 ;
     RECT  21.733 45.072 21.769 45.48 ;
     RECT  21.733 65.088 21.769 71.88 ;
     RECT  20.725 84.24 21.769 84.264 ;
     RECT  21.697 85.68 21.769 86.76 ;
     RECT  21.697 96.528 21.769 96.552 ;
     RECT  21.733 97.872 21.769 98.424 ;
     RECT  21.373 3.408 21.805 3.432 ;
     RECT  21.697 4.464 21.805 6.552 ;
     RECT  21.661 7.536 21.805 8.184 ;
     RECT  21.769 9.168 21.805 9.816 ;
     RECT  21.733 10.848 21.805 11.88 ;
     RECT  21.697 28.176 21.805 28.2 ;
     RECT  21.733 29.184 21.805 34.584 ;
     RECT  21.769 39.504 21.805 39.72 ;
     RECT  21.625 41.136 21.805 41.16 ;
     RECT  21.697 46.512 21.805 53.544 ;
     RECT  21.625 55.776 21.805 58.68 ;
     RECT  21.769 65.088 21.805 72.12 ;
     RECT  21.733 73.296 21.805 76.44 ;
     RECT  21.733 78.048 21.805 79.512 ;
     RECT  21.661 26.304 21.841 26.52 ;
     RECT  21.805 28.176 21.841 34.584 ;
     RECT  21.769 36.192 21.841 36.648 ;
     RECT  21.733 37.632 21.841 38.28 ;
     RECT  21.805 39.504 21.841 41.16 ;
     RECT  21.769 44.64 21.841 45.48 ;
     RECT  21.805 46.512 21.841 54.36 ;
     RECT  21.733 59.712 21.841 64.056 ;
     RECT  21.805 65.088 21.841 79.512 ;
     RECT  21.733 87.744 21.841 94.776 ;
     RECT  21.769 96.528 21.841 98.424 ;
     RECT  21.841 28.176 21.877 35.208 ;
     RECT  21.841 36.192 21.877 38.28 ;
     RECT  21.769 12.912 22.165 20.328 ;
     RECT  21.697 21.552 22.165 22.824 ;
     RECT  21.517 23.808 22.165 25.08 ;
     RECT  21.841 39.504 22.165 41.592 ;
     RECT  21.517 42.576 22.165 43.416 ;
     RECT  21.805 3.408 22.201 6.552 ;
     RECT  21.805 7.536 22.201 11.88 ;
     RECT  22.165 12.912 22.201 25.08 ;
     RECT  21.877 28.176 22.201 38.28 ;
     RECT  22.165 39.504 22.201 43.416 ;
     RECT  21.841 44.64 22.201 54.36 ;
     RECT  21.805 55.392 22.201 58.68 ;
     RECT  21.841 59.712 22.201 79.512 ;
     RECT  21.733 80.736 22.201 82.2 ;
     RECT  21.769 84.24 22.201 86.76 ;
     RECT  21.841 87.744 22.201 98.424 ;
     RECT  22.201 39.504 22.237 58.68 ;
     RECT  22.201 59.712 22.237 79.752 ;
     RECT  21.251 100.944 22.307 101.4 ;
     RECT  22.201 3.408 22.741 25.08 ;
     RECT  21.841 26.304 22.741 26.952 ;
     RECT  22.237 39.504 22.741 79.752 ;
     RECT  22.201 80.736 22.741 82.392 ;
     RECT  22.741 3.216 22.777 25.08 ;
     RECT  22.741 26.112 22.777 26.952 ;
     RECT  22.201 28.176 22.777 38.472 ;
     RECT  22.741 39.504 22.777 82.392 ;
     RECT  22.777 3.024 22.813 82.392 ;
     RECT  22.201 83.808 22.813 98.424 ;
     RECT  21.059 99.696 22.835 99.72 ;
     RECT  22.307 100.944 23.315 100.968 ;
     RECT  22.813 2.592 23.641 98.424 ;
     RECT  23.641 2.592 23.724 98.712 ;
    LAYER M5 ;
     RECT  2.4 2.137 2.52 2.151 ;
     RECT  7.8 2.137 7.92 2.151 ;
     RECT  13.2 2.137 13.32 2.151 ;
     RECT  18.6 2.137 18.72 2.151 ;
     RECT  2.4 2.151 2.712 3.925 ;
     RECT  7.8 2.151 8.112 3.925 ;
     RECT  13.2 2.151 13.512 3.925 ;
     RECT  12.528 3.925 13.512 5.173 ;
     RECT  12.048 5.173 14.424 5.219 ;
     RECT  16.128 5.221 16.152 6.661 ;
     RECT  15.888 6.661 16.152 6.707 ;
     RECT  13.2 5.219 14.424 6.805 ;
     RECT  12.048 5.219 12.072 6.899 ;
     RECT  15.888 6.707 15.912 7.331 ;
     RECT  2.4 3.925 3.192 7.381 ;
     RECT  2.4 7.381 4.008 8.149 ;
     RECT  5.424 6.805 5.448 8.149 ;
     RECT  2.4 8.149 4.248 8.195 ;
     RECT  5.232 8.149 5.448 8.771 ;
     RECT  16.992 7.957 17.016 9.011 ;
     RECT  16.56 9.637 16.584 9.685 ;
     RECT  7.8 3.925 8.232 9.731 ;
     RECT  2.4 8.195 3.192 10.019 ;
     RECT  13.2 6.805 14.52 10.069 ;
     RECT  4.224 8.195 4.248 10.355 ;
     RECT  16.272 9.685 16.584 10.645 ;
     RECT  13.2 10.069 14.664 11.461 ;
     RECT  12.336 11.461 14.664 11.509 ;
     RECT  9.264 8.773 9.288 11.557 ;
     RECT  10.512 5.701 10.536 11.557 ;
     RECT  16.272 10.645 17.064 11.749 ;
     RECT  18.6 2.151 18.912 11.749 ;
     RECT  9.264 11.557 10.536 11.797 ;
     RECT  16.272 11.749 18.912 11.941 ;
     RECT  9.264 11.797 10.584 11.989 ;
     RECT  11.664 11.509 14.664 11.989 ;
     RECT  6.528 12.181 6.552 12.517 ;
     RECT  7.8 9.731 8.112 12.517 ;
     RECT  6.528 12.517 8.112 12.805 ;
     RECT  9.264 11.989 14.664 12.805 ;
     RECT  6.528 12.805 14.664 13.045 ;
     RECT  6.528 13.045 14.808 13.093 ;
     RECT  15.984 11.941 18.912 13.093 ;
     RECT  5.424 8.771 5.448 13.525 ;
     RECT  6.528 13.093 18.912 13.525 ;
     RECT  5.424 13.525 18.912 13.571 ;
     RECT  5.424 13.571 6.312 13.955 ;
     RECT  3.984 12.517 4.008 14.581 ;
     RECT  3.984 14.581 4.488 14.627 ;
     RECT  6.288 13.955 6.312 15.157 ;
     RECT  7.392 13.571 18.912 15.157 ;
     RECT  6.288 15.157 18.912 15.203 ;
     RECT  6.528 15.203 18.912 15.251 ;
     RECT  2.4 10.019 2.712 15.589 ;
     RECT  4.464 14.627 4.488 15.589 ;
     RECT  6.528 15.251 6.552 17.077 ;
     RECT  7.584 15.251 18.912 17.077 ;
     RECT  6.528 17.077 18.912 17.411 ;
     RECT  2.4 15.589 4.488 17.461 ;
     RECT  2.4 17.461 4.68 18.803 ;
     RECT  7.584 17.411 18.912 19.571 ;
     RECT  2.4 18.803 4.488 20.819 ;
     RECT  6.528 17.411 6.552 21.013 ;
     RECT  7.632 19.571 18.912 21.013 ;
     RECT  2.4 20.819 2.856 23.075 ;
     RECT  4.464 20.819 4.488 23.317 ;
     RECT  3.984 23.317 4.488 24.563 ;
     RECT  2.4 23.075 2.712 25.573 ;
     RECT  6.528 21.013 18.912 26.291 ;
     RECT  2.4 25.573 3.432 26.725 ;
     RECT  4.464 24.563 4.488 26.725 ;
     RECT  2.4 26.725 4.488 28.837 ;
     RECT  2.4 28.837 4.536 28.979 ;
     RECT  2.4 28.979 3.432 30.323 ;
     RECT  6.816 26.291 18.912 30.613 ;
     RECT  4.464 28.979 4.536 31.285 ;
     RECT  4.224 31.285 4.536 31.621 ;
     RECT  2.4 30.323 3.144 32.531 ;
     RECT  2.4 32.531 2.712 33.589 ;
     RECT  4.224 31.621 4.68 33.589 ;
     RECT  2.4 33.589 4.68 34.643 ;
     RECT  4.224 34.643 4.68 34.835 ;
     RECT  5.808 34.933 5.832 35.173 ;
     RECT  6.816 30.613 19.032 35.173 ;
     RECT  4.224 34.835 4.248 35.797 ;
     RECT  4.08 35.797 4.248 36.133 ;
     RECT  5.808 35.173 19.032 36.133 ;
     RECT  2.4 34.643 2.712 36.373 ;
     RECT  4.08 36.133 19.032 36.373 ;
     RECT  2.4 36.373 19.032 36.563 ;
     RECT  2.4 36.563 18.912 37.043 ;
     RECT  4.08 37.043 18.912 37.861 ;
     RECT  4.08 37.861 19.032 40.211 ;
     RECT  5.808 40.211 19.032 41.221 ;
     RECT  4.08 40.211 4.248 41.845 ;
     RECT  2.4 37.043 2.712 42.565 ;
     RECT  3.84 41.845 4.248 42.565 ;
     RECT  5.712 41.221 19.032 42.803 ;
     RECT  2.4 42.565 4.536 43.285 ;
     RECT  2.4 43.285 4.584 44.245 ;
     RECT  5.808 42.803 19.032 44.245 ;
     RECT  2.4 44.245 19.032 44.963 ;
     RECT  21.648 46.501 21.672 47.363 ;
     RECT  2.4 44.963 18.912 50.291 ;
     RECT  0.24 51.205 0.264 51.445 ;
     RECT  0.144 51.445 0.264 52.211 ;
     RECT  0.144 52.211 0.168 52.499 ;
     RECT  0.144 54.613 0.168 55.139 ;
     RECT  2.4 50.291 2.712 55.237 ;
     RECT  3.84 50.291 18.912 55.237 ;
     RECT  2.4 55.237 18.912 55.859 ;
     RECT  2.4 55.859 2.712 58.117 ;
     RECT  3.84 55.859 18.912 58.117 ;
     RECT  0.144 56.197 0.168 60.949 ;
     RECT  2.4 58.117 18.912 61.429 ;
     RECT  20.304 46.645 20.328 61.429 ;
     RECT  0.144 60.949 0.264 62.005 ;
     RECT  0.144 62.005 0.312 62.483 ;
     RECT  0.144 62.483 0.168 62.771 ;
     RECT  0.144 64.885 0.168 65.509 ;
     RECT  0.144 65.509 0.216 65.795 ;
     RECT  0.144 65.795 0.168 67.189 ;
     RECT  0.144 67.189 0.216 67.331 ;
     RECT  0.144 67.331 0.168 68.293 ;
     RECT  0.144 68.293 0.216 68.531 ;
     RECT  2.4 61.429 20.328 68.917 ;
     RECT  2.304 68.917 20.328 69.971 ;
     RECT  0.144 68.531 0.168 70.021 ;
     RECT  0.144 70.021 0.216 70.163 ;
     RECT  2.304 69.971 2.712 71.315 ;
     RECT  0.144 70.163 0.168 71.461 ;
     RECT  0.144 71.461 0.264 71.987 ;
     RECT  0.144 71.987 0.216 72.995 ;
     RECT  0.192 72.995 0.216 73.475 ;
     RECT  2.4 71.315 2.712 73.957 ;
     RECT  3.84 69.971 20.328 73.957 ;
     RECT  0.144 74.149 0.168 74.533 ;
     RECT  2.4 73.957 20.328 74.627 ;
     RECT  0.144 74.533 0.408 75.299 ;
     RECT  0.144 75.299 0.216 75.683 ;
     RECT  0.144 75.683 0.168 75.971 ;
     RECT  0.144 77.461 0.168 78.565 ;
     RECT  0.144 78.565 0.264 78.613 ;
     RECT  0.144 78.613 0.36 78.707 ;
     RECT  0.24 78.707 0.36 78.755 ;
     RECT  0.336 78.755 0.36 78.995 ;
     RECT  2.4 74.627 2.712 80.917 ;
     RECT  0.144 80.293 0.168 82.213 ;
     RECT  0.144 82.213 0.264 82.691 ;
     RECT  2.4 80.917 2.808 83.267 ;
     RECT  0.144 82.691 0.168 83.749 ;
     RECT  3.84 74.627 20.328 83.843 ;
     RECT  12.864 83.843 20.328 84.035 ;
     RECT  12.864 84.035 14.088 84.179 ;
     RECT  2.4 83.267 2.712 84.853 ;
     RECT  0.144 83.749 0.312 84.995 ;
     RECT  13.2 84.179 14.088 85.477 ;
     RECT  0.192 84.995 0.312 85.523 ;
     RECT  0.288 85.523 0.312 85.955 ;
     RECT  3.84 83.843 11.352 86.099 ;
     RECT  13.104 85.477 14.088 86.725 ;
     RECT  15.456 84.035 20.328 86.725 ;
     RECT  13.104 86.725 20.328 86.771 ;
     RECT  3.84 86.099 11.304 87.251 ;
     RECT  2.304 84.853 2.712 87.299 ;
     RECT  13.2 86.771 20.328 87.299 ;
     RECT  0.144 87.637 0.168 87.733 ;
     RECT  10.416 87.251 11.304 87.781 ;
     RECT  0.144 87.733 0.264 87.875 ;
     RECT  10.416 87.781 11.4 87.923 ;
     RECT  2.4 87.299 2.712 88.885 ;
     RECT  3.84 87.251 9.192 88.885 ;
     RECT  15.456 87.299 20.328 88.979 ;
     RECT  10.416 87.923 10.632 89.075 ;
     RECT  10.608 89.075 10.632 89.315 ;
     RECT  15.456 88.979 18.912 89.699 ;
     RECT  15.456 89.699 16.344 89.845 ;
     RECT  15.072 89.845 16.344 90.083 ;
     RECT  2.304 88.885 9.192 90.515 ;
     RECT  0.144 87.875 0.168 90.517 ;
     RECT  3.84 90.515 9.192 90.659 ;
     RECT  17.328 89.699 18.912 90.659 ;
     RECT  13.2 87.299 14.088 90.803 ;
     RECT  13.2 90.803 13.512 91.285 ;
     RECT  10.848 89.461 10.872 91.331 ;
     RECT  2.304 90.515 2.712 91.379 ;
     RECT  16.32 90.083 16.344 91.621 ;
     RECT  17.328 90.659 17.352 91.621 ;
     RECT  0.144 90.517 0.216 91.717 ;
     RECT  18.6 90.659 18.912 92.149 ;
     RECT  16.32 91.621 17.352 92.387 ;
     RECT  16.992 92.387 17.352 92.675 ;
     RECT  17.088 92.675 17.352 92.963 ;
     RECT  15.072 90.083 15.096 93.011 ;
     RECT  17.184 92.963 17.352 93.395 ;
     RECT  6.096 90.659 9.192 93.445 ;
     RECT  0.144 91.717 0.264 93.539 ;
     RECT  17.328 93.395 17.352 93.539 ;
     RECT  18.384 92.149 18.912 93.539 ;
     RECT  20.304 88.979 20.328 93.539 ;
     RECT  0.192 93.539 0.264 93.683 ;
     RECT  0.24 93.683 0.264 93.781 ;
     RECT  2.4 91.379 2.712 94.021 ;
     RECT  6.096 93.445 9.576 94.021 ;
     RECT  13.056 91.285 13.512 94.213 ;
     RECT  0.24 93.781 0.312 94.355 ;
     RECT  6.096 94.021 9.672 94.691 ;
     RECT  0.288 94.355 0.312 95.123 ;
     RECT  6.096 94.691 9.24 95.171 ;
     RECT  3.84 90.659 5.064 95.173 ;
     RECT  6.096 95.171 6.6 95.173 ;
     RECT  12.816 94.213 13.512 95.651 ;
     RECT  2.4 94.021 2.808 95.795 ;
     RECT  15.36 93.877 15.384 95.795 ;
     RECT  7.8 95.171 9.24 95.891 ;
     RECT  3.84 95.173 6.6 95.939 ;
     RECT  0.144 95.701 0.168 96.229 ;
     RECT  0.144 96.229 0.264 96.371 ;
     RECT  7.8 95.891 9.192 96.371 ;
     RECT  5.808 95.939 6.6 96.419 ;
     RECT  18.6 93.539 18.912 96.853 ;
     RECT  7.8 96.371 8.952 96.947 ;
     RECT  18.6 96.853 19.032 96.997 ;
     RECT  18.6 96.997 19.464 97.045 ;
     RECT  3.84 95.939 4.584 97.381 ;
     RECT  11.568 95.605 11.592 97.571 ;
     RECT  3.84 97.381 5.4 97.763 ;
     RECT  3.84 97.763 3.864 97.811 ;
     RECT  7.8 96.947 8.472 97.811 ;
     RECT  0.24 96.371 0.264 98.147 ;
     RECT  9.696 97.381 9.72 98.341 ;
     RECT  13.2 95.651 13.512 98.629 ;
     RECT  6.576 96.419 6.6 98.675 ;
     RECT  17.088 97.381 17.112 98.675 ;
     RECT  10.848 98.149 10.872 98.677 ;
     RECT  9.504 98.341 9.72 98.917 ;
     RECT  2.4 95.795 2.712 99.157 ;
     RECT  5.088 97.763 5.4 99.157 ;
     RECT  7.8 97.811 8.112 99.157 ;
     RECT  9.504 98.917 9.816 99.157 ;
     RECT  10.848 98.677 11.688 99.157 ;
     RECT  13.2 98.629 14.088 99.157 ;
     RECT  18.6 97.045 20.28 99.157 ;
     RECT  2.4 99.157 6.12 99.383 ;
     RECT  2.784 99.383 6.12 99.685 ;
     RECT  7.104 99.157 16.776 99.685 ;
     RECT  18.096 99.157 20.28 99.685 ;
     RECT  2.784 99.685 20.28 99.973 ;
     RECT  21.792 51.925 21.816 99.973 ;
     RECT  22.8 99.685 22.824 100.933 ;
     RECT  2.784 99.973 21.816 101.365 ;
     RECT  22.8 100.933 23.304 101.365 ;
     RECT  2.64 101.365 23.304 101.456 ;
     RECT  20.4 101.456 21.24 101.459 ;
     RECT  21.216 101.459 21.24 101.507 ;
  END
END ot_hgi_coll_qso_n1s0_b32
END LIBRARY
